VERSION 5.7 ;
BUSBITCHARS "[]" ;
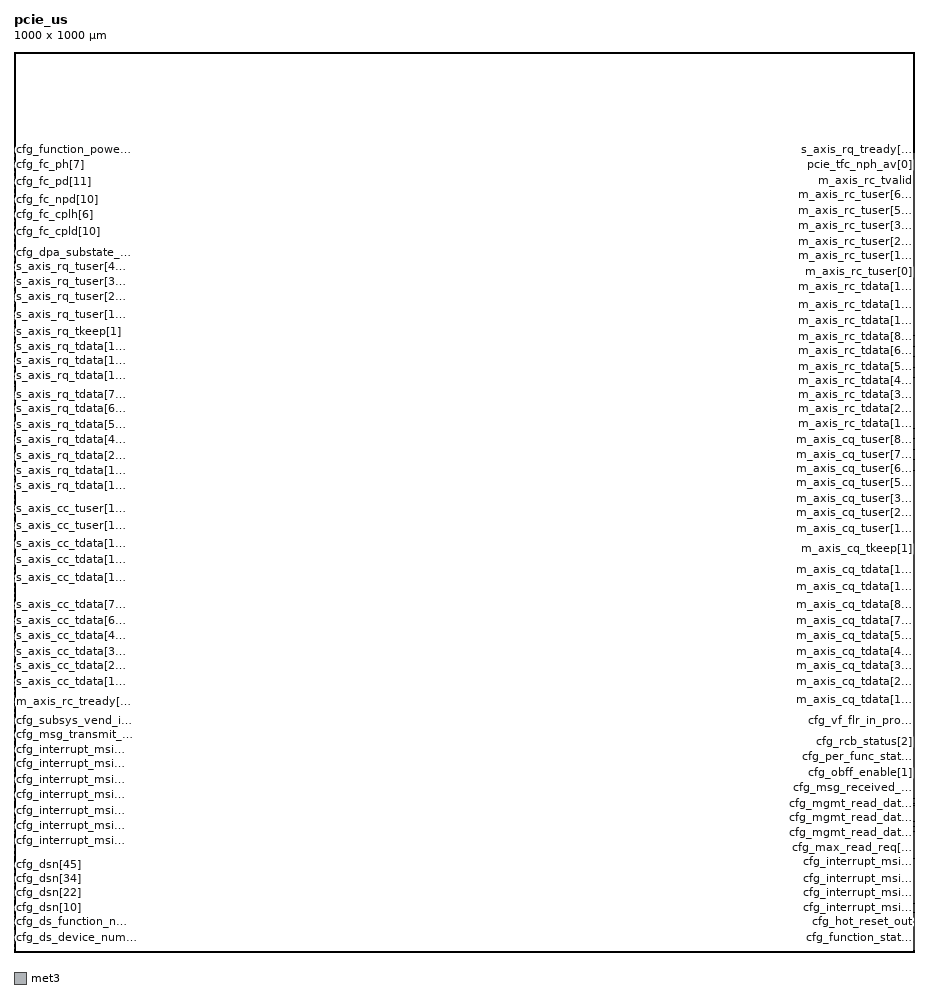
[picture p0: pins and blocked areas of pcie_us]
MACRO pcie_us
  CLASS BLOCK ;
  FOREIGN pcie_us 0 0 ;
  SYMMETRY X Y R90 ;
  SIZE 1000.000 BY 1000.000 ;
  PIN cfg_config_space_enable
    DIRECTION INPUT ;
    USE SIGNAL ;
    PORT
      LAYER met3 ;
      RECT 0.000 2.910 0.680 3.210 ;
    END
  END cfg_config_space_enable
  PIN cfg_ds_bus_number[0]
    DIRECTION INPUT ;
    USE SIGNAL ;
    PORT
      LAYER met3 ;
      RECT 0.000 4.270 0.680 4.570 ;
    END
  END cfg_ds_bus_number[0]
  PIN cfg_ds_bus_number[1]
    DIRECTION INPUT ;
    USE SIGNAL ;
    PORT
      LAYER met3 ;
      RECT 0.000 5.630 0.680 5.930 ;
    END
  END cfg_ds_bus_number[1]
  PIN cfg_ds_bus_number[2]
    DIRECTION INPUT ;
    USE SIGNAL ;
    PORT
      LAYER met3 ;
      RECT 0.000 6.990 0.680 7.290 ;
    END
  END cfg_ds_bus_number[2]
  PIN cfg_ds_bus_number[3]
    DIRECTION INPUT ;
    USE SIGNAL ;
    PORT
      LAYER met3 ;
      RECT 0.000 8.350 0.680 8.650 ;
    END
  END cfg_ds_bus_number[3]
  PIN cfg_ds_bus_number[4]
    DIRECTION INPUT ;
    USE SIGNAL ;
    PORT
      LAYER met3 ;
      RECT 0.000 9.710 0.680 10.010 ;
    END
  END cfg_ds_bus_number[4]
  PIN cfg_ds_bus_number[5]
    DIRECTION INPUT ;
    USE SIGNAL ;
    PORT
      LAYER met3 ;
      RECT 0.000 11.070 0.680 11.370 ;
    END
  END cfg_ds_bus_number[5]
  PIN cfg_ds_bus_number[6]
    DIRECTION INPUT ;
    USE SIGNAL ;
    PORT
      LAYER met3 ;
      RECT 0.000 12.430 0.680 12.730 ;
    END
  END cfg_ds_bus_number[6]
  PIN cfg_ds_bus_number[7]
    DIRECTION INPUT ;
    USE SIGNAL ;
    PORT
      LAYER met3 ;
      RECT 0.000 13.790 0.680 14.090 ;
    END
  END cfg_ds_bus_number[7]
  PIN cfg_ds_device_number[0]
    DIRECTION INPUT ;
    USE SIGNAL ;
    PORT
      LAYER met3 ;
      RECT 0.000 15.150 0.680 15.450 ;
    END
  END cfg_ds_device_number[0]
  PIN cfg_ds_device_number[1]
    DIRECTION INPUT ;
    USE SIGNAL ;
    PORT
      LAYER met3 ;
      RECT 0.000 16.510 0.680 16.810 ;
    END
  END cfg_ds_device_number[1]
  PIN cfg_ds_device_number[2]
    DIRECTION INPUT ;
    USE SIGNAL ;
    PORT
      LAYER met3 ;
      RECT 0.000 17.190 0.680 17.490 ;
    END
  END cfg_ds_device_number[2]
  PIN cfg_ds_device_number[3]
    DIRECTION INPUT ;
    USE SIGNAL ;
    PORT
      LAYER met3 ;
      RECT 0.000 18.550 0.680 18.850 ;
    END
  END cfg_ds_device_number[3]
  PIN cfg_ds_device_number[4]
    DIRECTION INPUT ;
    USE SIGNAL ;
    PORT
      LAYER met3 ;
      RECT 0.000 19.910 0.680 20.210 ;
    END
  END cfg_ds_device_number[4]
  PIN cfg_ds_function_number[0]
    DIRECTION INPUT ;
    USE SIGNAL ;
    PORT
      LAYER met3 ;
      RECT 0.000 21.950 0.680 22.250 ;
    END
  END cfg_ds_function_number[0]
  PIN cfg_ds_function_number[1]
    DIRECTION INPUT ;
    USE SIGNAL ;
    PORT
      LAYER met3 ;
      RECT 0.000 23.310 0.680 23.610 ;
    END
  END cfg_ds_function_number[1]
  PIN cfg_ds_function_number[2]
    DIRECTION INPUT ;
    USE SIGNAL ;
    PORT
      LAYER met3 ;
      RECT 0.000 24.670 0.680 24.970 ;
    END
  END cfg_ds_function_number[2]
  PIN cfg_ds_port_number
    DIRECTION INPUT ;
    USE SIGNAL ;
    PORT
      LAYER met3 ;
      RECT 0.000 26.030 0.680 26.330 ;
    END
  END cfg_ds_port_number
  PIN cfg_dsn[0]
    DIRECTION INPUT ;
    USE SIGNAL ;
    PORT
      LAYER met3 ;
      RECT 0.000 26.710 0.680 27.010 ;
    END
  END cfg_dsn[0]
  PIN cfg_dsn[1]
    DIRECTION INPUT ;
    USE SIGNAL ;
    PORT
      LAYER met3 ;
      RECT 0.000 28.750 0.680 29.050 ;
    END
  END cfg_dsn[1]
  PIN cfg_dsn[2]
    DIRECTION INPUT ;
    USE SIGNAL ;
    PORT
      LAYER met3 ;
      RECT 0.000 30.110 0.680 30.410 ;
    END
  END cfg_dsn[2]
  PIN cfg_dsn[3]
    DIRECTION INPUT ;
    USE SIGNAL ;
    PORT
      LAYER met3 ;
      RECT 0.000 31.470 0.680 31.770 ;
    END
  END cfg_dsn[3]
  PIN cfg_dsn[4]
    DIRECTION INPUT ;
    USE SIGNAL ;
    PORT
      LAYER met3 ;
      RECT 0.000 32.150 0.680 32.450 ;
    END
  END cfg_dsn[4]
  PIN cfg_dsn[5]
    DIRECTION INPUT ;
    USE SIGNAL ;
    PORT
      LAYER met3 ;
      RECT 0.000 33.510 0.680 33.810 ;
    END
  END cfg_dsn[5]
  PIN cfg_dsn[6]
    DIRECTION INPUT ;
    USE SIGNAL ;
    PORT
      LAYER met3 ;
      RECT 0.000 34.870 0.680 35.170 ;
    END
  END cfg_dsn[6]
  PIN cfg_dsn[7]
    DIRECTION INPUT ;
    USE SIGNAL ;
    PORT
      LAYER met3 ;
      RECT 0.000 36.230 0.680 36.530 ;
    END
  END cfg_dsn[7]
  PIN cfg_dsn[8]
    DIRECTION INPUT ;
    USE SIGNAL ;
    PORT
      LAYER met3 ;
      RECT 0.000 37.590 0.680 37.890 ;
    END
  END cfg_dsn[8]
  PIN cfg_dsn[9]
    DIRECTION INPUT ;
    USE SIGNAL ;
    PORT
      LAYER met3 ;
      RECT 0.000 39.630 0.680 39.930 ;
    END
  END cfg_dsn[9]
  PIN cfg_dsn[10]
    DIRECTION INPUT ;
    USE SIGNAL ;
    PORT
      LAYER met3 ;
      RECT 0.000 40.990 0.680 41.290 ;
    END
  END cfg_dsn[10]
  PIN cfg_dsn[11]
    DIRECTION INPUT ;
    USE SIGNAL ;
    PORT
      LAYER met3 ;
      RECT 0.000 41.670 0.680 41.970 ;
    END
  END cfg_dsn[11]
  PIN cfg_dsn[12]
    DIRECTION INPUT ;
    USE SIGNAL ;
    PORT
      LAYER met3 ;
      RECT 0.000 43.030 0.680 43.330 ;
    END
  END cfg_dsn[12]
  PIN cfg_dsn[13]
    DIRECTION INPUT ;
    USE SIGNAL ;
    PORT
      LAYER met3 ;
      RECT 0.000 45.070 0.680 45.370 ;
    END
  END cfg_dsn[13]
  PIN cfg_dsn[14]
    DIRECTION INPUT ;
    USE SIGNAL ;
    PORT
      LAYER met3 ;
      RECT 0.000 46.430 0.680 46.730 ;
    END
  END cfg_dsn[14]
  PIN cfg_dsn[15]
    DIRECTION INPUT ;
    USE SIGNAL ;
    PORT
      LAYER met3 ;
      RECT 0.000 47.110 0.680 47.410 ;
    END
  END cfg_dsn[15]
  PIN cfg_dsn[16]
    DIRECTION INPUT ;
    USE SIGNAL ;
    PORT
      LAYER met3 ;
      RECT 0.000 48.470 0.680 48.770 ;
    END
  END cfg_dsn[16]
  PIN cfg_dsn[17]
    DIRECTION INPUT ;
    USE SIGNAL ;
    PORT
      LAYER met3 ;
      RECT 0.000 49.830 0.680 50.130 ;
    END
  END cfg_dsn[17]
  PIN cfg_dsn[18]
    DIRECTION INPUT ;
    USE SIGNAL ;
    PORT
      LAYER met3 ;
      RECT 0.000 51.190 0.680 51.490 ;
    END
  END cfg_dsn[18]
  PIN cfg_dsn[19]
    DIRECTION INPUT ;
    USE SIGNAL ;
    PORT
      LAYER met3 ;
      RECT 0.000 52.550 0.680 52.850 ;
    END
  END cfg_dsn[19]
  PIN cfg_dsn[20]
    DIRECTION INPUT ;
    USE SIGNAL ;
    PORT
      LAYER met3 ;
      RECT 0.000 54.590 0.680 54.890 ;
    END
  END cfg_dsn[20]
  PIN cfg_dsn[21]
    DIRECTION INPUT ;
    USE SIGNAL ;
    PORT
      LAYER met3 ;
      RECT 0.000 55.950 0.680 56.250 ;
    END
  END cfg_dsn[21]
  PIN cfg_dsn[22]
    DIRECTION INPUT ;
    USE SIGNAL ;
    PORT
      LAYER met3 ;
      RECT 0.000 57.310 0.680 57.610 ;
    END
  END cfg_dsn[22]
  PIN cfg_dsn[23]
    DIRECTION INPUT ;
    USE SIGNAL ;
    PORT
      LAYER met3 ;
      RECT 0.000 58.670 0.680 58.970 ;
    END
  END cfg_dsn[23]
  PIN cfg_dsn[24]
    DIRECTION INPUT ;
    USE SIGNAL ;
    PORT
      LAYER met3 ;
      RECT 0.000 60.030 0.680 60.330 ;
    END
  END cfg_dsn[24]
  PIN cfg_dsn[25]
    DIRECTION INPUT ;
    USE SIGNAL ;
    PORT
      LAYER met3 ;
      RECT 0.000 60.710 0.680 61.010 ;
    END
  END cfg_dsn[25]
  PIN cfg_dsn[26]
    DIRECTION INPUT ;
    USE SIGNAL ;
    PORT
      LAYER met3 ;
      RECT 0.000 62.070 0.680 62.370 ;
    END
  END cfg_dsn[26]
  PIN cfg_dsn[27]
    DIRECTION INPUT ;
    USE SIGNAL ;
    PORT
      LAYER met3 ;
      RECT 0.000 63.430 0.680 63.730 ;
    END
  END cfg_dsn[27]
  PIN cfg_dsn[28]
    DIRECTION INPUT ;
    USE SIGNAL ;
    PORT
      LAYER met3 ;
      RECT 0.000 64.790 0.680 65.090 ;
    END
  END cfg_dsn[28]
  PIN cfg_dsn[29]
    DIRECTION INPUT ;
    USE SIGNAL ;
    PORT
      LAYER met3 ;
      RECT 0.000 66.150 0.680 66.450 ;
    END
  END cfg_dsn[29]
  PIN cfg_dsn[30]
    DIRECTION INPUT ;
    USE SIGNAL ;
    PORT
      LAYER met3 ;
      RECT 0.000 67.510 0.680 67.810 ;
    END
  END cfg_dsn[30]
  PIN cfg_dsn[31]
    DIRECTION INPUT ;
    USE SIGNAL ;
    PORT
      LAYER met3 ;
      RECT 0.000 68.870 0.680 69.170 ;
    END
  END cfg_dsn[31]
  PIN cfg_dsn[32]
    DIRECTION INPUT ;
    USE SIGNAL ;
    PORT
      LAYER met3 ;
      RECT 0.000 70.230 0.680 70.530 ;
    END
  END cfg_dsn[32]
  PIN cfg_dsn[33]
    DIRECTION INPUT ;
    USE SIGNAL ;
    PORT
      LAYER met3 ;
      RECT 0.000 71.590 0.680 71.890 ;
    END
  END cfg_dsn[33]
  PIN cfg_dsn[34]
    DIRECTION INPUT ;
    USE SIGNAL ;
    PORT
      LAYER met3 ;
      RECT 0.000 72.950 0.680 73.250 ;
    END
  END cfg_dsn[34]
  PIN cfg_dsn[35]
    DIRECTION INPUT ;
    USE SIGNAL ;
    PORT
      LAYER met3 ;
      RECT 0.000 74.310 0.680 74.610 ;
    END
  END cfg_dsn[35]
  PIN cfg_dsn[36]
    DIRECTION INPUT ;
    USE SIGNAL ;
    PORT
      LAYER met3 ;
      RECT 0.000 76.350 0.680 76.650 ;
    END
  END cfg_dsn[36]
  PIN cfg_dsn[37]
    DIRECTION INPUT ;
    USE SIGNAL ;
    PORT
      LAYER met3 ;
      RECT 0.000 77.710 0.680 78.010 ;
    END
  END cfg_dsn[37]
  PIN cfg_dsn[38]
    DIRECTION INPUT ;
    USE SIGNAL ;
    PORT
      LAYER met3 ;
      RECT 0.000 79.070 0.680 79.370 ;
    END
  END cfg_dsn[38]
  PIN cfg_dsn[39]
    DIRECTION INPUT ;
    USE SIGNAL ;
    PORT
      LAYER met3 ;
      RECT 0.000 80.430 0.680 80.730 ;
    END
  END cfg_dsn[39]
  PIN cfg_dsn[40]
    DIRECTION INPUT ;
    USE SIGNAL ;
    PORT
      LAYER met3 ;
      RECT 0.000 81.790 0.680 82.090 ;
    END
  END cfg_dsn[40]
  PIN cfg_dsn[41]
    DIRECTION INPUT ;
    USE SIGNAL ;
    PORT
      LAYER met3 ;
      RECT 0.000 83.150 0.680 83.450 ;
    END
  END cfg_dsn[41]
  PIN cfg_dsn[42]
    DIRECTION INPUT ;
    USE SIGNAL ;
    PORT
      LAYER met3 ;
      RECT 0.000 84.510 0.680 84.810 ;
    END
  END cfg_dsn[42]
  PIN cfg_dsn[43]
    DIRECTION INPUT ;
    USE SIGNAL ;
    PORT
      LAYER met3 ;
      RECT 0.000 85.870 0.680 86.170 ;
    END
  END cfg_dsn[43]
  PIN cfg_dsn[44]
    DIRECTION INPUT ;
    USE SIGNAL ;
    PORT
      LAYER met3 ;
      RECT 0.000 87.230 0.680 87.530 ;
    END
  END cfg_dsn[44]
  PIN cfg_dsn[45]
    DIRECTION INPUT ;
    USE SIGNAL ;
    PORT
      LAYER met3 ;
      RECT 0.000 88.590 0.680 88.890 ;
    END
  END cfg_dsn[45]
  PIN cfg_dsn[46]
    DIRECTION INPUT ;
    USE SIGNAL ;
    PORT
      LAYER met3 ;
      RECT 0.000 89.950 0.680 90.250 ;
    END
  END cfg_dsn[46]
  PIN cfg_dsn[47]
    DIRECTION INPUT ;
    USE SIGNAL ;
    PORT
      LAYER met3 ;
      RECT 0.000 91.310 0.680 91.610 ;
    END
  END cfg_dsn[47]
  PIN cfg_dsn[48]
    DIRECTION INPUT ;
    USE SIGNAL ;
    PORT
      LAYER met3 ;
      RECT 0.000 92.670 0.680 92.970 ;
    END
  END cfg_dsn[48]
  PIN cfg_dsn[49]
    DIRECTION INPUT ;
    USE SIGNAL ;
    PORT
      LAYER met3 ;
      RECT 0.000 94.030 0.680 94.330 ;
    END
  END cfg_dsn[49]
  PIN cfg_dsn[50]
    DIRECTION INPUT ;
    USE SIGNAL ;
    PORT
      LAYER met3 ;
      RECT 0.000 95.390 0.680 95.690 ;
    END
  END cfg_dsn[50]
  PIN cfg_dsn[51]
    DIRECTION INPUT ;
    USE SIGNAL ;
    PORT
      LAYER met3 ;
      RECT 0.000 96.750 0.680 97.050 ;
    END
  END cfg_dsn[51]
  PIN cfg_dsn[52]
    DIRECTION INPUT ;
    USE SIGNAL ;
    PORT
      LAYER met3 ;
      RECT 0.000 98.110 0.680 98.410 ;
    END
  END cfg_dsn[52]
  PIN cfg_dsn[53]
    DIRECTION INPUT ;
    USE SIGNAL ;
    PORT
      LAYER met3 ;
      RECT 0.000 99.470 0.680 99.770 ;
    END
  END cfg_dsn[53]
  PIN cfg_dsn[54]
    DIRECTION INPUT ;
    USE SIGNAL ;
    PORT
      LAYER met3 ;
      RECT 0.000 100.150 0.680 100.450 ;
    END
  END cfg_dsn[54]
  PIN cfg_dsn[55]
    DIRECTION INPUT ;
    USE SIGNAL ;
    PORT
      LAYER met3 ;
      RECT 0.000 101.510 0.680 101.810 ;
    END
  END cfg_dsn[55]
  PIN cfg_dsn[56]
    DIRECTION INPUT ;
    USE SIGNAL ;
    PORT
      LAYER met3 ;
      RECT 0.000 102.870 0.680 103.170 ;
    END
  END cfg_dsn[56]
  PIN cfg_dsn[57]
    DIRECTION INPUT ;
    USE SIGNAL ;
    PORT
      LAYER met3 ;
      RECT 0.000 104.910 0.680 105.210 ;
    END
  END cfg_dsn[57]
  PIN cfg_dsn[58]
    DIRECTION INPUT ;
    USE SIGNAL ;
    PORT
      LAYER met3 ;
      RECT 0.000 106.270 0.680 106.570 ;
    END
  END cfg_dsn[58]
  PIN cfg_dsn[59]
    DIRECTION INPUT ;
    USE SIGNAL ;
    PORT
      LAYER met3 ;
      RECT 0.000 107.630 0.680 107.930 ;
    END
  END cfg_dsn[59]
  PIN cfg_dsn[60]
    DIRECTION INPUT ;
    USE SIGNAL ;
    PORT
      LAYER met3 ;
      RECT 0.000 108.990 0.680 109.290 ;
    END
  END cfg_dsn[60]
  PIN cfg_dsn[61]
    DIRECTION INPUT ;
    USE SIGNAL ;
    PORT
      LAYER met3 ;
      RECT 0.000 110.350 0.680 110.650 ;
    END
  END cfg_dsn[61]
  PIN cfg_dsn[62]
    DIRECTION INPUT ;
    USE SIGNAL ;
    PORT
      LAYER met3 ;
      RECT 0.000 111.710 0.680 112.010 ;
    END
  END cfg_dsn[62]
  PIN cfg_dsn[63]
    DIRECTION INPUT ;
    USE SIGNAL ;
    PORT
      LAYER met3 ;
      RECT 0.000 113.070 0.680 113.370 ;
    END
  END cfg_dsn[63]
  PIN cfg_err_cor_in
    DIRECTION INPUT ;
    USE SIGNAL ;
    PORT
      LAYER met3 ;
      RECT 0.000 114.430 0.680 114.730 ;
    END
  END cfg_err_cor_in
  PIN cfg_err_uncor_in
    DIRECTION INPUT ;
    USE SIGNAL ;
    PORT
      LAYER met3 ;
      RECT 0.000 115.790 0.680 116.090 ;
    END
  END cfg_err_uncor_in
  PIN cfg_fc_sel
    DIRECTION INPUT ;
    USE SIGNAL ;
    PORT
      LAYER met3 ;
      RECT 0.000 117.150 0.680 117.450 ;
    END
  END cfg_fc_sel
  PIN cfg_flr_done
    DIRECTION INPUT ;
    USE SIGNAL ;
    PORT
      LAYER met3 ;
      RECT 0.000 118.510 0.680 118.810 ;
    END
  END cfg_flr_done
  PIN cfg_hot_reset_in
    DIRECTION INPUT ;
    USE SIGNAL ;
    PORT
      LAYER met3 ;
      RECT 0.000 119.870 0.680 120.170 ;
    END
  END cfg_hot_reset_in
  PIN cfg_interrupt_int
    DIRECTION INPUT ;
    USE SIGNAL ;
    PORT
      LAYER met3 ;
      RECT 0.000 121.230 0.680 121.530 ;
    END
  END cfg_interrupt_int
  PIN cfg_interrupt_msi_attr
    DIRECTION INPUT ;
    USE SIGNAL ;
    PORT
      LAYER met3 ;
      RECT 0.000 122.590 0.680 122.890 ;
    END
  END cfg_interrupt_msi_attr
  PIN cfg_interrupt_msi_function_number
    DIRECTION INPUT ;
    USE SIGNAL ;
    PORT
      LAYER met3 ;
      RECT 0.000 123.950 0.680 124.250 ;
    END
  END cfg_interrupt_msi_function_number
  PIN cfg_interrupt_msi_int[0]
    DIRECTION INPUT ;
    USE SIGNAL ;
    PORT
      LAYER met3 ;
      RECT 0.000 125.310 0.680 125.610 ;
    END
  END cfg_interrupt_msi_int[0]
  PIN cfg_interrupt_msi_int[1]
    DIRECTION INPUT ;
    USE SIGNAL ;
    PORT
      LAYER met3 ;
      RECT 0.000 126.670 0.680 126.970 ;
    END
  END cfg_interrupt_msi_int[1]
  PIN cfg_interrupt_msi_int[2]
    DIRECTION INPUT ;
    USE SIGNAL ;
    PORT
      LAYER met3 ;
      RECT 0.000 128.030 0.680 128.330 ;
    END
  END cfg_interrupt_msi_int[2]
  PIN cfg_interrupt_msi_int[3]
    DIRECTION INPUT ;
    USE SIGNAL ;
    PORT
      LAYER met3 ;
      RECT 0.000 129.390 0.680 129.690 ;
    END
  END cfg_interrupt_msi_int[3]
  PIN cfg_interrupt_msi_int[4]
    DIRECTION INPUT ;
    USE SIGNAL ;
    PORT
      LAYER met3 ;
      RECT 0.000 130.070 0.680 130.370 ;
    END
  END cfg_interrupt_msi_int[4]
  PIN cfg_interrupt_msi_int[5]
    DIRECTION INPUT ;
    USE SIGNAL ;
    PORT
      LAYER met3 ;
      RECT 0.000 132.110 0.680 132.410 ;
    END
  END cfg_interrupt_msi_int[5]
  PIN cfg_interrupt_msi_int[6]
    DIRECTION INPUT ;
    USE SIGNAL ;
    PORT
      LAYER met3 ;
      RECT 0.000 132.790 0.680 133.090 ;
    END
  END cfg_interrupt_msi_int[6]
  PIN cfg_interrupt_msi_int[7]
    DIRECTION INPUT ;
    USE SIGNAL ;
    PORT
      LAYER met3 ;
      RECT 0.000 134.830 0.680 135.130 ;
    END
  END cfg_interrupt_msi_int[7]
  PIN cfg_interrupt_msi_int[8]
    DIRECTION INPUT ;
    USE SIGNAL ;
    PORT
      LAYER met3 ;
      RECT 0.000 135.510 0.680 135.810 ;
    END
  END cfg_interrupt_msi_int[8]
  PIN cfg_interrupt_msi_int[9]
    DIRECTION INPUT ;
    USE SIGNAL ;
    PORT
      LAYER met3 ;
      RECT 0.000 137.550 0.680 137.850 ;
    END
  END cfg_interrupt_msi_int[9]
  PIN cfg_interrupt_msi_int[10]
    DIRECTION INPUT ;
    USE SIGNAL ;
    PORT
      LAYER met3 ;
      RECT 0.000 138.230 0.680 138.530 ;
    END
  END cfg_interrupt_msi_int[10]
  PIN cfg_interrupt_msi_int[11]
    DIRECTION INPUT ;
    USE SIGNAL ;
    PORT
      LAYER met3 ;
      RECT 0.000 140.270 0.680 140.570 ;
    END
  END cfg_interrupt_msi_int[11]
  PIN cfg_interrupt_msi_int[12]
    DIRECTION INPUT ;
    USE SIGNAL ;
    PORT
      LAYER met3 ;
      RECT 0.000 140.950 0.680 141.250 ;
    END
  END cfg_interrupt_msi_int[12]
  PIN cfg_interrupt_msi_int[13]
    DIRECTION INPUT ;
    USE SIGNAL ;
    PORT
      LAYER met3 ;
      RECT 0.000 142.990 0.680 143.290 ;
    END
  END cfg_interrupt_msi_int[13]
  PIN cfg_interrupt_msi_int[14]
    DIRECTION INPUT ;
    USE SIGNAL ;
    PORT
      LAYER met3 ;
      RECT 0.000 143.670 0.680 143.970 ;
    END
  END cfg_interrupt_msi_int[14]
  PIN cfg_interrupt_msi_int[15]
    DIRECTION INPUT ;
    USE SIGNAL ;
    PORT
      LAYER met3 ;
      RECT 0.000 145.710 0.680 146.010 ;
    END
  END cfg_interrupt_msi_int[15]
  PIN cfg_interrupt_msi_int[16]
    DIRECTION INPUT ;
    USE SIGNAL ;
    PORT
      LAYER met3 ;
      RECT 0.000 146.390 0.680 146.690 ;
    END
  END cfg_interrupt_msi_int[16]
  PIN cfg_interrupt_msi_int[17]
    DIRECTION INPUT ;
    USE SIGNAL ;
    PORT
      LAYER met3 ;
      RECT 0.000 148.430 0.680 148.730 ;
    END
  END cfg_interrupt_msi_int[17]
  PIN cfg_interrupt_msi_int[18]
    DIRECTION INPUT ;
    USE SIGNAL ;
    PORT
      LAYER met3 ;
      RECT 0.000 149.790 0.680 150.090 ;
    END
  END cfg_interrupt_msi_int[18]
  PIN cfg_interrupt_msi_int[19]
    DIRECTION INPUT ;
    USE SIGNAL ;
    PORT
      LAYER met3 ;
      RECT 0.000 151.150 0.680 151.450 ;
    END
  END cfg_interrupt_msi_int[19]
  PIN cfg_interrupt_msi_int[20]
    DIRECTION INPUT ;
    USE SIGNAL ;
    PORT
      LAYER met3 ;
      RECT 0.000 152.510 0.680 152.810 ;
    END
  END cfg_interrupt_msi_int[20]
  PIN cfg_interrupt_msi_int[21]
    DIRECTION INPUT ;
    USE SIGNAL ;
    PORT
      LAYER met3 ;
      RECT 0.000 153.870 0.680 154.170 ;
    END
  END cfg_interrupt_msi_int[21]
  PIN cfg_interrupt_msi_int[22]
    DIRECTION INPUT ;
    USE SIGNAL ;
    PORT
      LAYER met3 ;
      RECT 0.000 155.230 0.680 155.530 ;
    END
  END cfg_interrupt_msi_int[22]
  PIN cfg_interrupt_msi_int[23]
    DIRECTION INPUT ;
    USE SIGNAL ;
    PORT
      LAYER met3 ;
      RECT 0.000 156.590 0.680 156.890 ;
    END
  END cfg_interrupt_msi_int[23]
  PIN cfg_interrupt_msi_int[24]
    DIRECTION INPUT ;
    USE SIGNAL ;
    PORT
      LAYER met3 ;
      RECT 0.000 157.950 0.680 158.250 ;
    END
  END cfg_interrupt_msi_int[24]
  PIN cfg_interrupt_msi_int[25]
    DIRECTION INPUT ;
    USE SIGNAL ;
    PORT
      LAYER met3 ;
      RECT 0.000 158.630 0.680 158.930 ;
    END
  END cfg_interrupt_msi_int[25]
  PIN cfg_interrupt_msi_int[26]
    DIRECTION INPUT ;
    USE SIGNAL ;
    PORT
      LAYER met3 ;
      RECT 0.000 160.670 0.680 160.970 ;
    END
  END cfg_interrupt_msi_int[26]
  PIN cfg_interrupt_msi_int[27]
    DIRECTION INPUT ;
    USE SIGNAL ;
    PORT
      LAYER met3 ;
      RECT 0.000 161.350 0.680 161.650 ;
    END
  END cfg_interrupt_msi_int[27]
  PIN cfg_interrupt_msi_int[28]
    DIRECTION INPUT ;
    USE SIGNAL ;
    PORT
      LAYER met3 ;
      RECT 0.000 163.390 0.680 163.690 ;
    END
  END cfg_interrupt_msi_int[28]
  PIN cfg_interrupt_msi_int[29]
    DIRECTION INPUT ;
    USE SIGNAL ;
    PORT
      LAYER met3 ;
      RECT 0.000 164.070 0.680 164.370 ;
    END
  END cfg_interrupt_msi_int[29]
  PIN cfg_interrupt_msi_int[30]
    DIRECTION INPUT ;
    USE SIGNAL ;
    PORT
      LAYER met3 ;
      RECT 0.000 166.110 0.680 166.410 ;
    END
  END cfg_interrupt_msi_int[30]
  PIN cfg_interrupt_msi_int[31]
    DIRECTION INPUT ;
    USE SIGNAL ;
    PORT
      LAYER met3 ;
      RECT 0.000 166.790 0.680 167.090 ;
    END
  END cfg_interrupt_msi_int[31]
  PIN cfg_interrupt_msi_pending_status[0]
    DIRECTION INPUT ;
    USE SIGNAL ;
    PORT
      LAYER met3 ;
      RECT 0.000 168.830 0.680 169.130 ;
    END
  END cfg_interrupt_msi_pending_status[0]
  PIN cfg_interrupt_msi_pending_status[1]
    DIRECTION INPUT ;
    USE SIGNAL ;
    PORT
      LAYER met3 ;
      RECT 0.000 169.510 0.680 169.810 ;
    END
  END cfg_interrupt_msi_pending_status[1]
  PIN cfg_interrupt_msi_pending_status[2]
    DIRECTION INPUT ;
    USE SIGNAL ;
    PORT
      LAYER met3 ;
      RECT 0.000 171.550 0.680 171.850 ;
    END
  END cfg_interrupt_msi_pending_status[2]
  PIN cfg_interrupt_msi_pending_status[3]
    DIRECTION INPUT ;
    USE SIGNAL ;
    PORT
      LAYER met3 ;
      RECT 0.000 172.230 0.680 172.530 ;
    END
  END cfg_interrupt_msi_pending_status[3]
  PIN cfg_interrupt_msi_pending_status[4]
    DIRECTION INPUT ;
    USE SIGNAL ;
    PORT
      LAYER met3 ;
      RECT 0.000 174.270 0.680 174.570 ;
    END
  END cfg_interrupt_msi_pending_status[4]
  PIN cfg_interrupt_msi_pending_status[5]
    DIRECTION INPUT ;
    USE SIGNAL ;
    PORT
      LAYER met3 ;
      RECT 0.000 175.630 0.680 175.930 ;
    END
  END cfg_interrupt_msi_pending_status[5]
  PIN cfg_interrupt_msi_pending_status[6]
    DIRECTION INPUT ;
    USE SIGNAL ;
    PORT
      LAYER met3 ;
      RECT 0.000 176.990 0.680 177.290 ;
    END
  END cfg_interrupt_msi_pending_status[6]
  PIN cfg_interrupt_msi_pending_status[7]
    DIRECTION INPUT ;
    USE SIGNAL ;
    PORT
      LAYER met3 ;
      RECT 0.000 178.350 0.680 178.650 ;
    END
  END cfg_interrupt_msi_pending_status[7]
  PIN cfg_interrupt_msi_pending_status[8]
    DIRECTION INPUT ;
    USE SIGNAL ;
    PORT
      LAYER met3 ;
      RECT 0.000 179.710 0.680 180.010 ;
    END
  END cfg_interrupt_msi_pending_status[8]
  PIN cfg_interrupt_msi_pending_status[9]
    DIRECTION INPUT ;
    USE SIGNAL ;
    PORT
      LAYER met3 ;
      RECT 0.000 181.070 0.680 181.370 ;
    END
  END cfg_interrupt_msi_pending_status[9]
  PIN cfg_interrupt_msi_pending_status[10]
    DIRECTION INPUT ;
    USE SIGNAL ;
    PORT
      LAYER met3 ;
      RECT 0.000 182.430 0.680 182.730 ;
    END
  END cfg_interrupt_msi_pending_status[10]
  PIN cfg_interrupt_msi_pending_status[11]
    DIRECTION INPUT ;
    USE SIGNAL ;
    PORT
      LAYER met3 ;
      RECT 0.000 183.790 0.680 184.090 ;
    END
  END cfg_interrupt_msi_pending_status[11]
  PIN cfg_interrupt_msi_pending_status[12]
    DIRECTION INPUT ;
    USE SIGNAL ;
    PORT
      LAYER met3 ;
      RECT 0.000 185.150 0.680 185.450 ;
    END
  END cfg_interrupt_msi_pending_status[12]
  PIN cfg_interrupt_msi_pending_status[13]
    DIRECTION INPUT ;
    USE SIGNAL ;
    PORT
      LAYER met3 ;
      RECT 0.000 186.510 0.680 186.810 ;
    END
  END cfg_interrupt_msi_pending_status[13]
  PIN cfg_interrupt_msi_pending_status[14]
    DIRECTION INPUT ;
    USE SIGNAL ;
    PORT
      LAYER met3 ;
      RECT 0.000 187.870 0.680 188.170 ;
    END
  END cfg_interrupt_msi_pending_status[14]
  PIN cfg_interrupt_msi_pending_status[15]
    DIRECTION INPUT ;
    USE SIGNAL ;
    PORT
      LAYER met3 ;
      RECT 0.000 189.230 0.680 189.530 ;
    END
  END cfg_interrupt_msi_pending_status[15]
  PIN cfg_interrupt_msi_pending_status[16]
    DIRECTION INPUT ;
    USE SIGNAL ;
    PORT
      LAYER met3 ;
      RECT 0.000 190.590 0.680 190.890 ;
    END
  END cfg_interrupt_msi_pending_status[16]
  PIN cfg_interrupt_msi_pending_status[17]
    DIRECTION INPUT ;
    USE SIGNAL ;
    PORT
      LAYER met3 ;
      RECT 0.000 191.950 0.680 192.250 ;
    END
  END cfg_interrupt_msi_pending_status[17]
  PIN cfg_interrupt_msi_pending_status[18]
    DIRECTION INPUT ;
    USE SIGNAL ;
    PORT
      LAYER met3 ;
      RECT 0.000 193.310 0.680 193.610 ;
    END
  END cfg_interrupt_msi_pending_status[18]
  PIN cfg_interrupt_msi_pending_status[19]
    DIRECTION INPUT ;
    USE SIGNAL ;
    PORT
      LAYER met3 ;
      RECT 0.000 194.670 0.680 194.970 ;
    END
  END cfg_interrupt_msi_pending_status[19]
  PIN cfg_interrupt_msi_pending_status[20]
    DIRECTION INPUT ;
    USE SIGNAL ;
    PORT
      LAYER met3 ;
      RECT 0.000 196.030 0.680 196.330 ;
    END
  END cfg_interrupt_msi_pending_status[20]
  PIN cfg_interrupt_msi_pending_status[21]
    DIRECTION INPUT ;
    USE SIGNAL ;
    PORT
      LAYER met3 ;
      RECT 0.000 197.390 0.680 197.690 ;
    END
  END cfg_interrupt_msi_pending_status[21]
  PIN cfg_interrupt_msi_pending_status[22]
    DIRECTION INPUT ;
    USE SIGNAL ;
    PORT
      LAYER met3 ;
      RECT 0.000 198.750 0.680 199.050 ;
    END
  END cfg_interrupt_msi_pending_status[22]
  PIN cfg_interrupt_msi_pending_status[23]
    DIRECTION INPUT ;
    USE SIGNAL ;
    PORT
      LAYER met3 ;
      RECT 0.000 200.110 0.680 200.410 ;
    END
  END cfg_interrupt_msi_pending_status[23]
  PIN cfg_interrupt_msi_pending_status[24]
    DIRECTION INPUT ;
    USE SIGNAL ;
    PORT
      LAYER met3 ;
      RECT 0.000 201.470 0.680 201.770 ;
    END
  END cfg_interrupt_msi_pending_status[24]
  PIN cfg_interrupt_msi_pending_status[25]
    DIRECTION INPUT ;
    USE SIGNAL ;
    PORT
      LAYER met3 ;
      RECT 0.000 202.830 0.680 203.130 ;
    END
  END cfg_interrupt_msi_pending_status[25]
  PIN cfg_interrupt_msi_pending_status[26]
    DIRECTION INPUT ;
    USE SIGNAL ;
    PORT
      LAYER met3 ;
      RECT 0.000 204.190 0.680 204.490 ;
    END
  END cfg_interrupt_msi_pending_status[26]
  PIN cfg_interrupt_msi_pending_status[27]
    DIRECTION INPUT ;
    USE SIGNAL ;
    PORT
      LAYER met3 ;
      RECT 0.000 205.550 0.680 205.850 ;
    END
  END cfg_interrupt_msi_pending_status[27]
  PIN cfg_interrupt_msi_pending_status[28]
    DIRECTION INPUT ;
    USE SIGNAL ;
    PORT
      LAYER met3 ;
      RECT 0.000 206.910 0.680 207.210 ;
    END
  END cfg_interrupt_msi_pending_status[28]
  PIN cfg_interrupt_msi_pending_status[29]
    DIRECTION INPUT ;
    USE SIGNAL ;
    PORT
      LAYER met3 ;
      RECT 0.000 208.270 0.680 208.570 ;
    END
  END cfg_interrupt_msi_pending_status[29]
  PIN cfg_interrupt_msi_pending_status[30]
    DIRECTION INPUT ;
    USE SIGNAL ;
    PORT
      LAYER met3 ;
      RECT 0.000 209.630 0.680 209.930 ;
    END
  END cfg_interrupt_msi_pending_status[30]
  PIN cfg_interrupt_msi_pending_status[31]
    DIRECTION INPUT ;
    USE SIGNAL ;
    PORT
      LAYER met3 ;
      RECT 0.000 210.990 0.680 211.290 ;
    END
  END cfg_interrupt_msi_pending_status[31]
  PIN cfg_interrupt_msi_pending_status_data_enable
    DIRECTION INPUT ;
    USE SIGNAL ;
    PORT
      LAYER met3 ;
      RECT 0.000 212.350 0.680 212.650 ;
    END
  END cfg_interrupt_msi_pending_status_data_enable
  PIN cfg_interrupt_msi_pending_status_function_num
    DIRECTION INPUT ;
    USE SIGNAL ;
    PORT
      LAYER met3 ;
      RECT 0.000 213.710 0.680 214.010 ;
    END
  END cfg_interrupt_msi_pending_status_function_num
  PIN cfg_interrupt_msi_select
    DIRECTION INPUT ;
    USE SIGNAL ;
    PORT
      LAYER met3 ;
      RECT 0.000 215.070 0.680 215.370 ;
    END
  END cfg_interrupt_msi_select
  PIN cfg_interrupt_msi_tph_present
    DIRECTION INPUT ;
    USE SIGNAL ;
    PORT
      LAYER met3 ;
      RECT 0.000 216.430 0.680 216.730 ;
    END
  END cfg_interrupt_msi_tph_present
  PIN cfg_interrupt_msi_tph_st_tag
    DIRECTION INPUT ;
    USE SIGNAL ;
    PORT
      LAYER met3 ;
      RECT 0.000 217.790 0.680 218.090 ;
    END
  END cfg_interrupt_msi_tph_st_tag
  PIN cfg_interrupt_msi_tph_type
    DIRECTION INPUT ;
    USE SIGNAL ;
    PORT
      LAYER met3 ;
      RECT 0.000 219.150 0.680 219.450 ;
    END
  END cfg_interrupt_msi_tph_type
  PIN cfg_interrupt_pending
    DIRECTION INPUT ;
    USE SIGNAL ;
    PORT
      LAYER met3 ;
      RECT 0.000 220.510 0.680 220.810 ;
    END
  END cfg_interrupt_pending
  PIN cfg_link_training_enable
    DIRECTION INPUT ;
    USE SIGNAL ;
    PORT
      LAYER met3 ;
      RECT 0.000 221.870 0.680 222.170 ;
    END
  END cfg_link_training_enable
  PIN cfg_mgmt_addr
    DIRECTION INPUT ;
    USE SIGNAL ;
    PORT
      LAYER met3 ;
      RECT 0.000 223.230 0.680 223.530 ;
    END
  END cfg_mgmt_addr
  PIN cfg_mgmt_byte_enable
    DIRECTION INPUT ;
    USE SIGNAL ;
    PORT
      LAYER met3 ;
      RECT 0.000 224.590 0.680 224.890 ;
    END
  END cfg_mgmt_byte_enable
  PIN cfg_mgmt_read
    DIRECTION INPUT ;
    USE SIGNAL ;
    PORT
      LAYER met3 ;
      RECT 0.000 225.950 0.680 226.250 ;
    END
  END cfg_mgmt_read
  PIN cfg_mgmt_type1_cfg_reg_access
    DIRECTION INPUT ;
    USE SIGNAL ;
    PORT
      LAYER met3 ;
      RECT 0.000 227.310 0.680 227.610 ;
    END
  END cfg_mgmt_type1_cfg_reg_access
  PIN cfg_mgmt_write
    DIRECTION INPUT ;
    USE SIGNAL ;
    PORT
      LAYER met3 ;
      RECT 0.000 228.670 0.680 228.970 ;
    END
  END cfg_mgmt_write
  PIN cfg_mgmt_write_data
    DIRECTION INPUT ;
    USE SIGNAL ;
    PORT
      LAYER met3 ;
      RECT 0.000 230.030 0.680 230.330 ;
    END
  END cfg_mgmt_write_data
  PIN cfg_msg_transmit
    DIRECTION INPUT ;
    USE SIGNAL ;
    PORT
      LAYER met3 ;
      RECT 0.000 231.390 0.680 231.690 ;
    END
  END cfg_msg_transmit
  PIN cfg_msg_transmit_data
    DIRECTION INPUT ;
    USE SIGNAL ;
    PORT
      LAYER met3 ;
      RECT 0.000 232.750 0.680 233.050 ;
    END
  END cfg_msg_transmit_data
  PIN cfg_msg_transmit_type
    DIRECTION INPUT ;
    USE SIGNAL ;
    PORT
      LAYER met3 ;
      RECT 0.000 234.110 0.680 234.410 ;
    END
  END cfg_msg_transmit_type
  PIN cfg_per_func_status_control
    DIRECTION INPUT ;
    USE SIGNAL ;
    PORT
      LAYER met3 ;
      RECT 0.000 235.470 0.680 235.770 ;
    END
  END cfg_per_func_status_control
  PIN cfg_per_function_number
    DIRECTION INPUT ;
    USE SIGNAL ;
    PORT
      LAYER met3 ;
      RECT 0.000 236.830 0.680 237.130 ;
    END
  END cfg_per_function_number
  PIN cfg_per_function_output_request
    DIRECTION INPUT ;
    USE SIGNAL ;
    PORT
      LAYER met3 ;
      RECT 0.000 238.190 0.680 238.490 ;
    END
  END cfg_per_function_output_request
  PIN cfg_power_state_change_ack
    DIRECTION INPUT ;
    USE SIGNAL ;
    PORT
      LAYER met3 ;
      RECT 0.000 239.550 0.680 239.850 ;
    END
  END cfg_power_state_change_ack
  PIN cfg_req_pm_transition_l23_ready
    DIRECTION INPUT ;
    USE SIGNAL ;
    PORT
      LAYER met3 ;
      RECT 0.000 240.910 0.680 241.210 ;
    END
  END cfg_req_pm_transition_l23_ready
  PIN cfg_subsys_vend_id[0]
    DIRECTION INPUT ;
    USE SIGNAL ;
    PORT
      LAYER met3 ;
      RECT 0.000 242.270 0.680 242.570 ;
    END
  END cfg_subsys_vend_id[0]
  PIN cfg_subsys_vend_id[1]
    DIRECTION INPUT ;
    USE SIGNAL ;
    PORT
      LAYER met3 ;
      RECT 0.000 243.630 0.680 243.930 ;
    END
  END cfg_subsys_vend_id[1]
  PIN cfg_subsys_vend_id[2]
    DIRECTION INPUT ;
    USE SIGNAL ;
    PORT
      LAYER met3 ;
      RECT 0.000 244.990 0.680 245.290 ;
    END
  END cfg_subsys_vend_id[2]
  PIN cfg_subsys_vend_id[3]
    DIRECTION INPUT ;
    USE SIGNAL ;
    PORT
      LAYER met3 ;
      RECT 0.000 246.350 0.680 246.650 ;
    END
  END cfg_subsys_vend_id[3]
  PIN cfg_subsys_vend_id[4]
    DIRECTION INPUT ;
    USE SIGNAL ;
    PORT
      LAYER met3 ;
      RECT 0.000 247.710 0.680 248.010 ;
    END
  END cfg_subsys_vend_id[4]
  PIN cfg_subsys_vend_id[5]
    DIRECTION INPUT ;
    USE SIGNAL ;
    PORT
      LAYER met3 ;
      RECT 0.000 249.070 0.680 249.370 ;
    END
  END cfg_subsys_vend_id[5]
  PIN cfg_subsys_vend_id[6]
    DIRECTION INPUT ;
    USE SIGNAL ;
    PORT
      LAYER met3 ;
      RECT 0.000 250.430 0.680 250.730 ;
    END
  END cfg_subsys_vend_id[6]
  PIN cfg_subsys_vend_id[7]
    DIRECTION INPUT ;
    USE SIGNAL ;
    PORT
      LAYER met3 ;
      RECT 0.000 251.790 0.680 252.090 ;
    END
  END cfg_subsys_vend_id[7]
  PIN cfg_subsys_vend_id[8]
    DIRECTION INPUT ;
    USE SIGNAL ;
    PORT
      LAYER met3 ;
      RECT 0.000 253.150 0.680 253.450 ;
    END
  END cfg_subsys_vend_id[8]
  PIN cfg_subsys_vend_id[9]
    DIRECTION INPUT ;
    USE SIGNAL ;
    PORT
      LAYER met3 ;
      RECT 0.000 254.510 0.680 254.810 ;
    END
  END cfg_subsys_vend_id[9]
  PIN cfg_subsys_vend_id[10]
    DIRECTION INPUT ;
    USE SIGNAL ;
    PORT
      LAYER met3 ;
      RECT 0.000 255.870 0.680 256.170 ;
    END
  END cfg_subsys_vend_id[10]
  PIN cfg_subsys_vend_id[11]
    DIRECTION INPUT ;
    USE SIGNAL ;
    PORT
      LAYER met3 ;
      RECT 0.000 257.230 0.680 257.530 ;
    END
  END cfg_subsys_vend_id[11]
  PIN cfg_subsys_vend_id[12]
    DIRECTION INPUT ;
    USE SIGNAL ;
    PORT
      LAYER met3 ;
      RECT 0.000 258.590 0.680 258.890 ;
    END
  END cfg_subsys_vend_id[12]
  PIN cfg_vf_flr_done
    DIRECTION INPUT ;
    USE SIGNAL ;
    PORT
      LAYER met3 ;
      RECT 0.000 259.950 0.680 260.250 ;
    END
  END cfg_vf_flr_done
  PIN m_axis_cq_tready[0]
    DIRECTION INPUT ;
    USE SIGNAL ;
    PORT
      LAYER met3 ;
      RECT 0.000 261.310 0.680 261.610 ;
    END
  END m_axis_cq_tready[0]
  PIN m_axis_cq_tready[1]
    DIRECTION INPUT ;
    USE SIGNAL ;
    PORT
      LAYER met3 ;
      RECT 0.000 262.670 0.680 262.970 ;
    END
  END m_axis_cq_tready[1]
  PIN m_axis_cq_tready[2]
    DIRECTION INPUT ;
    USE SIGNAL ;
    PORT
      LAYER met3 ;
      RECT 0.000 264.030 0.680 264.330 ;
    END
  END m_axis_cq_tready[2]
  PIN m_axis_cq_tready[3]
    DIRECTION INPUT ;
    USE SIGNAL ;
    PORT
      LAYER met3 ;
      RECT 0.000 265.390 0.680 265.690 ;
    END
  END m_axis_cq_tready[3]
  PIN m_axis_rc_tready[0]
    DIRECTION INPUT ;
    USE SIGNAL ;
    PORT
      LAYER met3 ;
      RECT 0.000 266.750 0.680 267.050 ;
    END
  END m_axis_rc_tready[0]
  PIN m_axis_rc_tready[1]
    DIRECTION INPUT ;
    USE SIGNAL ;
    PORT
      LAYER met3 ;
      RECT 0.000 268.110 0.680 268.410 ;
    END
  END m_axis_rc_tready[1]
  PIN m_axis_rc_tready[2]
    DIRECTION INPUT ;
    USE SIGNAL ;
    PORT
      LAYER met3 ;
      RECT 0.000 269.470 0.680 269.770 ;
    END
  END m_axis_rc_tready[2]
  PIN m_axis_rc_tready[3]
    DIRECTION INPUT ;
    USE SIGNAL ;
    PORT
      LAYER met3 ;
      RECT 0.000 270.830 0.680 271.130 ;
    END
  END m_axis_rc_tready[3]
  PIN pci_exp_rxn
    DIRECTION INPUT ;
    USE SIGNAL ;
    PORT
      LAYER met3 ;
      RECT 0.000 272.190 0.680 272.490 ;
    END
  END pci_exp_rxn
  PIN pci_exp_rxp
    DIRECTION INPUT ;
    USE SIGNAL ;
    PORT
      LAYER met3 ;
      RECT 0.000 273.550 0.680 273.850 ;
    END
  END pci_exp_rxp
  PIN pcie_cq_np_req
    DIRECTION INPUT ;
    USE SIGNAL ;
    PORT
      LAYER met3 ;
      RECT 0.000 274.910 0.680 275.210 ;
    END
  END pcie_cq_np_req
  PIN pcie_perstn1_in
    DIRECTION INPUT ;
    USE SIGNAL ;
    PORT
      LAYER met3 ;
      RECT 0.000 276.270 0.680 276.570 ;
    END
  END pcie_perstn1_in
  PIN s_axis_cc_tdata[0]
    DIRECTION INPUT ;
    USE SIGNAL ;
    PORT
      LAYER met3 ;
      RECT 0.000 277.630 0.680 277.930 ;
    END
  END s_axis_cc_tdata[0]
  PIN s_axis_cc_tdata[1]
    DIRECTION INPUT ;
    USE SIGNAL ;
    PORT
      LAYER met3 ;
      RECT 0.000 278.990 0.680 279.290 ;
    END
  END s_axis_cc_tdata[1]
  PIN s_axis_cc_tdata[2]
    DIRECTION INPUT ;
    USE SIGNAL ;
    PORT
      LAYER met3 ;
      RECT 0.000 280.350 0.680 280.650 ;
    END
  END s_axis_cc_tdata[2]
  PIN s_axis_cc_tdata[3]
    DIRECTION INPUT ;
    USE SIGNAL ;
    PORT
      LAYER met3 ;
      RECT 0.000 281.710 0.680 282.010 ;
    END
  END s_axis_cc_tdata[3]
  PIN s_axis_cc_tdata[4]
    DIRECTION INPUT ;
    USE SIGNAL ;
    PORT
      LAYER met3 ;
      RECT 0.000 283.070 0.680 283.370 ;
    END
  END s_axis_cc_tdata[4]
  PIN s_axis_cc_tdata[5]
    DIRECTION INPUT ;
    USE SIGNAL ;
    PORT
      LAYER met3 ;
      RECT 0.000 284.430 0.680 284.730 ;
    END
  END s_axis_cc_tdata[5]
  PIN s_axis_cc_tdata[6]
    DIRECTION INPUT ;
    USE SIGNAL ;
    PORT
      LAYER met3 ;
      RECT 0.000 285.790 0.680 286.090 ;
    END
  END s_axis_cc_tdata[6]
  PIN s_axis_cc_tdata[7]
    DIRECTION INPUT ;
    USE SIGNAL ;
    PORT
      LAYER met3 ;
      RECT 0.000 287.150 0.680 287.450 ;
    END
  END s_axis_cc_tdata[7]
  PIN s_axis_cc_tdata[8]
    DIRECTION INPUT ;
    USE SIGNAL ;
    PORT
      LAYER met3 ;
      RECT 0.000 288.510 0.680 288.810 ;
    END
  END s_axis_cc_tdata[8]
  PIN s_axis_cc_tdata[9]
    DIRECTION INPUT ;
    USE SIGNAL ;
    PORT
      LAYER met3 ;
      RECT 0.000 289.870 0.680 290.170 ;
    END
  END s_axis_cc_tdata[9]
  PIN s_axis_cc_tdata[10]
    DIRECTION INPUT ;
    USE SIGNAL ;
    PORT
      LAYER met3 ;
      RECT 0.000 291.230 0.680 291.530 ;
    END
  END s_axis_cc_tdata[10]
  PIN s_axis_cc_tdata[11]
    DIRECTION INPUT ;
    USE SIGNAL ;
    PORT
      LAYER met3 ;
      RECT 0.000 292.590 0.680 292.890 ;
    END
  END s_axis_cc_tdata[11]
  PIN s_axis_cc_tdata[12]
    DIRECTION INPUT ;
    USE SIGNAL ;
    PORT
      LAYER met3 ;
      RECT 0.000 293.950 0.680 294.250 ;
    END
  END s_axis_cc_tdata[12]
  PIN s_axis_cc_tdata[13]
    DIRECTION INPUT ;
    USE SIGNAL ;
    PORT
      LAYER met3 ;
      RECT 0.000 295.310 0.680 295.610 ;
    END
  END s_axis_cc_tdata[13]
  PIN s_axis_cc_tdata[14]
    DIRECTION INPUT ;
    USE SIGNAL ;
    PORT
      LAYER met3 ;
      RECT 0.000 296.670 0.680 296.970 ;
    END
  END s_axis_cc_tdata[14]
  PIN s_axis_cc_tdata[15]
    DIRECTION INPUT ;
    USE SIGNAL ;
    PORT
      LAYER met3 ;
      RECT 0.000 298.030 0.680 298.330 ;
    END
  END s_axis_cc_tdata[15]
  PIN s_axis_cc_tdata[16]
    DIRECTION INPUT ;
    USE SIGNAL ;
    PORT
      LAYER met3 ;
      RECT 0.000 299.390 0.680 299.690 ;
    END
  END s_axis_cc_tdata[16]
  PIN s_axis_cc_tdata[17]
    DIRECTION INPUT ;
    USE SIGNAL ;
    PORT
      LAYER met3 ;
      RECT 0.000 300.750 0.680 301.050 ;
    END
  END s_axis_cc_tdata[17]
  PIN s_axis_cc_tdata[18]
    DIRECTION INPUT ;
    USE SIGNAL ;
    PORT
      LAYER met3 ;
      RECT 0.000 302.110 0.680 302.410 ;
    END
  END s_axis_cc_tdata[18]
  PIN s_axis_cc_tdata[19]
    DIRECTION INPUT ;
    USE SIGNAL ;
    PORT
      LAYER met3 ;
      RECT 0.000 303.470 0.680 303.770 ;
    END
  END s_axis_cc_tdata[19]
  PIN s_axis_cc_tdata[20]
    DIRECTION INPUT ;
    USE SIGNAL ;
    PORT
      LAYER met3 ;
      RECT 0.000 304.830 0.680 305.130 ;
    END
  END s_axis_cc_tdata[20]
  PIN s_axis_cc_tdata[21]
    DIRECTION INPUT ;
    USE SIGNAL ;
    PORT
      LAYER met3 ;
      RECT 0.000 306.190 0.680 306.490 ;
    END
  END s_axis_cc_tdata[21]
  PIN s_axis_cc_tdata[22]
    DIRECTION INPUT ;
    USE SIGNAL ;
    PORT
      LAYER met3 ;
      RECT 0.000 307.550 0.680 307.850 ;
    END
  END s_axis_cc_tdata[22]
  PIN s_axis_cc_tdata[23]
    DIRECTION INPUT ;
    USE SIGNAL ;
    PORT
      LAYER met3 ;
      RECT 0.000 308.910 0.680 309.210 ;
    END
  END s_axis_cc_tdata[23]
  PIN s_axis_cc_tdata[24]
    DIRECTION INPUT ;
    USE SIGNAL ;
    PORT
      LAYER met3 ;
      RECT 0.000 310.270 0.680 310.570 ;
    END
  END s_axis_cc_tdata[24]
  PIN s_axis_cc_tdata[25]
    DIRECTION INPUT ;
    USE SIGNAL ;
    PORT
      LAYER met3 ;
      RECT 0.000 311.630 0.680 311.930 ;
    END
  END s_axis_cc_tdata[25]
  PIN s_axis_cc_tdata[26]
    DIRECTION INPUT ;
    USE SIGNAL ;
    PORT
      LAYER met3 ;
      RECT 0.000 312.990 0.680 313.290 ;
    END
  END s_axis_cc_tdata[26]
  PIN s_axis_cc_tdata[27]
    DIRECTION INPUT ;
    USE SIGNAL ;
    PORT
      LAYER met3 ;
      RECT 0.000 314.350 0.680 314.650 ;
    END
  END s_axis_cc_tdata[27]
  PIN s_axis_cc_tdata[28]
    DIRECTION INPUT ;
    USE SIGNAL ;
    PORT
      LAYER met3 ;
      RECT 0.000 315.710 0.680 316.010 ;
    END
  END s_axis_cc_tdata[28]
  PIN s_axis_cc_tdata[29]
    DIRECTION INPUT ;
    USE SIGNAL ;
    PORT
      LAYER met3 ;
      RECT 0.000 317.070 0.680 317.370 ;
    END
  END s_axis_cc_tdata[29]
  PIN s_axis_cc_tdata[30]
    DIRECTION INPUT ;
    USE SIGNAL ;
    PORT
      LAYER met3 ;
      RECT 0.000 318.430 0.680 318.730 ;
    END
  END s_axis_cc_tdata[30]
  PIN s_axis_cc_tdata[31]
    DIRECTION INPUT ;
    USE SIGNAL ;
    PORT
      LAYER met3 ;
      RECT 0.000 319.790 0.680 320.090 ;
    END
  END s_axis_cc_tdata[31]
  PIN s_axis_cc_tdata[32]
    DIRECTION INPUT ;
    USE SIGNAL ;
    PORT
      LAYER met3 ;
      RECT 0.000 321.150 0.680 321.450 ;
    END
  END s_axis_cc_tdata[32]
  PIN s_axis_cc_tdata[33]
    DIRECTION INPUT ;
    USE SIGNAL ;
    PORT
      LAYER met3 ;
      RECT 0.000 322.510 0.680 322.810 ;
    END
  END s_axis_cc_tdata[33]
  PIN s_axis_cc_tdata[34]
    DIRECTION INPUT ;
    USE SIGNAL ;
    PORT
      LAYER met3 ;
      RECT 0.000 323.870 0.680 324.170 ;
    END
  END s_axis_cc_tdata[34]
  PIN s_axis_cc_tdata[35]
    DIRECTION INPUT ;
    USE SIGNAL ;
    PORT
      LAYER met3 ;
      RECT 0.000 325.230 0.680 325.530 ;
    END
  END s_axis_cc_tdata[35]
  PIN s_axis_cc_tdata[36]
    DIRECTION INPUT ;
    USE SIGNAL ;
    PORT
      LAYER met3 ;
      RECT 0.000 326.590 0.680 326.890 ;
    END
  END s_axis_cc_tdata[36]
  PIN s_axis_cc_tdata[37]
    DIRECTION INPUT ;
    USE SIGNAL ;
    PORT
      LAYER met3 ;
      RECT 0.000 327.950 0.680 328.250 ;
    END
  END s_axis_cc_tdata[37]
  PIN s_axis_cc_tdata[38]
    DIRECTION INPUT ;
    USE SIGNAL ;
    PORT
      LAYER met3 ;
      RECT 0.000 329.310 0.680 329.610 ;
    END
  END s_axis_cc_tdata[38]
  PIN s_axis_cc_tdata[39]
    DIRECTION INPUT ;
    USE SIGNAL ;
    PORT
      LAYER met3 ;
      RECT 0.000 330.670 0.680 330.970 ;
    END
  END s_axis_cc_tdata[39]
  PIN s_axis_cc_tdata[40]
    DIRECTION INPUT ;
    USE SIGNAL ;
    PORT
      LAYER met3 ;
      RECT 0.000 332.030 0.680 332.330 ;
    END
  END s_axis_cc_tdata[40]
  PIN s_axis_cc_tdata[41]
    DIRECTION INPUT ;
    USE SIGNAL ;
    PORT
      LAYER met3 ;
      RECT 0.000 333.390 0.680 333.690 ;
    END
  END s_axis_cc_tdata[41]
  PIN s_axis_cc_tdata[42]
    DIRECTION INPUT ;
    USE SIGNAL ;
    PORT
      LAYER met3 ;
      RECT 0.000 334.750 0.680 335.050 ;
    END
  END s_axis_cc_tdata[42]
  PIN s_axis_cc_tdata[43]
    DIRECTION INPUT ;
    USE SIGNAL ;
    PORT
      LAYER met3 ;
      RECT 0.000 336.110 0.680 336.410 ;
    END
  END s_axis_cc_tdata[43]
  PIN s_axis_cc_tdata[44]
    DIRECTION INPUT ;
    USE SIGNAL ;
    PORT
      LAYER met3 ;
      RECT 0.000 337.470 0.680 337.770 ;
    END
  END s_axis_cc_tdata[44]
  PIN s_axis_cc_tdata[45]
    DIRECTION INPUT ;
    USE SIGNAL ;
    PORT
      LAYER met3 ;
      RECT 0.000 338.830 0.680 339.130 ;
    END
  END s_axis_cc_tdata[45]
  PIN s_axis_cc_tdata[46]
    DIRECTION INPUT ;
    USE SIGNAL ;
    PORT
      LAYER met3 ;
      RECT 0.000 340.190 0.680 340.490 ;
    END
  END s_axis_cc_tdata[46]
  PIN s_axis_cc_tdata[47]
    DIRECTION INPUT ;
    USE SIGNAL ;
    PORT
      LAYER met3 ;
      RECT 0.000 341.550 0.680 341.850 ;
    END
  END s_axis_cc_tdata[47]
  PIN s_axis_cc_tdata[48]
    DIRECTION INPUT ;
    USE SIGNAL ;
    PORT
      LAYER met3 ;
      RECT 0.000 342.910 0.680 343.210 ;
    END
  END s_axis_cc_tdata[48]
  PIN s_axis_cc_tdata[49]
    DIRECTION INPUT ;
    USE SIGNAL ;
    PORT
      LAYER met3 ;
      RECT 0.000 344.270 0.680 344.570 ;
    END
  END s_axis_cc_tdata[49]
  PIN s_axis_cc_tdata[50]
    DIRECTION INPUT ;
    USE SIGNAL ;
    PORT
      LAYER met3 ;
      RECT 0.000 345.630 0.680 345.930 ;
    END
  END s_axis_cc_tdata[50]
  PIN s_axis_cc_tdata[51]
    DIRECTION INPUT ;
    USE SIGNAL ;
    PORT
      LAYER met3 ;
      RECT 0.000 346.990 0.680 347.290 ;
    END
  END s_axis_cc_tdata[51]
  PIN s_axis_cc_tdata[52]
    DIRECTION INPUT ;
    USE SIGNAL ;
    PORT
      LAYER met3 ;
      RECT 0.000 348.350 0.680 348.650 ;
    END
  END s_axis_cc_tdata[52]
  PIN s_axis_cc_tdata[53]
    DIRECTION INPUT ;
    USE SIGNAL ;
    PORT
      LAYER met3 ;
      RECT 0.000 349.710 0.680 350.010 ;
    END
  END s_axis_cc_tdata[53]
  PIN s_axis_cc_tdata[54]
    DIRECTION INPUT ;
    USE SIGNAL ;
    PORT
      LAYER met3 ;
      RECT 0.000 351.070 0.680 351.370 ;
    END
  END s_axis_cc_tdata[54]
  PIN s_axis_cc_tdata[55]
    DIRECTION INPUT ;
    USE SIGNAL ;
    PORT
      LAYER met3 ;
      RECT 0.000 352.430 0.680 352.730 ;
    END
  END s_axis_cc_tdata[55]
  PIN s_axis_cc_tdata[56]
    DIRECTION INPUT ;
    USE SIGNAL ;
    PORT
      LAYER met3 ;
      RECT 0.000 353.790 0.680 354.090 ;
    END
  END s_axis_cc_tdata[56]
  PIN s_axis_cc_tdata[57]
    DIRECTION INPUT ;
    USE SIGNAL ;
    PORT
      LAYER met3 ;
      RECT 0.000 355.150 0.680 355.450 ;
    END
  END s_axis_cc_tdata[57]
  PIN s_axis_cc_tdata[58]
    DIRECTION INPUT ;
    USE SIGNAL ;
    PORT
      LAYER met3 ;
      RECT 0.000 356.510 0.680 356.810 ;
    END
  END s_axis_cc_tdata[58]
  PIN s_axis_cc_tdata[59]
    DIRECTION INPUT ;
    USE SIGNAL ;
    PORT
      LAYER met3 ;
      RECT 0.000 357.870 0.680 358.170 ;
    END
  END s_axis_cc_tdata[59]
  PIN s_axis_cc_tdata[60]
    DIRECTION INPUT ;
    USE SIGNAL ;
    PORT
      LAYER met3 ;
      RECT 0.000 359.230 0.680 359.530 ;
    END
  END s_axis_cc_tdata[60]
  PIN s_axis_cc_tdata[61]
    DIRECTION INPUT ;
    USE SIGNAL ;
    PORT
      LAYER met3 ;
      RECT 0.000 360.590 0.680 360.890 ;
    END
  END s_axis_cc_tdata[61]
  PIN s_axis_cc_tdata[62]
    DIRECTION INPUT ;
    USE SIGNAL ;
    PORT
      LAYER met3 ;
      RECT 0.000 361.950 0.680 362.250 ;
    END
  END s_axis_cc_tdata[62]
  PIN s_axis_cc_tdata[63]
    DIRECTION INPUT ;
    USE SIGNAL ;
    PORT
      LAYER met3 ;
      RECT 0.000 363.310 0.680 363.610 ;
    END
  END s_axis_cc_tdata[63]
  PIN s_axis_cc_tdata[64]
    DIRECTION INPUT ;
    USE SIGNAL ;
    PORT
      LAYER met3 ;
      RECT 0.000 364.670 0.680 364.970 ;
    END
  END s_axis_cc_tdata[64]
  PIN s_axis_cc_tdata[65]
    DIRECTION INPUT ;
    USE SIGNAL ;
    PORT
      LAYER met3 ;
      RECT 0.000 366.030 0.680 366.330 ;
    END
  END s_axis_cc_tdata[65]
  PIN s_axis_cc_tdata[66]
    DIRECTION INPUT ;
    USE SIGNAL ;
    PORT
      LAYER met3 ;
      RECT 0.000 367.390 0.680 367.690 ;
    END
  END s_axis_cc_tdata[66]
  PIN s_axis_cc_tdata[67]
    DIRECTION INPUT ;
    USE SIGNAL ;
    PORT
      LAYER met3 ;
      RECT 0.000 368.750 0.680 369.050 ;
    END
  END s_axis_cc_tdata[67]
  PIN s_axis_cc_tdata[68]
    DIRECTION INPUT ;
    USE SIGNAL ;
    PORT
      LAYER met3 ;
      RECT 0.000 370.110 0.680 370.410 ;
    END
  END s_axis_cc_tdata[68]
  PIN s_axis_cc_tdata[69]
    DIRECTION INPUT ;
    USE SIGNAL ;
    PORT
      LAYER met3 ;
      RECT 0.000 371.470 0.680 371.770 ;
    END
  END s_axis_cc_tdata[69]
  PIN s_axis_cc_tdata[70]
    DIRECTION INPUT ;
    USE SIGNAL ;
    PORT
      LAYER met3 ;
      RECT 0.000 372.830 0.680 373.130 ;
    END
  END s_axis_cc_tdata[70]
  PIN s_axis_cc_tdata[71]
    DIRECTION INPUT ;
    USE SIGNAL ;
    PORT
      LAYER met3 ;
      RECT 0.000 374.190 0.680 374.490 ;
    END
  END s_axis_cc_tdata[71]
  PIN s_axis_cc_tdata[72]
    DIRECTION INPUT ;
    USE SIGNAL ;
    PORT
      LAYER met3 ;
      RECT 0.000 375.550 0.680 375.850 ;
    END
  END s_axis_cc_tdata[72]
  PIN s_axis_cc_tdata[73]
    DIRECTION INPUT ;
    USE SIGNAL ;
    PORT
      LAYER met3 ;
      RECT 0.000 376.910 0.680 377.210 ;
    END
  END s_axis_cc_tdata[73]
  PIN s_axis_cc_tdata[74]
    DIRECTION INPUT ;
    USE SIGNAL ;
    PORT
      LAYER met3 ;
      RECT 0.000 378.270 0.680 378.570 ;
    END
  END s_axis_cc_tdata[74]
  PIN s_axis_cc_tdata[75]
    DIRECTION INPUT ;
    USE SIGNAL ;
    PORT
      LAYER met3 ;
      RECT 0.000 379.630 0.680 379.930 ;
    END
  END s_axis_cc_tdata[75]
  PIN s_axis_cc_tdata[76]
    DIRECTION INPUT ;
    USE SIGNAL ;
    PORT
      LAYER met3 ;
      RECT 0.000 380.990 0.680 381.290 ;
    END
  END s_axis_cc_tdata[76]
  PIN s_axis_cc_tdata[77]
    DIRECTION INPUT ;
    USE SIGNAL ;
    PORT
      LAYER met3 ;
      RECT 0.000 382.350 0.680 382.650 ;
    END
  END s_axis_cc_tdata[77]
  PIN s_axis_cc_tdata[78]
    DIRECTION INPUT ;
    USE SIGNAL ;
    PORT
      LAYER met3 ;
      RECT 0.000 383.710 0.680 384.010 ;
    END
  END s_axis_cc_tdata[78]
  PIN s_axis_cc_tdata[79]
    DIRECTION INPUT ;
    USE SIGNAL ;
    PORT
      LAYER met3 ;
      RECT 0.000 385.070 0.680 385.370 ;
    END
  END s_axis_cc_tdata[79]
  PIN s_axis_cc_tdata[80]
    DIRECTION INPUT ;
    USE SIGNAL ;
    PORT
      LAYER met3 ;
      RECT 0.000 386.430 0.680 386.730 ;
    END
  END s_axis_cc_tdata[80]
  PIN s_axis_cc_tdata[81]
    DIRECTION INPUT ;
    USE SIGNAL ;
    PORT
      LAYER met3 ;
      RECT 0.000 387.790 0.680 388.090 ;
    END
  END s_axis_cc_tdata[81]
  PIN s_axis_cc_tdata[82]
    DIRECTION INPUT ;
    USE SIGNAL ;
    PORT
      LAYER met3 ;
      RECT 0.000 389.150 0.680 389.450 ;
    END
  END s_axis_cc_tdata[82]
  PIN s_axis_cc_tdata[83]
    DIRECTION INPUT ;
    USE SIGNAL ;
    PORT
      LAYER met3 ;
      RECT 0.000 390.510 0.680 390.810 ;
    END
  END s_axis_cc_tdata[83]
  PIN s_axis_cc_tdata[84]
    DIRECTION INPUT ;
    USE SIGNAL ;
    PORT
      LAYER met3 ;
      RECT 0.000 391.870 0.680 392.170 ;
    END
  END s_axis_cc_tdata[84]
  PIN s_axis_cc_tdata[85]
    DIRECTION INPUT ;
    USE SIGNAL ;
    PORT
      LAYER met3 ;
      RECT 0.000 393.230 0.680 393.530 ;
    END
  END s_axis_cc_tdata[85]
  PIN s_axis_cc_tdata[86]
    DIRECTION INPUT ;
    USE SIGNAL ;
    PORT
      LAYER met3 ;
      RECT 0.000 394.590 0.680 394.890 ;
    END
  END s_axis_cc_tdata[86]
  PIN s_axis_cc_tdata[87]
    DIRECTION INPUT ;
    USE SIGNAL ;
    PORT
      LAYER met3 ;
      RECT 0.000 395.950 0.680 396.250 ;
    END
  END s_axis_cc_tdata[87]
  PIN s_axis_cc_tdata[88]
    DIRECTION INPUT ;
    USE SIGNAL ;
    PORT
      LAYER met3 ;
      RECT 0.000 397.310 0.680 397.610 ;
    END
  END s_axis_cc_tdata[88]
  PIN s_axis_cc_tdata[89]
    DIRECTION INPUT ;
    USE SIGNAL ;
    PORT
      LAYER met3 ;
      RECT 0.000 398.670 0.680 398.970 ;
    END
  END s_axis_cc_tdata[89]
  PIN s_axis_cc_tdata[90]
    DIRECTION INPUT ;
    USE SIGNAL ;
    PORT
      LAYER met3 ;
      RECT 0.000 400.030 0.680 400.330 ;
    END
  END s_axis_cc_tdata[90]
  PIN s_axis_cc_tdata[91]
    DIRECTION INPUT ;
    USE SIGNAL ;
    PORT
      LAYER met3 ;
      RECT 0.000 401.390 0.680 401.690 ;
    END
  END s_axis_cc_tdata[91]
  PIN s_axis_cc_tdata[92]
    DIRECTION INPUT ;
    USE SIGNAL ;
    PORT
      LAYER met3 ;
      RECT 0.000 402.750 0.680 403.050 ;
    END
  END s_axis_cc_tdata[92]
  PIN s_axis_cc_tdata[93]
    DIRECTION INPUT ;
    USE SIGNAL ;
    PORT
      LAYER met3 ;
      RECT 0.000 404.110 0.680 404.410 ;
    END
  END s_axis_cc_tdata[93]
  PIN s_axis_cc_tdata[94]
    DIRECTION INPUT ;
    USE SIGNAL ;
    PORT
      LAYER met3 ;
      RECT 0.000 405.470 0.680 405.770 ;
    END
  END s_axis_cc_tdata[94]
  PIN s_axis_cc_tdata[95]
    DIRECTION INPUT ;
    USE SIGNAL ;
    PORT
      LAYER met3 ;
      RECT 0.000 406.830 0.680 407.130 ;
    END
  END s_axis_cc_tdata[95]
  PIN s_axis_cc_tdata[96]
    DIRECTION INPUT ;
    USE SIGNAL ;
    PORT
      LAYER met3 ;
      RECT 0.000 408.190 0.680 408.490 ;
    END
  END s_axis_cc_tdata[96]
  PIN s_axis_cc_tdata[97]
    DIRECTION INPUT ;
    USE SIGNAL ;
    PORT
      LAYER met3 ;
      RECT 0.000 409.550 0.680 409.850 ;
    END
  END s_axis_cc_tdata[97]
  PIN s_axis_cc_tdata[98]
    DIRECTION INPUT ;
    USE SIGNAL ;
    PORT
      LAYER met3 ;
      RECT 0.000 410.910 0.680 411.210 ;
    END
  END s_axis_cc_tdata[98]
  PIN s_axis_cc_tdata[99]
    DIRECTION INPUT ;
    USE SIGNAL ;
    PORT
      LAYER met3 ;
      RECT 0.000 412.270 0.680 412.570 ;
    END
  END s_axis_cc_tdata[99]
  PIN s_axis_cc_tdata[100]
    DIRECTION INPUT ;
    USE SIGNAL ;
    PORT
      LAYER met3 ;
      RECT 0.000 413.630 0.680 413.930 ;
    END
  END s_axis_cc_tdata[100]
  PIN s_axis_cc_tdata[101]
    DIRECTION INPUT ;
    USE SIGNAL ;
    PORT
      LAYER met3 ;
      RECT 0.000 414.990 0.680 415.290 ;
    END
  END s_axis_cc_tdata[101]
  PIN s_axis_cc_tdata[102]
    DIRECTION INPUT ;
    USE SIGNAL ;
    PORT
      LAYER met3 ;
      RECT 0.000 416.350 0.680 416.650 ;
    END
  END s_axis_cc_tdata[102]
  PIN s_axis_cc_tdata[103]
    DIRECTION INPUT ;
    USE SIGNAL ;
    PORT
      LAYER met3 ;
      RECT 0.000 417.710 0.680 418.010 ;
    END
  END s_axis_cc_tdata[103]
  PIN s_axis_cc_tdata[104]
    DIRECTION INPUT ;
    USE SIGNAL ;
    PORT
      LAYER met3 ;
      RECT 0.000 419.070 0.680 419.370 ;
    END
  END s_axis_cc_tdata[104]
  PIN s_axis_cc_tdata[105]
    DIRECTION INPUT ;
    USE SIGNAL ;
    PORT
      LAYER met3 ;
      RECT 0.000 420.430 0.680 420.730 ;
    END
  END s_axis_cc_tdata[105]
  PIN s_axis_cc_tdata[106]
    DIRECTION INPUT ;
    USE SIGNAL ;
    PORT
      LAYER met3 ;
      RECT 0.000 421.790 0.680 422.090 ;
    END
  END s_axis_cc_tdata[106]
  PIN s_axis_cc_tdata[107]
    DIRECTION INPUT ;
    USE SIGNAL ;
    PORT
      LAYER met3 ;
      RECT 0.000 423.150 0.680 423.450 ;
    END
  END s_axis_cc_tdata[107]
  PIN s_axis_cc_tdata[108]
    DIRECTION INPUT ;
    USE SIGNAL ;
    PORT
      LAYER met3 ;
      RECT 0.000 424.510 0.680 424.810 ;
    END
  END s_axis_cc_tdata[108]
  PIN s_axis_cc_tdata[109]
    DIRECTION INPUT ;
    USE SIGNAL ;
    PORT
      LAYER met3 ;
      RECT 0.000 425.870 0.680 426.170 ;
    END
  END s_axis_cc_tdata[109]
  PIN s_axis_cc_tdata[110]
    DIRECTION INPUT ;
    USE SIGNAL ;
    PORT
      LAYER met3 ;
      RECT 0.000 427.230 0.680 427.530 ;
    END
  END s_axis_cc_tdata[110]
  PIN s_axis_cc_tdata[111]
    DIRECTION INPUT ;
    USE SIGNAL ;
    PORT
      LAYER met3 ;
      RECT 0.000 428.590 0.680 428.890 ;
    END
  END s_axis_cc_tdata[111]
  PIN s_axis_cc_tdata[112]
    DIRECTION INPUT ;
    USE SIGNAL ;
    PORT
      LAYER met3 ;
      RECT 0.000 429.950 0.680 430.250 ;
    END
  END s_axis_cc_tdata[112]
  PIN s_axis_cc_tdata[113]
    DIRECTION INPUT ;
    USE SIGNAL ;
    PORT
      LAYER met3 ;
      RECT 0.000 431.310 0.680 431.610 ;
    END
  END s_axis_cc_tdata[113]
  PIN s_axis_cc_tdata[114]
    DIRECTION INPUT ;
    USE SIGNAL ;
    PORT
      LAYER met3 ;
      RECT 0.000 432.670 0.680 432.970 ;
    END
  END s_axis_cc_tdata[114]
  PIN s_axis_cc_tdata[115]
    DIRECTION INPUT ;
    USE SIGNAL ;
    PORT
      LAYER met3 ;
      RECT 0.000 434.030 0.680 434.330 ;
    END
  END s_axis_cc_tdata[115]
  PIN s_axis_cc_tdata[116]
    DIRECTION INPUT ;
    USE SIGNAL ;
    PORT
      LAYER met3 ;
      RECT 0.000 435.390 0.680 435.690 ;
    END
  END s_axis_cc_tdata[116]
  PIN s_axis_cc_tdata[117]
    DIRECTION INPUT ;
    USE SIGNAL ;
    PORT
      LAYER met3 ;
      RECT 0.000 436.750 0.680 437.050 ;
    END
  END s_axis_cc_tdata[117]
  PIN s_axis_cc_tdata[118]
    DIRECTION INPUT ;
    USE SIGNAL ;
    PORT
      LAYER met3 ;
      RECT 0.000 438.110 0.680 438.410 ;
    END
  END s_axis_cc_tdata[118]
  PIN s_axis_cc_tdata[119]
    DIRECTION INPUT ;
    USE SIGNAL ;
    PORT
      LAYER met3 ;
      RECT 0.000 439.470 0.680 439.770 ;
    END
  END s_axis_cc_tdata[119]
  PIN s_axis_cc_tdata[120]
    DIRECTION INPUT ;
    USE SIGNAL ;
    PORT
      LAYER met3 ;
      RECT 0.000 440.830 0.680 441.130 ;
    END
  END s_axis_cc_tdata[120]
  PIN s_axis_cc_tdata[121]
    DIRECTION INPUT ;
    USE SIGNAL ;
    PORT
      LAYER met3 ;
      RECT 0.000 442.190 0.680 442.490 ;
    END
  END s_axis_cc_tdata[121]
  PIN s_axis_cc_tdata[122]
    DIRECTION INPUT ;
    USE SIGNAL ;
    PORT
      LAYER met3 ;
      RECT 0.000 443.550 0.680 443.850 ;
    END
  END s_axis_cc_tdata[122]
  PIN s_axis_cc_tdata[123]
    DIRECTION INPUT ;
    USE SIGNAL ;
    PORT
      LAYER met3 ;
      RECT 0.000 444.910 0.680 445.210 ;
    END
  END s_axis_cc_tdata[123]
  PIN s_axis_cc_tdata[124]
    DIRECTION INPUT ;
    USE SIGNAL ;
    PORT
      LAYER met3 ;
      RECT 0.000 446.270 0.680 446.570 ;
    END
  END s_axis_cc_tdata[124]
  PIN s_axis_cc_tdata[125]
    DIRECTION INPUT ;
    USE SIGNAL ;
    PORT
      LAYER met3 ;
      RECT 0.000 447.630 0.680 447.930 ;
    END
  END s_axis_cc_tdata[125]
  PIN s_axis_cc_tdata[126]
    DIRECTION INPUT ;
    USE SIGNAL ;
    PORT
      LAYER met3 ;
      RECT 0.000 448.990 0.680 449.290 ;
    END
  END s_axis_cc_tdata[126]
  PIN s_axis_cc_tdata[127]
    DIRECTION INPUT ;
    USE SIGNAL ;
    PORT
      LAYER met3 ;
      RECT 0.000 450.350 0.680 450.650 ;
    END
  END s_axis_cc_tdata[127]
  PIN s_axis_cc_tkeep[0]
    DIRECTION INPUT ;
    USE SIGNAL ;
    PORT
      LAYER met3 ;
      RECT 0.000 451.710 0.680 452.010 ;
    END
  END s_axis_cc_tkeep[0]
  PIN s_axis_cc_tkeep[1]
    DIRECTION INPUT ;
    USE SIGNAL ;
    PORT
      LAYER met3 ;
      RECT 0.000 453.070 0.680 453.370 ;
    END
  END s_axis_cc_tkeep[1]
  PIN s_axis_cc_tkeep[2]
    DIRECTION INPUT ;
    USE SIGNAL ;
    PORT
      LAYER met3 ;
      RECT 0.000 454.430 0.680 454.730 ;
    END
  END s_axis_cc_tkeep[2]
  PIN s_axis_cc_tkeep[3]
    DIRECTION INPUT ;
    USE SIGNAL ;
    PORT
      LAYER met3 ;
      RECT 0.000 455.790 0.680 456.090 ;
    END
  END s_axis_cc_tkeep[3]
  PIN s_axis_cc_tlast
    DIRECTION INPUT ;
    USE SIGNAL ;
    PORT
      LAYER met3 ;
      RECT 0.000 457.150 0.680 457.450 ;
    END
  END s_axis_cc_tlast
  PIN s_axis_cc_tuser[0]
    DIRECTION INPUT ;
    USE SIGNAL ;
    PORT
      LAYER met3 ;
      RECT 0.000 458.510 0.680 458.810 ;
    END
  END s_axis_cc_tuser[0]
  PIN s_axis_cc_tuser[1]
    DIRECTION INPUT ;
    USE SIGNAL ;
    PORT
      LAYER met3 ;
      RECT 0.000 459.870 0.680 460.170 ;
    END
  END s_axis_cc_tuser[1]
  PIN s_axis_cc_tuser[2]
    DIRECTION INPUT ;
    USE SIGNAL ;
    PORT
      LAYER met3 ;
      RECT 0.000 461.230 0.680 461.530 ;
    END
  END s_axis_cc_tuser[2]
  PIN s_axis_cc_tuser[3]
    DIRECTION INPUT ;
    USE SIGNAL ;
    PORT
      LAYER met3 ;
      RECT 0.000 462.590 0.680 462.890 ;
    END
  END s_axis_cc_tuser[3]
  PIN s_axis_cc_tuser[4]
    DIRECTION INPUT ;
    USE SIGNAL ;
    PORT
      LAYER met3 ;
      RECT 0.000 463.950 0.680 464.250 ;
    END
  END s_axis_cc_tuser[4]
  PIN s_axis_cc_tuser[5]
    DIRECTION INPUT ;
    USE SIGNAL ;
    PORT
      LAYER met3 ;
      RECT 0.000 465.310 0.680 465.610 ;
    END
  END s_axis_cc_tuser[5]
  PIN s_axis_cc_tuser[6]
    DIRECTION INPUT ;
    USE SIGNAL ;
    PORT
      LAYER met3 ;
      RECT 0.000 466.670 0.680 466.970 ;
    END
  END s_axis_cc_tuser[6]
  PIN s_axis_cc_tuser[7]
    DIRECTION INPUT ;
    USE SIGNAL ;
    PORT
      LAYER met3 ;
      RECT 0.000 468.030 0.680 468.330 ;
    END
  END s_axis_cc_tuser[7]
  PIN s_axis_cc_tuser[8]
    DIRECTION INPUT ;
    USE SIGNAL ;
    PORT
      LAYER met3 ;
      RECT 0.000 469.390 0.680 469.690 ;
    END
  END s_axis_cc_tuser[8]
  PIN s_axis_cc_tuser[9]
    DIRECTION INPUT ;
    USE SIGNAL ;
    PORT
      LAYER met3 ;
      RECT 0.000 470.750 0.680 471.050 ;
    END
  END s_axis_cc_tuser[9]
  PIN s_axis_cc_tuser[10]
    DIRECTION INPUT ;
    USE SIGNAL ;
    PORT
      LAYER met3 ;
      RECT 0.000 472.110 0.680 472.410 ;
    END
  END s_axis_cc_tuser[10]
  PIN s_axis_cc_tuser[11]
    DIRECTION INPUT ;
    USE SIGNAL ;
    PORT
      LAYER met3 ;
      RECT 0.000 473.470 0.680 473.770 ;
    END
  END s_axis_cc_tuser[11]
  PIN s_axis_cc_tuser[12]
    DIRECTION INPUT ;
    USE SIGNAL ;
    PORT
      LAYER met3 ;
      RECT 0.000 474.830 0.680 475.130 ;
    END
  END s_axis_cc_tuser[12]
  PIN s_axis_cc_tuser[13]
    DIRECTION INPUT ;
    USE SIGNAL ;
    PORT
      LAYER met3 ;
      RECT 0.000 476.190 0.680 476.490 ;
    END
  END s_axis_cc_tuser[13]
  PIN s_axis_cc_tuser[14]
    DIRECTION INPUT ;
    USE SIGNAL ;
    PORT
      LAYER met3 ;
      RECT 0.000 477.550 0.680 477.850 ;
    END
  END s_axis_cc_tuser[14]
  PIN s_axis_cc_tuser[15]
    DIRECTION INPUT ;
    USE SIGNAL ;
    PORT
      LAYER met3 ;
      RECT 0.000 478.910 0.680 479.210 ;
    END
  END s_axis_cc_tuser[15]
  PIN s_axis_cc_tuser[16]
    DIRECTION INPUT ;
    USE SIGNAL ;
    PORT
      LAYER met3 ;
      RECT 0.000 480.270 0.680 480.570 ;
    END
  END s_axis_cc_tuser[16]
  PIN s_axis_cc_tuser[17]
    DIRECTION INPUT ;
    USE SIGNAL ;
    PORT
      LAYER met3 ;
      RECT 0.000 481.630 0.680 481.930 ;
    END
  END s_axis_cc_tuser[17]
  PIN s_axis_cc_tuser[18]
    DIRECTION INPUT ;
    USE SIGNAL ;
    PORT
      LAYER met3 ;
      RECT 0.000 482.990 0.680 483.290 ;
    END
  END s_axis_cc_tuser[18]
  PIN s_axis_cc_tuser[19]
    DIRECTION INPUT ;
    USE SIGNAL ;
    PORT
      LAYER met3 ;
      RECT 0.000 484.350 0.680 484.650 ;
    END
  END s_axis_cc_tuser[19]
  PIN s_axis_cc_tuser[20]
    DIRECTION INPUT ;
    USE SIGNAL ;
    PORT
      LAYER met3 ;
      RECT 0.000 485.710 0.680 486.010 ;
    END
  END s_axis_cc_tuser[20]
  PIN s_axis_cc_tuser[21]
    DIRECTION INPUT ;
    USE SIGNAL ;
    PORT
      LAYER met3 ;
      RECT 0.000 487.070 0.680 487.370 ;
    END
  END s_axis_cc_tuser[21]
  PIN s_axis_cc_tuser[22]
    DIRECTION INPUT ;
    USE SIGNAL ;
    PORT
      LAYER met3 ;
      RECT 0.000 488.430 0.680 488.730 ;
    END
  END s_axis_cc_tuser[22]
  PIN s_axis_cc_tuser[23]
    DIRECTION INPUT ;
    USE SIGNAL ;
    PORT
      LAYER met3 ;
      RECT 0.000 489.790 0.680 490.090 ;
    END
  END s_axis_cc_tuser[23]
  PIN s_axis_cc_tuser[24]
    DIRECTION INPUT ;
    USE SIGNAL ;
    PORT
      LAYER met3 ;
      RECT 0.000 491.150 0.680 491.450 ;
    END
  END s_axis_cc_tuser[24]
  PIN s_axis_cc_tuser[25]
    DIRECTION INPUT ;
    USE SIGNAL ;
    PORT
      LAYER met3 ;
      RECT 0.000 492.510 0.680 492.810 ;
    END
  END s_axis_cc_tuser[25]
  PIN s_axis_cc_tuser[26]
    DIRECTION INPUT ;
    USE SIGNAL ;
    PORT
      LAYER met3 ;
      RECT 0.000 493.870 0.680 494.170 ;
    END
  END s_axis_cc_tuser[26]
  PIN s_axis_cc_tuser[27]
    DIRECTION INPUT ;
    USE SIGNAL ;
    PORT
      LAYER met3 ;
      RECT 0.000 495.230 0.680 495.530 ;
    END
  END s_axis_cc_tuser[27]
  PIN s_axis_cc_tuser[28]
    DIRECTION INPUT ;
    USE SIGNAL ;
    PORT
      LAYER met3 ;
      RECT 0.000 496.590 0.680 496.890 ;
    END
  END s_axis_cc_tuser[28]
  PIN s_axis_cc_tuser[29]
    DIRECTION INPUT ;
    USE SIGNAL ;
    PORT
      LAYER met3 ;
      RECT 0.000 497.950 0.680 498.250 ;
    END
  END s_axis_cc_tuser[29]
  PIN s_axis_cc_tuser[30]
    DIRECTION INPUT ;
    USE SIGNAL ;
    PORT
      LAYER met3 ;
      RECT 0.000 499.310 0.680 499.610 ;
    END
  END s_axis_cc_tuser[30]
  PIN s_axis_cc_tuser[31]
    DIRECTION INPUT ;
    USE SIGNAL ;
    PORT
      LAYER met3 ;
      RECT 0.000 500.670 0.680 500.970 ;
    END
  END s_axis_cc_tuser[31]
  PIN s_axis_cc_tuser[32]
    DIRECTION INPUT ;
    USE SIGNAL ;
    PORT
      LAYER met3 ;
      RECT 0.000 502.030 0.680 502.330 ;
    END
  END s_axis_cc_tuser[32]
  PIN s_axis_cc_tvalid
    DIRECTION INPUT ;
    USE SIGNAL ;
    PORT
      LAYER met3 ;
      RECT 0.000 503.390 0.680 503.690 ;
    END
  END s_axis_cc_tvalid
  PIN s_axis_rq_tdata[0]
    DIRECTION INPUT ;
    USE SIGNAL ;
    PORT
      LAYER met3 ;
      RECT 0.000 504.750 0.680 505.050 ;
    END
  END s_axis_rq_tdata[0]
  PIN s_axis_rq_tdata[1]
    DIRECTION INPUT ;
    USE SIGNAL ;
    PORT
      LAYER met3 ;
      RECT 0.000 506.110 0.680 506.410 ;
    END
  END s_axis_rq_tdata[1]
  PIN s_axis_rq_tdata[2]
    DIRECTION INPUT ;
    USE SIGNAL ;
    PORT
      LAYER met3 ;
      RECT 0.000 507.470 0.680 507.770 ;
    END
  END s_axis_rq_tdata[2]
  PIN s_axis_rq_tdata[3]
    DIRECTION INPUT ;
    USE SIGNAL ;
    PORT
      LAYER met3 ;
      RECT 0.000 508.830 0.680 509.130 ;
    END
  END s_axis_rq_tdata[3]
  PIN s_axis_rq_tdata[4]
    DIRECTION INPUT ;
    USE SIGNAL ;
    PORT
      LAYER met3 ;
      RECT 0.000 510.190 0.680 510.490 ;
    END
  END s_axis_rq_tdata[4]
  PIN s_axis_rq_tdata[5]
    DIRECTION INPUT ;
    USE SIGNAL ;
    PORT
      LAYER met3 ;
      RECT 0.000 511.550 0.680 511.850 ;
    END
  END s_axis_rq_tdata[5]
  PIN s_axis_rq_tdata[6]
    DIRECTION INPUT ;
    USE SIGNAL ;
    PORT
      LAYER met3 ;
      RECT 0.000 512.230 0.680 512.530 ;
    END
  END s_axis_rq_tdata[6]
  PIN s_axis_rq_tdata[7]
    DIRECTION INPUT ;
    USE SIGNAL ;
    PORT
      LAYER met3 ;
      RECT 0.000 514.270 0.680 514.570 ;
    END
  END s_axis_rq_tdata[7]
  PIN s_axis_rq_tdata[8]
    DIRECTION INPUT ;
    USE SIGNAL ;
    PORT
      LAYER met3 ;
      RECT 0.000 515.630 0.680 515.930 ;
    END
  END s_axis_rq_tdata[8]
  PIN s_axis_rq_tdata[9]
    DIRECTION INPUT ;
    USE SIGNAL ;
    PORT
      LAYER met3 ;
      RECT 0.000 516.990 0.680 517.290 ;
    END
  END s_axis_rq_tdata[9]
  PIN s_axis_rq_tdata[10]
    DIRECTION INPUT ;
    USE SIGNAL ;
    PORT
      LAYER met3 ;
      RECT 0.000 518.350 0.680 518.650 ;
    END
  END s_axis_rq_tdata[10]
  PIN s_axis_rq_tdata[11]
    DIRECTION INPUT ;
    USE SIGNAL ;
    PORT
      LAYER met3 ;
      RECT 0.000 519.710 0.680 520.010 ;
    END
  END s_axis_rq_tdata[11]
  PIN s_axis_rq_tdata[12]
    DIRECTION INPUT ;
    USE SIGNAL ;
    PORT
      LAYER met3 ;
      RECT 0.000 521.070 0.680 521.370 ;
    END
  END s_axis_rq_tdata[12]
  PIN s_axis_rq_tdata[13]
    DIRECTION INPUT ;
    USE SIGNAL ;
    PORT
      LAYER met3 ;
      RECT 0.000 521.750 0.680 522.050 ;
    END
  END s_axis_rq_tdata[13]
  PIN s_axis_rq_tdata[14]
    DIRECTION INPUT ;
    USE SIGNAL ;
    PORT
      LAYER met3 ;
      RECT 0.000 523.110 0.680 523.410 ;
    END
  END s_axis_rq_tdata[14]
  PIN s_axis_rq_tdata[15]
    DIRECTION INPUT ;
    USE SIGNAL ;
    PORT
      LAYER met3 ;
      RECT 0.000 525.150 0.680 525.450 ;
    END
  END s_axis_rq_tdata[15]
  PIN s_axis_rq_tdata[16]
    DIRECTION INPUT ;
    USE SIGNAL ;
    PORT
      LAYER met3 ;
      RECT 0.000 526.510 0.680 526.810 ;
    END
  END s_axis_rq_tdata[16]
  PIN s_axis_rq_tdata[17]
    DIRECTION INPUT ;
    USE SIGNAL ;
    PORT
      LAYER met3 ;
      RECT 0.000 527.870 0.680 528.170 ;
    END
  END s_axis_rq_tdata[17]
  PIN s_axis_rq_tdata[18]
    DIRECTION INPUT ;
    USE SIGNAL ;
    PORT
      LAYER met3 ;
      RECT 0.000 529.230 0.680 529.530 ;
    END
  END s_axis_rq_tdata[18]
  PIN s_axis_rq_tdata[19]
    DIRECTION INPUT ;
    USE SIGNAL ;
    PORT
      LAYER met3 ;
      RECT 0.000 530.590 0.680 530.890 ;
    END
  END s_axis_rq_tdata[19]
  PIN s_axis_rq_tdata[20]
    DIRECTION INPUT ;
    USE SIGNAL ;
    PORT
      LAYER met3 ;
      RECT 0.000 531.950 0.680 532.250 ;
    END
  END s_axis_rq_tdata[20]
  PIN s_axis_rq_tdata[21]
    DIRECTION INPUT ;
    USE SIGNAL ;
    PORT
      LAYER met3 ;
      RECT 0.000 533.310 0.680 533.610 ;
    END
  END s_axis_rq_tdata[21]
  PIN s_axis_rq_tdata[22]
    DIRECTION INPUT ;
    USE SIGNAL ;
    PORT
      LAYER met3 ;
      RECT 0.000 533.990 0.680 534.290 ;
    END
  END s_axis_rq_tdata[22]
  PIN s_axis_rq_tdata[23]
    DIRECTION INPUT ;
    USE SIGNAL ;
    PORT
      LAYER met3 ;
      RECT 0.000 536.030 0.680 536.330 ;
    END
  END s_axis_rq_tdata[23]
  PIN s_axis_rq_tdata[24]
    DIRECTION INPUT ;
    USE SIGNAL ;
    PORT
      LAYER met3 ;
      RECT 0.000 537.390 0.680 537.690 ;
    END
  END s_axis_rq_tdata[24]
  PIN s_axis_rq_tdata[25]
    DIRECTION INPUT ;
    USE SIGNAL ;
    PORT
      LAYER met3 ;
      RECT 0.000 538.750 0.680 539.050 ;
    END
  END s_axis_rq_tdata[25]
  PIN s_axis_rq_tdata[26]
    DIRECTION INPUT ;
    USE SIGNAL ;
    PORT
      LAYER met3 ;
      RECT 0.000 540.110 0.680 540.410 ;
    END
  END s_axis_rq_tdata[26]
  PIN s_axis_rq_tdata[27]
    DIRECTION INPUT ;
    USE SIGNAL ;
    PORT
      LAYER met3 ;
      RECT 0.000 541.470 0.680 541.770 ;
    END
  END s_axis_rq_tdata[27]
  PIN s_axis_rq_tdata[28]
    DIRECTION INPUT ;
    USE SIGNAL ;
    PORT
      LAYER met3 ;
      RECT 0.000 542.830 0.680 543.130 ;
    END
  END s_axis_rq_tdata[28]
  PIN s_axis_rq_tdata[29]
    DIRECTION INPUT ;
    USE SIGNAL ;
    PORT
      LAYER met3 ;
      RECT 0.000 544.190 0.680 544.490 ;
    END
  END s_axis_rq_tdata[29]
  PIN s_axis_rq_tdata[30]
    DIRECTION INPUT ;
    USE SIGNAL ;
    PORT
      LAYER met3 ;
      RECT 0.000 544.870 0.680 545.170 ;
    END
  END s_axis_rq_tdata[30]
  PIN s_axis_rq_tdata[31]
    DIRECTION INPUT ;
    USE SIGNAL ;
    PORT
      LAYER met3 ;
      RECT 0.000 546.230 0.680 546.530 ;
    END
  END s_axis_rq_tdata[31]
  PIN s_axis_rq_tdata[32]
    DIRECTION INPUT ;
    USE SIGNAL ;
    PORT
      LAYER met3 ;
      RECT 0.000 548.270 0.680 548.570 ;
    END
  END s_axis_rq_tdata[32]
  PIN s_axis_rq_tdata[33]
    DIRECTION INPUT ;
    USE SIGNAL ;
    PORT
      LAYER met3 ;
      RECT 0.000 549.630 0.680 549.930 ;
    END
  END s_axis_rq_tdata[33]
  PIN s_axis_rq_tdata[34]
    DIRECTION INPUT ;
    USE SIGNAL ;
    PORT
      LAYER met3 ;
      RECT 0.000 550.990 0.680 551.290 ;
    END
  END s_axis_rq_tdata[34]
  PIN s_axis_rq_tdata[35]
    DIRECTION INPUT ;
    USE SIGNAL ;
    PORT
      LAYER met3 ;
      RECT 0.000 552.350 0.680 552.650 ;
    END
  END s_axis_rq_tdata[35]
  PIN s_axis_rq_tdata[36]
    DIRECTION INPUT ;
    USE SIGNAL ;
    PORT
      LAYER met3 ;
      RECT 0.000 553.710 0.680 554.010 ;
    END
  END s_axis_rq_tdata[36]
  PIN s_axis_rq_tdata[37]
    DIRECTION INPUT ;
    USE SIGNAL ;
    PORT
      LAYER met3 ;
      RECT 0.000 555.070 0.680 555.370 ;
    END
  END s_axis_rq_tdata[37]
  PIN s_axis_rq_tdata[38]
    DIRECTION INPUT ;
    USE SIGNAL ;
    PORT
      LAYER met3 ;
      RECT 0.000 556.430 0.680 556.730 ;
    END
  END s_axis_rq_tdata[38]
  PIN s_axis_rq_tdata[39]
    DIRECTION INPUT ;
    USE SIGNAL ;
    PORT
      LAYER met3 ;
      RECT 0.000 557.110 0.680 557.410 ;
    END
  END s_axis_rq_tdata[39]
  PIN s_axis_rq_tdata[40]
    DIRECTION INPUT ;
    USE SIGNAL ;
    PORT
      LAYER met3 ;
      RECT 0.000 559.150 0.680 559.450 ;
    END
  END s_axis_rq_tdata[40]
  PIN s_axis_rq_tdata[41]
    DIRECTION INPUT ;
    USE SIGNAL ;
    PORT
      LAYER met3 ;
      RECT 0.000 560.510 0.680 560.810 ;
    END
  END s_axis_rq_tdata[41]
  PIN s_axis_rq_tdata[42]
    DIRECTION INPUT ;
    USE SIGNAL ;
    PORT
      LAYER met3 ;
      RECT 0.000 561.870 0.680 562.170 ;
    END
  END s_axis_rq_tdata[42]
  PIN s_axis_rq_tdata[43]
    DIRECTION INPUT ;
    USE SIGNAL ;
    PORT
      LAYER met3 ;
      RECT 0.000 563.230 0.680 563.530 ;
    END
  END s_axis_rq_tdata[43]
  PIN s_axis_rq_tdata[44]
    DIRECTION INPUT ;
    USE SIGNAL ;
    PORT
      LAYER met3 ;
      RECT 0.000 564.590 0.680 564.890 ;
    END
  END s_axis_rq_tdata[44]
  PIN s_axis_rq_tdata[45]
    DIRECTION INPUT ;
    USE SIGNAL ;
    PORT
      LAYER met3 ;
      RECT 0.000 565.950 0.680 566.250 ;
    END
  END s_axis_rq_tdata[45]
  PIN s_axis_rq_tdata[46]
    DIRECTION INPUT ;
    USE SIGNAL ;
    PORT
      LAYER met3 ;
      RECT 0.000 567.310 0.680 567.610 ;
    END
  END s_axis_rq_tdata[46]
  PIN s_axis_rq_tdata[47]
    DIRECTION INPUT ;
    USE SIGNAL ;
    PORT
      LAYER met3 ;
      RECT 0.000 567.990 0.680 568.290 ;
    END
  END s_axis_rq_tdata[47]
  PIN s_axis_rq_tdata[48]
    DIRECTION INPUT ;
    USE SIGNAL ;
    PORT
      LAYER met3 ;
      RECT 0.000 569.350 0.680 569.650 ;
    END
  END s_axis_rq_tdata[48]
  PIN s_axis_rq_tdata[49]
    DIRECTION INPUT ;
    USE SIGNAL ;
    PORT
      LAYER met3 ;
      RECT 0.000 571.390 0.680 571.690 ;
    END
  END s_axis_rq_tdata[49]
  PIN s_axis_rq_tdata[50]
    DIRECTION INPUT ;
    USE SIGNAL ;
    PORT
      LAYER met3 ;
      RECT 0.000 572.750 0.680 573.050 ;
    END
  END s_axis_rq_tdata[50]
  PIN s_axis_rq_tdata[51]
    DIRECTION INPUT ;
    USE SIGNAL ;
    PORT
      LAYER met3 ;
      RECT 0.000 574.110 0.680 574.410 ;
    END
  END s_axis_rq_tdata[51]
  PIN s_axis_rq_tdata[52]
    DIRECTION INPUT ;
    USE SIGNAL ;
    PORT
      LAYER met3 ;
      RECT 0.000 575.470 0.680 575.770 ;
    END
  END s_axis_rq_tdata[52]
  PIN s_axis_rq_tdata[53]
    DIRECTION INPUT ;
    USE SIGNAL ;
    PORT
      LAYER met3 ;
      RECT 0.000 576.830 0.680 577.130 ;
    END
  END s_axis_rq_tdata[53]
  PIN s_axis_rq_tdata[54]
    DIRECTION INPUT ;
    USE SIGNAL ;
    PORT
      LAYER met3 ;
      RECT 0.000 578.190 0.680 578.490 ;
    END
  END s_axis_rq_tdata[54]
  PIN s_axis_rq_tdata[55]
    DIRECTION INPUT ;
    USE SIGNAL ;
    PORT
      LAYER met3 ;
      RECT 0.000 578.870 0.680 579.170 ;
    END
  END s_axis_rq_tdata[55]
  PIN s_axis_rq_tdata[56]
    DIRECTION INPUT ;
    USE SIGNAL ;
    PORT
      LAYER met3 ;
      RECT 0.000 580.230 0.680 580.530 ;
    END
  END s_axis_rq_tdata[56]
  PIN s_axis_rq_tdata[57]
    DIRECTION INPUT ;
    USE SIGNAL ;
    PORT
      LAYER met3 ;
      RECT 0.000 582.270 0.680 582.570 ;
    END
  END s_axis_rq_tdata[57]
  PIN s_axis_rq_tdata[58]
    DIRECTION INPUT ;
    USE SIGNAL ;
    PORT
      LAYER met3 ;
      RECT 0.000 583.630 0.680 583.930 ;
    END
  END s_axis_rq_tdata[58]
  PIN s_axis_rq_tdata[59]
    DIRECTION INPUT ;
    USE SIGNAL ;
    PORT
      LAYER met3 ;
      RECT 0.000 584.990 0.680 585.290 ;
    END
  END s_axis_rq_tdata[59]
  PIN s_axis_rq_tdata[60]
    DIRECTION INPUT ;
    USE SIGNAL ;
    PORT
      LAYER met3 ;
      RECT 0.000 586.350 0.680 586.650 ;
    END
  END s_axis_rq_tdata[60]
  PIN s_axis_rq_tdata[61]
    DIRECTION INPUT ;
    USE SIGNAL ;
    PORT
      LAYER met3 ;
      RECT 0.000 587.710 0.680 588.010 ;
    END
  END s_axis_rq_tdata[61]
  PIN s_axis_rq_tdata[62]
    DIRECTION INPUT ;
    USE SIGNAL ;
    PORT
      LAYER met3 ;
      RECT 0.000 589.070 0.680 589.370 ;
    END
  END s_axis_rq_tdata[62]
  PIN s_axis_rq_tdata[63]
    DIRECTION INPUT ;
    USE SIGNAL ;
    PORT
      LAYER met3 ;
      RECT 0.000 590.430 0.680 590.730 ;
    END
  END s_axis_rq_tdata[63]
  PIN s_axis_rq_tdata[64]
    DIRECTION INPUT ;
    USE SIGNAL ;
    PORT
      LAYER met3 ;
      RECT 0.000 591.110 0.680 591.410 ;
    END
  END s_axis_rq_tdata[64]
  PIN s_axis_rq_tdata[65]
    DIRECTION INPUT ;
    USE SIGNAL ;
    PORT
      LAYER met3 ;
      RECT 0.000 593.150 0.680 593.450 ;
    END
  END s_axis_rq_tdata[65]
  PIN s_axis_rq_tdata[66]
    DIRECTION INPUT ;
    USE SIGNAL ;
    PORT
      LAYER met3 ;
      RECT 0.000 594.510 0.680 594.810 ;
    END
  END s_axis_rq_tdata[66]
  PIN s_axis_rq_tdata[67]
    DIRECTION INPUT ;
    USE SIGNAL ;
    PORT
      LAYER met3 ;
      RECT 0.000 595.870 0.680 596.170 ;
    END
  END s_axis_rq_tdata[67]
  PIN s_axis_rq_tdata[68]
    DIRECTION INPUT ;
    USE SIGNAL ;
    PORT
      LAYER met3 ;
      RECT 0.000 597.230 0.680 597.530 ;
    END
  END s_axis_rq_tdata[68]
  PIN s_axis_rq_tdata[69]
    DIRECTION INPUT ;
    USE SIGNAL ;
    PORT
      LAYER met3 ;
      RECT 0.000 598.590 0.680 598.890 ;
    END
  END s_axis_rq_tdata[69]
  PIN s_axis_rq_tdata[70]
    DIRECTION INPUT ;
    USE SIGNAL ;
    PORT
      LAYER met3 ;
      RECT 0.000 599.950 0.680 600.250 ;
    END
  END s_axis_rq_tdata[70]
  PIN s_axis_rq_tdata[71]
    DIRECTION INPUT ;
    USE SIGNAL ;
    PORT
      LAYER met3 ;
      RECT 0.000 601.310 0.680 601.610 ;
    END
  END s_axis_rq_tdata[71]
  PIN s_axis_rq_tdata[72]
    DIRECTION INPUT ;
    USE SIGNAL ;
    PORT
      LAYER met3 ;
      RECT 0.000 601.990 0.680 602.290 ;
    END
  END s_axis_rq_tdata[72]
  PIN s_axis_rq_tdata[73]
    DIRECTION INPUT ;
    USE SIGNAL ;
    PORT
      LAYER met3 ;
      RECT 0.000 603.350 0.680 603.650 ;
    END
  END s_axis_rq_tdata[73]
  PIN s_axis_rq_tdata[74]
    DIRECTION INPUT ;
    USE SIGNAL ;
    PORT
      LAYER met3 ;
      RECT 0.000 605.390 0.680 605.690 ;
    END
  END s_axis_rq_tdata[74]
  PIN s_axis_rq_tdata[75]
    DIRECTION INPUT ;
    USE SIGNAL ;
    PORT
      LAYER met3 ;
      RECT 0.000 606.750 0.680 607.050 ;
    END
  END s_axis_rq_tdata[75]
  PIN s_axis_rq_tdata[76]
    DIRECTION INPUT ;
    USE SIGNAL ;
    PORT
      LAYER met3 ;
      RECT 0.000 608.110 0.680 608.410 ;
    END
  END s_axis_rq_tdata[76]
  PIN s_axis_rq_tdata[77]
    DIRECTION INPUT ;
    USE SIGNAL ;
    PORT
      LAYER met3 ;
      RECT 0.000 609.470 0.680 609.770 ;
    END
  END s_axis_rq_tdata[77]
  PIN s_axis_rq_tdata[78]
    DIRECTION INPUT ;
    USE SIGNAL ;
    PORT
      LAYER met3 ;
      RECT 0.000 610.830 0.680 611.130 ;
    END
  END s_axis_rq_tdata[78]
  PIN s_axis_rq_tdata[79]
    DIRECTION INPUT ;
    USE SIGNAL ;
    PORT
      LAYER met3 ;
      RECT 0.000 612.190 0.680 612.490 ;
    END
  END s_axis_rq_tdata[79]
  PIN s_axis_rq_tdata[80]
    DIRECTION INPUT ;
    USE SIGNAL ;
    PORT
      LAYER met3 ;
      RECT 0.000 613.550 0.680 613.850 ;
    END
  END s_axis_rq_tdata[80]
  PIN s_axis_rq_tdata[81]
    DIRECTION INPUT ;
    USE SIGNAL ;
    PORT
      LAYER met3 ;
      RECT 0.000 614.230 0.680 614.530 ;
    END
  END s_axis_rq_tdata[81]
  PIN s_axis_rq_tdata[82]
    DIRECTION INPUT ;
    USE SIGNAL ;
    PORT
      LAYER met3 ;
      RECT 0.000 616.270 0.680 616.570 ;
    END
  END s_axis_rq_tdata[82]
  PIN s_axis_rq_tdata[83]
    DIRECTION INPUT ;
    USE SIGNAL ;
    PORT
      LAYER met3 ;
      RECT 0.000 617.630 0.680 617.930 ;
    END
  END s_axis_rq_tdata[83]
  PIN s_axis_rq_tdata[84]
    DIRECTION INPUT ;
    USE SIGNAL ;
    PORT
      LAYER met3 ;
      RECT 0.000 618.990 0.680 619.290 ;
    END
  END s_axis_rq_tdata[84]
  PIN s_axis_rq_tdata[85]
    DIRECTION INPUT ;
    USE SIGNAL ;
    PORT
      LAYER met3 ;
      RECT 0.000 620.350 0.680 620.650 ;
    END
  END s_axis_rq_tdata[85]
  PIN s_axis_rq_tdata[86]
    DIRECTION INPUT ;
    USE SIGNAL ;
    PORT
      LAYER met3 ;
      RECT 0.000 621.710 0.680 622.010 ;
    END
  END s_axis_rq_tdata[86]
  PIN s_axis_rq_tdata[87]
    DIRECTION INPUT ;
    USE SIGNAL ;
    PORT
      LAYER met3 ;
      RECT 0.000 623.070 0.680 623.370 ;
    END
  END s_axis_rq_tdata[87]
  PIN s_axis_rq_tdata[88]
    DIRECTION INPUT ;
    USE SIGNAL ;
    PORT
      LAYER met3 ;
      RECT 0.000 624.430 0.680 624.730 ;
    END
  END s_axis_rq_tdata[88]
  PIN s_axis_rq_tdata[89]
    DIRECTION INPUT ;
    USE SIGNAL ;
    PORT
      LAYER met3 ;
      RECT 0.000 625.110 0.680 625.410 ;
    END
  END s_axis_rq_tdata[89]
  PIN s_axis_rq_tdata[90]
    DIRECTION INPUT ;
    USE SIGNAL ;
    PORT
      LAYER met3 ;
      RECT 0.000 626.470 0.680 626.770 ;
    END
  END s_axis_rq_tdata[90]
  PIN s_axis_rq_tdata[91]
    DIRECTION INPUT ;
    USE SIGNAL ;
    PORT
      LAYER met3 ;
      RECT 0.000 628.510 0.680 628.810 ;
    END
  END s_axis_rq_tdata[91]
  PIN s_axis_rq_tdata[92]
    DIRECTION INPUT ;
    USE SIGNAL ;
    PORT
      LAYER met3 ;
      RECT 0.000 629.870 0.680 630.170 ;
    END
  END s_axis_rq_tdata[92]
  PIN s_axis_rq_tdata[93]
    DIRECTION INPUT ;
    USE SIGNAL ;
    PORT
      LAYER met3 ;
      RECT 0.000 631.230 0.680 631.530 ;
    END
  END s_axis_rq_tdata[93]
  PIN s_axis_rq_tdata[94]
    DIRECTION INPUT ;
    USE SIGNAL ;
    PORT
      LAYER met3 ;
      RECT 0.000 632.590 0.680 632.890 ;
    END
  END s_axis_rq_tdata[94]
  PIN s_axis_rq_tdata[95]
    DIRECTION INPUT ;
    USE SIGNAL ;
    PORT
      LAYER met3 ;
      RECT 0.000 633.950 0.680 634.250 ;
    END
  END s_axis_rq_tdata[95]
  PIN s_axis_rq_tdata[96]
    DIRECTION INPUT ;
    USE SIGNAL ;
    PORT
      LAYER met3 ;
      RECT 0.000 635.310 0.680 635.610 ;
    END
  END s_axis_rq_tdata[96]
  PIN s_axis_rq_tdata[97]
    DIRECTION INPUT ;
    USE SIGNAL ;
    PORT
      LAYER met3 ;
      RECT 0.000 635.990 0.680 636.290 ;
    END
  END s_axis_rq_tdata[97]
  PIN s_axis_rq_tdata[98]
    DIRECTION INPUT ;
    USE SIGNAL ;
    PORT
      LAYER met3 ;
      RECT 0.000 637.350 0.680 637.650 ;
    END
  END s_axis_rq_tdata[98]
  PIN s_axis_rq_tdata[99]
    DIRECTION INPUT ;
    USE SIGNAL ;
    PORT
      LAYER met3 ;
      RECT 0.000 639.390 0.680 639.690 ;
    END
  END s_axis_rq_tdata[99]
  PIN s_axis_rq_tdata[100]
    DIRECTION INPUT ;
    USE SIGNAL ;
    PORT
      LAYER met3 ;
      RECT 0.000 640.750 0.680 641.050 ;
    END
  END s_axis_rq_tdata[100]
  PIN s_axis_rq_tdata[101]
    DIRECTION INPUT ;
    USE SIGNAL ;
    PORT
      LAYER met3 ;
      RECT 0.000 642.110 0.680 642.410 ;
    END
  END s_axis_rq_tdata[101]
  PIN s_axis_rq_tdata[102]
    DIRECTION INPUT ;
    USE SIGNAL ;
    PORT
      LAYER met3 ;
      RECT 0.000 643.470 0.680 643.770 ;
    END
  END s_axis_rq_tdata[102]
  PIN s_axis_rq_tdata[103]
    DIRECTION INPUT ;
    USE SIGNAL ;
    PORT
      LAYER met3 ;
      RECT 0.000 644.830 0.680 645.130 ;
    END
  END s_axis_rq_tdata[103]
  PIN s_axis_rq_tdata[104]
    DIRECTION INPUT ;
    USE SIGNAL ;
    PORT
      LAYER met3 ;
      RECT 0.000 646.190 0.680 646.490 ;
    END
  END s_axis_rq_tdata[104]
  PIN s_axis_rq_tdata[105]
    DIRECTION INPUT ;
    USE SIGNAL ;
    PORT
      LAYER met3 ;
      RECT 0.000 647.550 0.680 647.850 ;
    END
  END s_axis_rq_tdata[105]
  PIN s_axis_rq_tdata[106]
    DIRECTION INPUT ;
    USE SIGNAL ;
    PORT
      LAYER met3 ;
      RECT 0.000 648.230 0.680 648.530 ;
    END
  END s_axis_rq_tdata[106]
  PIN s_axis_rq_tdata[107]
    DIRECTION INPUT ;
    USE SIGNAL ;
    PORT
      LAYER met3 ;
      RECT 0.000 650.270 0.680 650.570 ;
    END
  END s_axis_rq_tdata[107]
  PIN s_axis_rq_tdata[108]
    DIRECTION INPUT ;
    USE SIGNAL ;
    PORT
      LAYER met3 ;
      RECT 0.000 651.630 0.680 651.930 ;
    END
  END s_axis_rq_tdata[108]
  PIN s_axis_rq_tdata[109]
    DIRECTION INPUT ;
    USE SIGNAL ;
    PORT
      LAYER met3 ;
      RECT 0.000 652.990 0.680 653.290 ;
    END
  END s_axis_rq_tdata[109]
  PIN s_axis_rq_tdata[110]
    DIRECTION INPUT ;
    USE SIGNAL ;
    PORT
      LAYER met3 ;
      RECT 0.000 654.350 0.680 654.650 ;
    END
  END s_axis_rq_tdata[110]
  PIN s_axis_rq_tdata[111]
    DIRECTION INPUT ;
    USE SIGNAL ;
    PORT
      LAYER met3 ;
      RECT 0.000 655.710 0.680 656.010 ;
    END
  END s_axis_rq_tdata[111]
  PIN s_axis_rq_tdata[112]
    DIRECTION INPUT ;
    USE SIGNAL ;
    PORT
      LAYER met3 ;
      RECT 0.000 657.070 0.680 657.370 ;
    END
  END s_axis_rq_tdata[112]
  PIN s_axis_rq_tdata[113]
    DIRECTION INPUT ;
    USE SIGNAL ;
    PORT
      LAYER met3 ;
      RECT 0.000 658.430 0.680 658.730 ;
    END
  END s_axis_rq_tdata[113]
  PIN s_axis_rq_tdata[114]
    DIRECTION INPUT ;
    USE SIGNAL ;
    PORT
      LAYER met3 ;
      RECT 0.000 659.110 0.680 659.410 ;
    END
  END s_axis_rq_tdata[114]
  PIN s_axis_rq_tdata[115]
    DIRECTION INPUT ;
    USE SIGNAL ;
    PORT
      LAYER met3 ;
      RECT 0.000 660.470 0.680 660.770 ;
    END
  END s_axis_rq_tdata[115]
  PIN s_axis_rq_tdata[116]
    DIRECTION INPUT ;
    USE SIGNAL ;
    PORT
      LAYER met3 ;
      RECT 0.000 662.510 0.680 662.810 ;
    END
  END s_axis_rq_tdata[116]
  PIN s_axis_rq_tdata[117]
    DIRECTION INPUT ;
    USE SIGNAL ;
    PORT
      LAYER met3 ;
      RECT 0.000 663.870 0.680 664.170 ;
    END
  END s_axis_rq_tdata[117]
  PIN s_axis_rq_tdata[118]
    DIRECTION INPUT ;
    USE SIGNAL ;
    PORT
      LAYER met3 ;
      RECT 0.000 665.230 0.680 665.530 ;
    END
  END s_axis_rq_tdata[118]
  PIN s_axis_rq_tdata[119]
    DIRECTION INPUT ;
    USE SIGNAL ;
    PORT
      LAYER met3 ;
      RECT 0.000 666.590 0.680 666.890 ;
    END
  END s_axis_rq_tdata[119]
  PIN s_axis_rq_tdata[120]
    DIRECTION INPUT ;
    USE SIGNAL ;
    PORT
      LAYER met3 ;
      RECT 0.000 667.950 0.680 668.250 ;
    END
  END s_axis_rq_tdata[120]
  PIN s_axis_rq_tdata[121]
    DIRECTION INPUT ;
    USE SIGNAL ;
    PORT
      LAYER met3 ;
      RECT 0.000 669.310 0.680 669.610 ;
    END
  END s_axis_rq_tdata[121]
  PIN s_axis_rq_tdata[122]
    DIRECTION INPUT ;
    USE SIGNAL ;
    PORT
      LAYER met3 ;
      RECT 0.000 670.670 0.680 670.970 ;
    END
  END s_axis_rq_tdata[122]
  PIN s_axis_rq_tdata[123]
    DIRECTION INPUT ;
    USE SIGNAL ;
    PORT
      LAYER met3 ;
      RECT 0.000 671.350 0.680 671.650 ;
    END
  END s_axis_rq_tdata[123]
  PIN s_axis_rq_tdata[124]
    DIRECTION INPUT ;
    USE SIGNAL ;
    PORT
      LAYER met3 ;
      RECT 0.000 673.390 0.680 673.690 ;
    END
  END s_axis_rq_tdata[124]
  PIN s_axis_rq_tdata[125]
    DIRECTION INPUT ;
    USE SIGNAL ;
    PORT
      LAYER met3 ;
      RECT 0.000 674.750 0.680 675.050 ;
    END
  END s_axis_rq_tdata[125]
  PIN s_axis_rq_tdata[126]
    DIRECTION INPUT ;
    USE SIGNAL ;
    PORT
      LAYER met3 ;
      RECT 0.000 676.110 0.680 676.410 ;
    END
  END s_axis_rq_tdata[126]
  PIN s_axis_rq_tdata[127]
    DIRECTION INPUT ;
    USE SIGNAL ;
    PORT
      LAYER met3 ;
      RECT 0.000 677.470 0.680 677.770 ;
    END
  END s_axis_rq_tdata[127]
  PIN s_axis_rq_tkeep[0]
    DIRECTION INPUT ;
    USE SIGNAL ;
    PORT
      LAYER met3 ;
      RECT 0.000 678.830 0.680 679.130 ;
    END
  END s_axis_rq_tkeep[0]
  PIN s_axis_rq_tkeep[1]
    DIRECTION INPUT ;
    USE SIGNAL ;
    PORT
      LAYER met3 ;
      RECT 0.000 680.190 0.680 680.490 ;
    END
  END s_axis_rq_tkeep[1]
  PIN s_axis_rq_tkeep[2]
    DIRECTION INPUT ;
    USE SIGNAL ;
    PORT
      LAYER met3 ;
      RECT 0.000 681.550 0.680 681.850 ;
    END
  END s_axis_rq_tkeep[2]
  PIN s_axis_rq_tkeep[3]
    DIRECTION INPUT ;
    USE SIGNAL ;
    PORT
      LAYER met3 ;
      RECT 0.000 682.230 0.680 682.530 ;
    END
  END s_axis_rq_tkeep[3]
  PIN s_axis_rq_tlast
    DIRECTION INPUT ;
    USE SIGNAL ;
    PORT
      LAYER met3 ;
      RECT 0.000 683.590 0.680 683.890 ;
    END
  END s_axis_rq_tlast
  PIN s_axis_rq_tuser[0]
    DIRECTION INPUT ;
    USE SIGNAL ;
    PORT
      LAYER met3 ;
      RECT 0.000 685.630 0.680 685.930 ;
    END
  END s_axis_rq_tuser[0]
  PIN s_axis_rq_tuser[1]
    DIRECTION INPUT ;
    USE SIGNAL ;
    PORT
      LAYER met3 ;
      RECT 0.000 686.990 0.680 687.290 ;
    END
  END s_axis_rq_tuser[1]
  PIN s_axis_rq_tuser[2]
    DIRECTION INPUT ;
    USE SIGNAL ;
    PORT
      LAYER met3 ;
      RECT 0.000 688.350 0.680 688.650 ;
    END
  END s_axis_rq_tuser[2]
  PIN s_axis_rq_tuser[3]
    DIRECTION INPUT ;
    USE SIGNAL ;
    PORT
      LAYER met3 ;
      RECT 0.000 689.710 0.680 690.010 ;
    END
  END s_axis_rq_tuser[3]
  PIN s_axis_rq_tuser[4]
    DIRECTION INPUT ;
    USE SIGNAL ;
    PORT
      LAYER met3 ;
      RECT 0.000 691.070 0.680 691.370 ;
    END
  END s_axis_rq_tuser[4]
  PIN s_axis_rq_tuser[5]
    DIRECTION INPUT ;
    USE SIGNAL ;
    PORT
      LAYER met3 ;
      RECT 0.000 692.430 0.680 692.730 ;
    END
  END s_axis_rq_tuser[5]
  PIN s_axis_rq_tuser[6]
    DIRECTION INPUT ;
    USE SIGNAL ;
    PORT
      LAYER met3 ;
      RECT 0.000 693.110 0.680 693.410 ;
    END
  END s_axis_rq_tuser[6]
  PIN s_axis_rq_tuser[7]
    DIRECTION INPUT ;
    USE SIGNAL ;
    PORT
      LAYER met3 ;
      RECT 0.000 694.470 0.680 694.770 ;
    END
  END s_axis_rq_tuser[7]
  PIN s_axis_rq_tuser[8]
    DIRECTION INPUT ;
    USE SIGNAL ;
    PORT
      LAYER met3 ;
      RECT 0.000 696.510 0.680 696.810 ;
    END
  END s_axis_rq_tuser[8]
  PIN s_axis_rq_tuser[9]
    DIRECTION INPUT ;
    USE SIGNAL ;
    PORT
      LAYER met3 ;
      RECT 0.000 697.870 0.680 698.170 ;
    END
  END s_axis_rq_tuser[9]
  PIN s_axis_rq_tuser[10]
    DIRECTION INPUT ;
    USE SIGNAL ;
    PORT
      LAYER met3 ;
      RECT 0.000 699.230 0.680 699.530 ;
    END
  END s_axis_rq_tuser[10]
  PIN s_axis_rq_tuser[11]
    DIRECTION INPUT ;
    USE SIGNAL ;
    PORT
      LAYER met3 ;
      RECT 0.000 700.590 0.680 700.890 ;
    END
  END s_axis_rq_tuser[11]
  PIN s_axis_rq_tuser[12]
    DIRECTION INPUT ;
    USE SIGNAL ;
    PORT
      LAYER met3 ;
      RECT 0.000 701.950 0.680 702.250 ;
    END
  END s_axis_rq_tuser[12]
  PIN s_axis_rq_tuser[13]
    DIRECTION INPUT ;
    USE SIGNAL ;
    PORT
      LAYER met3 ;
      RECT 0.000 703.310 0.680 703.610 ;
    END
  END s_axis_rq_tuser[13]
  PIN s_axis_rq_tuser[14]
    DIRECTION INPUT ;
    USE SIGNAL ;
    PORT
      LAYER met3 ;
      RECT 0.000 704.670 0.680 704.970 ;
    END
  END s_axis_rq_tuser[14]
  PIN s_axis_rq_tuser[15]
    DIRECTION INPUT ;
    USE SIGNAL ;
    PORT
      LAYER met3 ;
      RECT 0.000 706.030 0.680 706.330 ;
    END
  END s_axis_rq_tuser[15]
  PIN s_axis_rq_tuser[16]
    DIRECTION INPUT ;
    USE SIGNAL ;
    PORT
      LAYER met3 ;
      RECT 0.000 707.390 0.680 707.690 ;
    END
  END s_axis_rq_tuser[16]
  PIN s_axis_rq_tuser[17]
    DIRECTION INPUT ;
    USE SIGNAL ;
    PORT
      LAYER met3 ;
      RECT 0.000 708.750 0.680 709.050 ;
    END
  END s_axis_rq_tuser[17]
  PIN s_axis_rq_tuser[18]
    DIRECTION INPUT ;
    USE SIGNAL ;
    PORT
      LAYER met3 ;
      RECT 0.000 710.110 0.680 710.410 ;
    END
  END s_axis_rq_tuser[18]
  PIN s_axis_rq_tuser[19]
    DIRECTION INPUT ;
    USE SIGNAL ;
    PORT
      LAYER met3 ;
      RECT 0.000 711.470 0.680 711.770 ;
    END
  END s_axis_rq_tuser[19]
  PIN s_axis_rq_tuser[20]
    DIRECTION INPUT ;
    USE SIGNAL ;
    PORT
      LAYER met3 ;
      RECT 0.000 712.830 0.680 713.130 ;
    END
  END s_axis_rq_tuser[20]
  PIN s_axis_rq_tuser[21]
    DIRECTION INPUT ;
    USE SIGNAL ;
    PORT
      LAYER met3 ;
      RECT 0.000 714.190 0.680 714.490 ;
    END
  END s_axis_rq_tuser[21]
  PIN s_axis_rq_tuser[22]
    DIRECTION INPUT ;
    USE SIGNAL ;
    PORT
      LAYER met3 ;
      RECT 0.000 715.550 0.680 715.850 ;
    END
  END s_axis_rq_tuser[22]
  PIN s_axis_rq_tuser[23]
    DIRECTION INPUT ;
    USE SIGNAL ;
    PORT
      LAYER met3 ;
      RECT 0.000 716.910 0.680 717.210 ;
    END
  END s_axis_rq_tuser[23]
  PIN s_axis_rq_tuser[24]
    DIRECTION INPUT ;
    USE SIGNAL ;
    PORT
      LAYER met3 ;
      RECT 0.000 718.270 0.680 718.570 ;
    END
  END s_axis_rq_tuser[24]
  PIN s_axis_rq_tuser[25]
    DIRECTION INPUT ;
    USE SIGNAL ;
    PORT
      LAYER met3 ;
      RECT 0.000 719.630 0.680 719.930 ;
    END
  END s_axis_rq_tuser[25]
  PIN s_axis_rq_tuser[26]
    DIRECTION INPUT ;
    USE SIGNAL ;
    PORT
      LAYER met3 ;
      RECT 0.000 720.990 0.680 721.290 ;
    END
  END s_axis_rq_tuser[26]
  PIN s_axis_rq_tuser[27]
    DIRECTION INPUT ;
    USE SIGNAL ;
    PORT
      LAYER met3 ;
      RECT 0.000 722.350 0.680 722.650 ;
    END
  END s_axis_rq_tuser[27]
  PIN s_axis_rq_tuser[28]
    DIRECTION INPUT ;
    USE SIGNAL ;
    PORT
      LAYER met3 ;
      RECT 0.000 723.710 0.680 724.010 ;
    END
  END s_axis_rq_tuser[28]
  PIN s_axis_rq_tuser[29]
    DIRECTION INPUT ;
    USE SIGNAL ;
    PORT
      LAYER met3 ;
      RECT 0.000 725.070 0.680 725.370 ;
    END
  END s_axis_rq_tuser[29]
  PIN s_axis_rq_tuser[30]
    DIRECTION INPUT ;
    USE SIGNAL ;
    PORT
      LAYER met3 ;
      RECT 0.000 726.430 0.680 726.730 ;
    END
  END s_axis_rq_tuser[30]
  PIN s_axis_rq_tuser[31]
    DIRECTION INPUT ;
    USE SIGNAL ;
    PORT
      LAYER met3 ;
      RECT 0.000 727.790 0.680 728.090 ;
    END
  END s_axis_rq_tuser[31]
  PIN s_axis_rq_tuser[32]
    DIRECTION INPUT ;
    USE SIGNAL ;
    PORT
      LAYER met3 ;
      RECT 0.000 729.150 0.680 729.450 ;
    END
  END s_axis_rq_tuser[32]
  PIN s_axis_rq_tuser[33]
    DIRECTION INPUT ;
    USE SIGNAL ;
    PORT
      LAYER met3 ;
      RECT 0.000 730.510 0.680 730.810 ;
    END
  END s_axis_rq_tuser[33]
  PIN s_axis_rq_tuser[34]
    DIRECTION INPUT ;
    USE SIGNAL ;
    PORT
      LAYER met3 ;
      RECT 0.000 731.870 0.680 732.170 ;
    END
  END s_axis_rq_tuser[34]
  PIN s_axis_rq_tuser[35]
    DIRECTION INPUT ;
    USE SIGNAL ;
    PORT
      LAYER met3 ;
      RECT 0.000 733.230 0.680 733.530 ;
    END
  END s_axis_rq_tuser[35]
  PIN s_axis_rq_tuser[36]
    DIRECTION INPUT ;
    USE SIGNAL ;
    PORT
      LAYER met3 ;
      RECT 0.000 734.590 0.680 734.890 ;
    END
  END s_axis_rq_tuser[36]
  PIN s_axis_rq_tuser[37]
    DIRECTION INPUT ;
    USE SIGNAL ;
    PORT
      LAYER met3 ;
      RECT 0.000 735.950 0.680 736.250 ;
    END
  END s_axis_rq_tuser[37]
  PIN s_axis_rq_tuser[38]
    DIRECTION INPUT ;
    USE SIGNAL ;
    PORT
      LAYER met3 ;
      RECT 0.000 737.310 0.680 737.610 ;
    END
  END s_axis_rq_tuser[38]
  PIN s_axis_rq_tuser[39]
    DIRECTION INPUT ;
    USE SIGNAL ;
    PORT
      LAYER met3 ;
      RECT 0.000 738.670 0.680 738.970 ;
    END
  END s_axis_rq_tuser[39]
  PIN s_axis_rq_tuser[40]
    DIRECTION INPUT ;
    USE SIGNAL ;
    PORT
      LAYER met3 ;
      RECT 0.000 740.030 0.680 740.330 ;
    END
  END s_axis_rq_tuser[40]
  PIN s_axis_rq_tuser[41]
    DIRECTION INPUT ;
    USE SIGNAL ;
    PORT
      LAYER met3 ;
      RECT 0.000 741.390 0.680 741.690 ;
    END
  END s_axis_rq_tuser[41]
  PIN s_axis_rq_tuser[42]
    DIRECTION INPUT ;
    USE SIGNAL ;
    PORT
      LAYER met3 ;
      RECT 0.000 742.750 0.680 743.050 ;
    END
  END s_axis_rq_tuser[42]
  PIN s_axis_rq_tuser[43]
    DIRECTION INPUT ;
    USE SIGNAL ;
    PORT
      LAYER met3 ;
      RECT 0.000 744.110 0.680 744.410 ;
    END
  END s_axis_rq_tuser[43]
  PIN s_axis_rq_tuser[44]
    DIRECTION INPUT ;
    USE SIGNAL ;
    PORT
      LAYER met3 ;
      RECT 0.000 745.470 0.680 745.770 ;
    END
  END s_axis_rq_tuser[44]
  PIN s_axis_rq_tuser[45]
    DIRECTION INPUT ;
    USE SIGNAL ;
    PORT
      LAYER met3 ;
      RECT 0.000 746.830 0.680 747.130 ;
    END
  END s_axis_rq_tuser[45]
  PIN s_axis_rq_tuser[46]
    DIRECTION INPUT ;
    USE SIGNAL ;
    PORT
      LAYER met3 ;
      RECT 0.000 748.190 0.680 748.490 ;
    END
  END s_axis_rq_tuser[46]
  PIN s_axis_rq_tuser[47]
    DIRECTION INPUT ;
    USE SIGNAL ;
    PORT
      LAYER met3 ;
      RECT 0.000 749.550 0.680 749.850 ;
    END
  END s_axis_rq_tuser[47]
  PIN s_axis_rq_tuser[48]
    DIRECTION INPUT ;
    USE SIGNAL ;
    PORT
      LAYER met3 ;
      RECT 0.000 750.910 0.680 751.210 ;
    END
  END s_axis_rq_tuser[48]
  PIN s_axis_rq_tuser[49]
    DIRECTION INPUT ;
    USE SIGNAL ;
    PORT
      LAYER met3 ;
      RECT 0.000 752.270 0.680 752.570 ;
    END
  END s_axis_rq_tuser[49]
  PIN s_axis_rq_tuser[50]
    DIRECTION INPUT ;
    USE SIGNAL ;
    PORT
      LAYER met3 ;
      RECT 0.000 753.630 0.680 753.930 ;
    END
  END s_axis_rq_tuser[50]
  PIN s_axis_rq_tuser[51]
    DIRECTION INPUT ;
    USE SIGNAL ;
    PORT
      LAYER met3 ;
      RECT 0.000 754.990 0.680 755.290 ;
    END
  END s_axis_rq_tuser[51]
  PIN s_axis_rq_tuser[52]
    DIRECTION INPUT ;
    USE SIGNAL ;
    PORT
      LAYER met3 ;
      RECT 0.000 756.350 0.680 756.650 ;
    END
  END s_axis_rq_tuser[52]
  PIN s_axis_rq_tuser[53]
    DIRECTION INPUT ;
    USE SIGNAL ;
    PORT
      LAYER met3 ;
      RECT 0.000 757.710 0.680 758.010 ;
    END
  END s_axis_rq_tuser[53]
  PIN s_axis_rq_tuser[54]
    DIRECTION INPUT ;
    USE SIGNAL ;
    PORT
      LAYER met3 ;
      RECT 0.000 759.070 0.680 759.370 ;
    END
  END s_axis_rq_tuser[54]
  PIN s_axis_rq_tuser[55]
    DIRECTION INPUT ;
    USE SIGNAL ;
    PORT
      LAYER met3 ;
      RECT 0.000 760.430 0.680 760.730 ;
    END
  END s_axis_rq_tuser[55]
  PIN s_axis_rq_tuser[56]
    DIRECTION INPUT ;
    USE SIGNAL ;
    PORT
      LAYER met3 ;
      RECT 0.000 761.790 0.680 762.090 ;
    END
  END s_axis_rq_tuser[56]
  PIN s_axis_rq_tuser[57]
    DIRECTION INPUT ;
    USE SIGNAL ;
    PORT
      LAYER met3 ;
      RECT 0.000 763.150 0.680 763.450 ;
    END
  END s_axis_rq_tuser[57]
  PIN s_axis_rq_tuser[58]
    DIRECTION INPUT ;
    USE SIGNAL ;
    PORT
      LAYER met3 ;
      RECT 0.000 764.510 0.680 764.810 ;
    END
  END s_axis_rq_tuser[58]
  PIN s_axis_rq_tuser[59]
    DIRECTION INPUT ;
    USE SIGNAL ;
    PORT
      LAYER met3 ;
      RECT 0.000 765.870 0.680 766.170 ;
    END
  END s_axis_rq_tuser[59]
  PIN s_axis_rq_tvalid
    DIRECTION INPUT ;
    USE SIGNAL ;
    PORT
      LAYER met3 ;
      RECT 0.000 767.230 0.680 767.530 ;
    END
  END s_axis_rq_tvalid
  PIN sys_clk
    DIRECTION INPUT ;
    USE SIGNAL ;
    PORT
      LAYER met3 ;
      RECT 0.000 768.590 0.680 768.890 ;
    END
  END sys_clk
  PIN sys_clk_gt
    DIRECTION INPUT ;
    USE SIGNAL ;
    PORT
      LAYER met3 ;
      RECT 0.000 769.950 0.680 770.250 ;
    END
  END sys_clk_gt
  PIN sys_reset
    DIRECTION INPUT ;
    USE SIGNAL ;
    PORT
      LAYER met3 ;
      RECT 0.000 771.310 0.680 771.610 ;
    END
  END sys_reset
  PIN cfg_current_speed[0]
    DIRECTION OUTPUT ;
    USE SIGNAL ;
    PORT
      LAYER met3 ;
      RECT 0.000 772.670 0.680 772.970 ;
    END
  END cfg_current_speed[0]
  PIN cfg_current_speed[1]
    DIRECTION OUTPUT ;
    USE SIGNAL ;
    PORT
      LAYER met3 ;
      RECT 0.000 774.030 0.680 774.330 ;
    END
  END cfg_current_speed[1]
  PIN cfg_current_speed[2]
    DIRECTION OUTPUT ;
    USE SIGNAL ;
    PORT
      LAYER met3 ;
      RECT 0.000 775.390 0.680 775.690 ;
    END
  END cfg_current_speed[2]
  PIN cfg_dpa_substate_change[0]
    DIRECTION OUTPUT ;
    USE SIGNAL ;
    PORT
      LAYER met3 ;
      RECT 0.000 776.750 0.680 777.050 ;
    END
  END cfg_dpa_substate_change[0]
  PIN cfg_dpa_substate_change[1]
    DIRECTION OUTPUT ;
    USE SIGNAL ;
    PORT
      LAYER met3 ;
      RECT 0.000 778.110 0.680 778.410 ;
    END
  END cfg_dpa_substate_change[1]
  PIN cfg_dpa_substate_change[2]
    DIRECTION OUTPUT ;
    USE SIGNAL ;
    PORT
      LAYER met3 ;
      RECT 0.000 779.470 0.680 779.770 ;
    END
  END cfg_dpa_substate_change[2]
  PIN cfg_dpa_substate_change[3]
    DIRECTION OUTPUT ;
    USE SIGNAL ;
    PORT
      LAYER met3 ;
      RECT 0.000 780.830 0.680 781.130 ;
    END
  END cfg_dpa_substate_change[3]
  PIN cfg_err_cor_out
    DIRECTION OUTPUT ;
    USE SIGNAL ;
    PORT
      LAYER met3 ;
      RECT 0.000 782.190 0.680 782.490 ;
    END
  END cfg_err_cor_out
  PIN cfg_err_fatal_out
    DIRECTION OUTPUT ;
    USE SIGNAL ;
    PORT
      LAYER met3 ;
      RECT 0.000 783.550 0.680 783.850 ;
    END
  END cfg_err_fatal_out
  PIN cfg_err_nonfatal_out
    DIRECTION OUTPUT ;
    USE SIGNAL ;
    PORT
      LAYER met3 ;
      RECT 0.000 784.910 0.680 785.210 ;
    END
  END cfg_err_nonfatal_out
  PIN cfg_fc_cpld[0]
    DIRECTION OUTPUT ;
    USE SIGNAL ;
    PORT
      LAYER met3 ;
      RECT 0.000 786.270 0.680 786.570 ;
    END
  END cfg_fc_cpld[0]
  PIN cfg_fc_cpld[1]
    DIRECTION OUTPUT ;
    USE SIGNAL ;
    PORT
      LAYER met3 ;
      RECT 0.000 787.630 0.680 787.930 ;
    END
  END cfg_fc_cpld[1]
  PIN cfg_fc_cpld[2]
    DIRECTION OUTPUT ;
    USE SIGNAL ;
    PORT
      LAYER met3 ;
      RECT 0.000 788.990 0.680 789.290 ;
    END
  END cfg_fc_cpld[2]
  PIN cfg_fc_cpld[3]
    DIRECTION OUTPUT ;
    USE SIGNAL ;
    PORT
      LAYER met3 ;
      RECT 0.000 790.350 0.680 790.650 ;
    END
  END cfg_fc_cpld[3]
  PIN cfg_fc_cpld[4]
    DIRECTION OUTPUT ;
    USE SIGNAL ;
    PORT
      LAYER met3 ;
      RECT 0.000 791.710 0.680 792.010 ;
    END
  END cfg_fc_cpld[4]
  PIN cfg_fc_cpld[5]
    DIRECTION OUTPUT ;
    USE SIGNAL ;
    PORT
      LAYER met3 ;
      RECT 0.000 793.070 0.680 793.370 ;
    END
  END cfg_fc_cpld[5]
  PIN cfg_fc_cpld[6]
    DIRECTION OUTPUT ;
    USE SIGNAL ;
    PORT
      LAYER met3 ;
      RECT 0.000 794.430 0.680 794.730 ;
    END
  END cfg_fc_cpld[6]
  PIN cfg_fc_cpld[7]
    DIRECTION OUTPUT ;
    USE SIGNAL ;
    PORT
      LAYER met3 ;
      RECT 0.000 795.790 0.680 796.090 ;
    END
  END cfg_fc_cpld[7]
  PIN cfg_fc_cpld[8]
    DIRECTION OUTPUT ;
    USE SIGNAL ;
    PORT
      LAYER met3 ;
      RECT 0.000 797.150 0.680 797.450 ;
    END
  END cfg_fc_cpld[8]
  PIN cfg_fc_cpld[9]
    DIRECTION OUTPUT ;
    USE SIGNAL ;
    PORT
      LAYER met3 ;
      RECT 0.000 798.510 0.680 798.810 ;
    END
  END cfg_fc_cpld[9]
  PIN cfg_fc_cpld[10]
    DIRECTION OUTPUT ;
    USE SIGNAL ;
    PORT
      LAYER met3 ;
      RECT 0.000 799.870 0.680 800.170 ;
    END
  END cfg_fc_cpld[10]
  PIN cfg_fc_cpld[11]
    DIRECTION OUTPUT ;
    USE SIGNAL ;
    PORT
      LAYER met3 ;
      RECT 0.000 801.230 0.680 801.530 ;
    END
  END cfg_fc_cpld[11]
  PIN cfg_fc_cplh[0]
    DIRECTION OUTPUT ;
    USE SIGNAL ;
    PORT
      LAYER met3 ;
      RECT 0.000 802.590 0.680 802.890 ;
    END
  END cfg_fc_cplh[0]
  PIN cfg_fc_cplh[1]
    DIRECTION OUTPUT ;
    USE SIGNAL ;
    PORT
      LAYER met3 ;
      RECT 0.000 803.950 0.680 804.250 ;
    END
  END cfg_fc_cplh[1]
  PIN cfg_fc_cplh[2]
    DIRECTION OUTPUT ;
    USE SIGNAL ;
    PORT
      LAYER met3 ;
      RECT 0.000 805.310 0.680 805.610 ;
    END
  END cfg_fc_cplh[2]
  PIN cfg_fc_cplh[3]
    DIRECTION OUTPUT ;
    USE SIGNAL ;
    PORT
      LAYER met3 ;
      RECT 0.000 806.670 0.680 806.970 ;
    END
  END cfg_fc_cplh[3]
  PIN cfg_fc_cplh[4]
    DIRECTION OUTPUT ;
    USE SIGNAL ;
    PORT
      LAYER met3 ;
      RECT 0.000 808.030 0.680 808.330 ;
    END
  END cfg_fc_cplh[4]
  PIN cfg_fc_cplh[5]
    DIRECTION OUTPUT ;
    USE SIGNAL ;
    PORT
      LAYER met3 ;
      RECT 0.000 809.390 0.680 809.690 ;
    END
  END cfg_fc_cplh[5]
  PIN cfg_fc_cplh[6]
    DIRECTION OUTPUT ;
    USE SIGNAL ;
    PORT
      LAYER met3 ;
      RECT 0.000 810.750 0.680 811.050 ;
    END
  END cfg_fc_cplh[6]
  PIN cfg_fc_cplh[7]
    DIRECTION OUTPUT ;
    USE SIGNAL ;
    PORT
      LAYER met3 ;
      RECT 0.000 812.110 0.680 812.410 ;
    END
  END cfg_fc_cplh[7]
  PIN cfg_fc_npd[0]
    DIRECTION OUTPUT ;
    USE SIGNAL ;
    PORT
      LAYER met3 ;
      RECT 0.000 813.470 0.680 813.770 ;
    END
  END cfg_fc_npd[0]
  PIN cfg_fc_npd[1]
    DIRECTION OUTPUT ;
    USE SIGNAL ;
    PORT
      LAYER met3 ;
      RECT 0.000 814.830 0.680 815.130 ;
    END
  END cfg_fc_npd[1]
  PIN cfg_fc_npd[2]
    DIRECTION OUTPUT ;
    USE SIGNAL ;
    PORT
      LAYER met3 ;
      RECT 0.000 816.190 0.680 816.490 ;
    END
  END cfg_fc_npd[2]
  PIN cfg_fc_npd[3]
    DIRECTION OUTPUT ;
    USE SIGNAL ;
    PORT
      LAYER met3 ;
      RECT 0.000 817.550 0.680 817.850 ;
    END
  END cfg_fc_npd[3]
  PIN cfg_fc_npd[4]
    DIRECTION OUTPUT ;
    USE SIGNAL ;
    PORT
      LAYER met3 ;
      RECT 0.000 818.910 0.680 819.210 ;
    END
  END cfg_fc_npd[4]
  PIN cfg_fc_npd[5]
    DIRECTION OUTPUT ;
    USE SIGNAL ;
    PORT
      LAYER met3 ;
      RECT 0.000 820.270 0.680 820.570 ;
    END
  END cfg_fc_npd[5]
  PIN cfg_fc_npd[6]
    DIRECTION OUTPUT ;
    USE SIGNAL ;
    PORT
      LAYER met3 ;
      RECT 0.000 821.630 0.680 821.930 ;
    END
  END cfg_fc_npd[6]
  PIN cfg_fc_npd[7]
    DIRECTION OUTPUT ;
    USE SIGNAL ;
    PORT
      LAYER met3 ;
      RECT 0.000 822.990 0.680 823.290 ;
    END
  END cfg_fc_npd[7]
  PIN cfg_fc_npd[8]
    DIRECTION OUTPUT ;
    USE SIGNAL ;
    PORT
      LAYER met3 ;
      RECT 0.000 824.350 0.680 824.650 ;
    END
  END cfg_fc_npd[8]
  PIN cfg_fc_npd[9]
    DIRECTION OUTPUT ;
    USE SIGNAL ;
    PORT
      LAYER met3 ;
      RECT 0.000 825.710 0.680 826.010 ;
    END
  END cfg_fc_npd[9]
  PIN cfg_fc_npd[10]
    DIRECTION OUTPUT ;
    USE SIGNAL ;
    PORT
      LAYER met3 ;
      RECT 0.000 827.070 0.680 827.370 ;
    END
  END cfg_fc_npd[10]
  PIN cfg_fc_npd[11]
    DIRECTION OUTPUT ;
    USE SIGNAL ;
    PORT
      LAYER met3 ;
      RECT 0.000 828.430 0.680 828.730 ;
    END
  END cfg_fc_npd[11]
  PIN cfg_fc_nph[0]
    DIRECTION OUTPUT ;
    USE SIGNAL ;
    PORT
      LAYER met3 ;
      RECT 0.000 829.790 0.680 830.090 ;
    END
  END cfg_fc_nph[0]
  PIN cfg_fc_nph[1]
    DIRECTION OUTPUT ;
    USE SIGNAL ;
    PORT
      LAYER met3 ;
      RECT 0.000 831.150 0.680 831.450 ;
    END
  END cfg_fc_nph[1]
  PIN cfg_fc_nph[2]
    DIRECTION OUTPUT ;
    USE SIGNAL ;
    PORT
      LAYER met3 ;
      RECT 0.000 832.510 0.680 832.810 ;
    END
  END cfg_fc_nph[2]
  PIN cfg_fc_nph[3]
    DIRECTION OUTPUT ;
    USE SIGNAL ;
    PORT
      LAYER met3 ;
      RECT 0.000 833.870 0.680 834.170 ;
    END
  END cfg_fc_nph[3]
  PIN cfg_fc_nph[4]
    DIRECTION OUTPUT ;
    USE SIGNAL ;
    PORT
      LAYER met3 ;
      RECT 0.000 835.230 0.680 835.530 ;
    END
  END cfg_fc_nph[4]
  PIN cfg_fc_nph[5]
    DIRECTION OUTPUT ;
    USE SIGNAL ;
    PORT
      LAYER met3 ;
      RECT 0.000 836.590 0.680 836.890 ;
    END
  END cfg_fc_nph[5]
  PIN cfg_fc_nph[6]
    DIRECTION OUTPUT ;
    USE SIGNAL ;
    PORT
      LAYER met3 ;
      RECT 0.000 837.950 0.680 838.250 ;
    END
  END cfg_fc_nph[6]
  PIN cfg_fc_nph[7]
    DIRECTION OUTPUT ;
    USE SIGNAL ;
    PORT
      LAYER met3 ;
      RECT 0.000 839.310 0.680 839.610 ;
    END
  END cfg_fc_nph[7]
  PIN cfg_fc_pd[0]
    DIRECTION OUTPUT ;
    USE SIGNAL ;
    PORT
      LAYER met3 ;
      RECT 0.000 840.670 0.680 840.970 ;
    END
  END cfg_fc_pd[0]
  PIN cfg_fc_pd[1]
    DIRECTION OUTPUT ;
    USE SIGNAL ;
    PORT
      LAYER met3 ;
      RECT 0.000 842.030 0.680 842.330 ;
    END
  END cfg_fc_pd[1]
  PIN cfg_fc_pd[2]
    DIRECTION OUTPUT ;
    USE SIGNAL ;
    PORT
      LAYER met3 ;
      RECT 0.000 843.390 0.680 843.690 ;
    END
  END cfg_fc_pd[2]
  PIN cfg_fc_pd[3]
    DIRECTION OUTPUT ;
    USE SIGNAL ;
    PORT
      LAYER met3 ;
      RECT 0.000 844.750 0.680 845.050 ;
    END
  END cfg_fc_pd[3]
  PIN cfg_fc_pd[4]
    DIRECTION OUTPUT ;
    USE SIGNAL ;
    PORT
      LAYER met3 ;
      RECT 0.000 846.110 0.680 846.410 ;
    END
  END cfg_fc_pd[4]
  PIN cfg_fc_pd[5]
    DIRECTION OUTPUT ;
    USE SIGNAL ;
    PORT
      LAYER met3 ;
      RECT 0.000 847.470 0.680 847.770 ;
    END
  END cfg_fc_pd[5]
  PIN cfg_fc_pd[6]
    DIRECTION OUTPUT ;
    USE SIGNAL ;
    PORT
      LAYER met3 ;
      RECT 0.000 848.830 0.680 849.130 ;
    END
  END cfg_fc_pd[6]
  PIN cfg_fc_pd[7]
    DIRECTION OUTPUT ;
    USE SIGNAL ;
    PORT
      LAYER met3 ;
      RECT 0.000 850.190 0.680 850.490 ;
    END
  END cfg_fc_pd[7]
  PIN cfg_fc_pd[8]
    DIRECTION OUTPUT ;
    USE SIGNAL ;
    PORT
      LAYER met3 ;
      RECT 0.000 851.550 0.680 851.850 ;
    END
  END cfg_fc_pd[8]
  PIN cfg_fc_pd[9]
    DIRECTION OUTPUT ;
    USE SIGNAL ;
    PORT
      LAYER met3 ;
      RECT 0.000 852.910 0.680 853.210 ;
    END
  END cfg_fc_pd[9]
  PIN cfg_fc_pd[10]
    DIRECTION OUTPUT ;
    USE SIGNAL ;
    PORT
      LAYER met3 ;
      RECT 0.000 854.270 0.680 854.570 ;
    END
  END cfg_fc_pd[10]
  PIN cfg_fc_pd[11]
    DIRECTION OUTPUT ;
    USE SIGNAL ;
    PORT
      LAYER met3 ;
      RECT 0.000 855.630 0.680 855.930 ;
    END
  END cfg_fc_pd[11]
  PIN cfg_fc_ph[0]
    DIRECTION OUTPUT ;
    USE SIGNAL ;
    PORT
      LAYER met3 ;
      RECT 0.000 856.990 0.680 857.290 ;
    END
  END cfg_fc_ph[0]
  PIN cfg_fc_ph[1]
    DIRECTION OUTPUT ;
    USE SIGNAL ;
    PORT
      LAYER met3 ;
      RECT 0.000 858.350 0.680 858.650 ;
    END
  END cfg_fc_ph[1]
  PIN cfg_fc_ph[2]
    DIRECTION OUTPUT ;
    USE SIGNAL ;
    PORT
      LAYER met3 ;
      RECT 0.000 859.710 0.680 860.010 ;
    END
  END cfg_fc_ph[2]
  PIN cfg_fc_ph[3]
    DIRECTION OUTPUT ;
    USE SIGNAL ;
    PORT
      LAYER met3 ;
      RECT 0.000 861.070 0.680 861.370 ;
    END
  END cfg_fc_ph[3]
  PIN cfg_fc_ph[4]
    DIRECTION OUTPUT ;
    USE SIGNAL ;
    PORT
      LAYER met3 ;
      RECT 0.000 862.430 0.680 862.730 ;
    END
  END cfg_fc_ph[4]
  PIN cfg_fc_ph[5]
    DIRECTION OUTPUT ;
    USE SIGNAL ;
    PORT
      LAYER met3 ;
      RECT 0.000 863.790 0.680 864.090 ;
    END
  END cfg_fc_ph[5]
  PIN cfg_fc_ph[6]
    DIRECTION OUTPUT ;
    USE SIGNAL ;
    PORT
      LAYER met3 ;
      RECT 0.000 865.150 0.680 865.450 ;
    END
  END cfg_fc_ph[6]
  PIN cfg_fc_ph[7]
    DIRECTION OUTPUT ;
    USE SIGNAL ;
    PORT
      LAYER met3 ;
      RECT 0.000 866.510 0.680 866.810 ;
    END
  END cfg_fc_ph[7]
  PIN cfg_flr_in_process[0]
    DIRECTION OUTPUT ;
    USE SIGNAL ;
    PORT
      LAYER met3 ;
      RECT 0.000 867.870 0.680 868.170 ;
    END
  END cfg_flr_in_process[0]
  PIN cfg_flr_in_process[1]
    DIRECTION OUTPUT ;
    USE SIGNAL ;
    PORT
      LAYER met3 ;
      RECT 0.000 869.230 0.680 869.530 ;
    END
  END cfg_flr_in_process[1]
  PIN cfg_flr_in_process[2]
    DIRECTION OUTPUT ;
    USE SIGNAL ;
    PORT
      LAYER met3 ;
      RECT 0.000 870.590 0.680 870.890 ;
    END
  END cfg_flr_in_process[2]
  PIN cfg_flr_in_process[3]
    DIRECTION OUTPUT ;
    USE SIGNAL ;
    PORT
      LAYER met3 ;
      RECT 0.000 871.950 0.680 872.250 ;
    END
  END cfg_flr_in_process[3]
  PIN cfg_function_power_state[0]
    DIRECTION OUTPUT ;
    USE SIGNAL ;
    PORT
      LAYER met3 ;
      RECT 0.000 873.310 0.680 873.610 ;
    END
  END cfg_function_power_state[0]
  PIN cfg_function_power_state[1]
    DIRECTION OUTPUT ;
    USE SIGNAL ;
    PORT
      LAYER met3 ;
      RECT 0.000 874.670 0.680 874.970 ;
    END
  END cfg_function_power_state[1]
  PIN cfg_function_power_state[2]
    DIRECTION OUTPUT ;
    USE SIGNAL ;
    PORT
      LAYER met3 ;
      RECT 0.000 876.030 0.680 876.330 ;
    END
  END cfg_function_power_state[2]
  PIN cfg_function_power_state[3]
    DIRECTION OUTPUT ;
    USE SIGNAL ;
    PORT
      LAYER met3 ;
      RECT 0.000 877.390 0.680 877.690 ;
    END
  END cfg_function_power_state[3]
  PIN cfg_function_power_state[4]
    DIRECTION OUTPUT ;
    USE SIGNAL ;
    PORT
      LAYER met3 ;
      RECT 0.000 878.750 0.680 879.050 ;
    END
  END cfg_function_power_state[4]
  PIN cfg_function_power_state[5]
    DIRECTION OUTPUT ;
    USE SIGNAL ;
    PORT
      LAYER met3 ;
      RECT 0.000 880.110 0.680 880.410 ;
    END
  END cfg_function_power_state[5]
  PIN cfg_function_power_state[6]
    DIRECTION OUTPUT ;
    USE SIGNAL ;
    PORT
      LAYER met3 ;
      RECT 0.000 881.470 0.680 881.770 ;
    END
  END cfg_function_power_state[6]
  PIN cfg_function_power_state[7]
    DIRECTION OUTPUT ;
    USE SIGNAL ;
    PORT
      LAYER met3 ;
      RECT 0.000 882.830 0.680 883.130 ;
    END
  END cfg_function_power_state[7]
  PIN cfg_function_power_state[8]
    DIRECTION OUTPUT ;
    USE SIGNAL ;
    PORT
      LAYER met3 ;
      RECT 0.000 884.190 0.680 884.490 ;
    END
  END cfg_function_power_state[8]
  PIN cfg_function_power_state[9]
    DIRECTION OUTPUT ;
    USE SIGNAL ;
    PORT
      LAYER met3 ;
      RECT 0.000 885.550 0.680 885.850 ;
    END
  END cfg_function_power_state[9]
  PIN cfg_function_power_state[10]
    DIRECTION OUTPUT ;
    USE SIGNAL ;
    PORT
      LAYER met3 ;
      RECT 0.000 886.910 0.680 887.210 ;
    END
  END cfg_function_power_state[10]
  PIN cfg_function_power_state[11]
    DIRECTION OUTPUT ;
    USE SIGNAL ;
    PORT
      LAYER met3 ;
      RECT 0.000 888.270 0.680 888.570 ;
    END
  END cfg_function_power_state[11]
  PIN cfg_function_status[0]
    DIRECTION OUTPUT ;
    USE SIGNAL ;
    PORT
      LAYER met3 ;
      RECT 999.320 2.910 1000.000 3.210 ;
    END
  END cfg_function_status[0]
  PIN cfg_function_status[1]
    DIRECTION OUTPUT ;
    USE SIGNAL ;
    PORT
      LAYER met3 ;
      RECT 999.320 4.270 1000.000 4.570 ;
    END
  END cfg_function_status[1]
  PIN cfg_function_status[2]
    DIRECTION OUTPUT ;
    USE SIGNAL ;
    PORT
      LAYER met3 ;
      RECT 999.320 5.630 1000.000 5.930 ;
    END
  END cfg_function_status[2]
  PIN cfg_function_status[3]
    DIRECTION OUTPUT ;
    USE SIGNAL ;
    PORT
      LAYER met3 ;
      RECT 999.320 6.990 1000.000 7.290 ;
    END
  END cfg_function_status[3]
  PIN cfg_function_status[4]
    DIRECTION OUTPUT ;
    USE SIGNAL ;
    PORT
      LAYER met3 ;
      RECT 999.320 8.350 1000.000 8.650 ;
    END
  END cfg_function_status[4]
  PIN cfg_function_status[5]
    DIRECTION OUTPUT ;
    USE SIGNAL ;
    PORT
      LAYER met3 ;
      RECT 999.320 9.710 1000.000 10.010 ;
    END
  END cfg_function_status[5]
  PIN cfg_function_status[6]
    DIRECTION OUTPUT ;
    USE SIGNAL ;
    PORT
      LAYER met3 ;
      RECT 999.320 11.070 1000.000 11.370 ;
    END
  END cfg_function_status[6]
  PIN cfg_function_status[7]
    DIRECTION OUTPUT ;
    USE SIGNAL ;
    PORT
      LAYER met3 ;
      RECT 999.320 12.430 1000.000 12.730 ;
    END
  END cfg_function_status[7]
  PIN cfg_function_status[8]
    DIRECTION OUTPUT ;
    USE SIGNAL ;
    PORT
      LAYER met3 ;
      RECT 999.320 13.790 1000.000 14.090 ;
    END
  END cfg_function_status[8]
  PIN cfg_function_status[9]
    DIRECTION OUTPUT ;
    USE SIGNAL ;
    PORT
      LAYER met3 ;
      RECT 999.320 15.150 1000.000 15.450 ;
    END
  END cfg_function_status[9]
  PIN cfg_function_status[10]
    DIRECTION OUTPUT ;
    USE SIGNAL ;
    PORT
      LAYER met3 ;
      RECT 999.320 16.510 1000.000 16.810 ;
    END
  END cfg_function_status[10]
  PIN cfg_function_status[11]
    DIRECTION OUTPUT ;
    USE SIGNAL ;
    PORT
      LAYER met3 ;
      RECT 999.320 17.190 1000.000 17.490 ;
    END
  END cfg_function_status[11]
  PIN cfg_function_status[12]
    DIRECTION OUTPUT ;
    USE SIGNAL ;
    PORT
      LAYER met3 ;
      RECT 999.320 18.550 1000.000 18.850 ;
    END
  END cfg_function_status[12]
  PIN cfg_function_status[13]
    DIRECTION OUTPUT ;
    USE SIGNAL ;
    PORT
      LAYER met3 ;
      RECT 999.320 19.910 1000.000 20.210 ;
    END
  END cfg_function_status[13]
  PIN cfg_function_status[14]
    DIRECTION OUTPUT ;
    USE SIGNAL ;
    PORT
      LAYER met3 ;
      RECT 999.320 21.950 1000.000 22.250 ;
    END
  END cfg_function_status[14]
  PIN cfg_function_status[15]
    DIRECTION OUTPUT ;
    USE SIGNAL ;
    PORT
      LAYER met3 ;
      RECT 999.320 23.310 1000.000 23.610 ;
    END
  END cfg_function_status[15]
  PIN cfg_hot_reset_out
    DIRECTION OUTPUT ;
    USE SIGNAL ;
    PORT
      LAYER met3 ;
      RECT 999.320 24.670 1000.000 24.970 ;
    END
  END cfg_hot_reset_out
  PIN cfg_interrupt_msi_data[0]
    DIRECTION OUTPUT ;
    USE SIGNAL ;
    PORT
      LAYER met3 ;
      RECT 999.320 26.030 1000.000 26.330 ;
    END
  END cfg_interrupt_msi_data[0]
  PIN cfg_interrupt_msi_data[1]
    DIRECTION OUTPUT ;
    USE SIGNAL ;
    PORT
      LAYER met3 ;
      RECT 999.320 26.710 1000.000 27.010 ;
    END
  END cfg_interrupt_msi_data[1]
  PIN cfg_interrupt_msi_data[2]
    DIRECTION OUTPUT ;
    USE SIGNAL ;
    PORT
      LAYER met3 ;
      RECT 999.320 28.750 1000.000 29.050 ;
    END
  END cfg_interrupt_msi_data[2]
  PIN cfg_interrupt_msi_data[3]
    DIRECTION OUTPUT ;
    USE SIGNAL ;
    PORT
      LAYER met3 ;
      RECT 999.320 30.110 1000.000 30.410 ;
    END
  END cfg_interrupt_msi_data[3]
  PIN cfg_interrupt_msi_data[4]
    DIRECTION OUTPUT ;
    USE SIGNAL ;
    PORT
      LAYER met3 ;
      RECT 999.320 31.470 1000.000 31.770 ;
    END
  END cfg_interrupt_msi_data[4]
  PIN cfg_interrupt_msi_data[5]
    DIRECTION OUTPUT ;
    USE SIGNAL ;
    PORT
      LAYER met3 ;
      RECT 999.320 32.150 1000.000 32.450 ;
    END
  END cfg_interrupt_msi_data[5]
  PIN cfg_interrupt_msi_data[6]
    DIRECTION OUTPUT ;
    USE SIGNAL ;
    PORT
      LAYER met3 ;
      RECT 999.320 33.510 1000.000 33.810 ;
    END
  END cfg_interrupt_msi_data[6]
  PIN cfg_interrupt_msi_data[7]
    DIRECTION OUTPUT ;
    USE SIGNAL ;
    PORT
      LAYER met3 ;
      RECT 999.320 34.870 1000.000 35.170 ;
    END
  END cfg_interrupt_msi_data[7]
  PIN cfg_interrupt_msi_data[8]
    DIRECTION OUTPUT ;
    USE SIGNAL ;
    PORT
      LAYER met3 ;
      RECT 999.320 36.230 1000.000 36.530 ;
    END
  END cfg_interrupt_msi_data[8]
  PIN cfg_interrupt_msi_data[9]
    DIRECTION OUTPUT ;
    USE SIGNAL ;
    PORT
      LAYER met3 ;
      RECT 999.320 37.590 1000.000 37.890 ;
    END
  END cfg_interrupt_msi_data[9]
  PIN cfg_interrupt_msi_data[10]
    DIRECTION OUTPUT ;
    USE SIGNAL ;
    PORT
      LAYER met3 ;
      RECT 999.320 39.630 1000.000 39.930 ;
    END
  END cfg_interrupt_msi_data[10]
  PIN cfg_interrupt_msi_data[11]
    DIRECTION OUTPUT ;
    USE SIGNAL ;
    PORT
      LAYER met3 ;
      RECT 999.320 40.990 1000.000 41.290 ;
    END
  END cfg_interrupt_msi_data[11]
  PIN cfg_interrupt_msi_data[12]
    DIRECTION OUTPUT ;
    USE SIGNAL ;
    PORT
      LAYER met3 ;
      RECT 999.320 41.670 1000.000 41.970 ;
    END
  END cfg_interrupt_msi_data[12]
  PIN cfg_interrupt_msi_data[13]
    DIRECTION OUTPUT ;
    USE SIGNAL ;
    PORT
      LAYER met3 ;
      RECT 999.320 43.030 1000.000 43.330 ;
    END
  END cfg_interrupt_msi_data[13]
  PIN cfg_interrupt_msi_data[14]
    DIRECTION OUTPUT ;
    USE SIGNAL ;
    PORT
      LAYER met3 ;
      RECT 999.320 45.070 1000.000 45.370 ;
    END
  END cfg_interrupt_msi_data[14]
  PIN cfg_interrupt_msi_data[15]
    DIRECTION OUTPUT ;
    USE SIGNAL ;
    PORT
      LAYER met3 ;
      RECT 999.320 46.430 1000.000 46.730 ;
    END
  END cfg_interrupt_msi_data[15]
  PIN cfg_interrupt_msi_data[16]
    DIRECTION OUTPUT ;
    USE SIGNAL ;
    PORT
      LAYER met3 ;
      RECT 999.320 47.110 1000.000 47.410 ;
    END
  END cfg_interrupt_msi_data[16]
  PIN cfg_interrupt_msi_data[17]
    DIRECTION OUTPUT ;
    USE SIGNAL ;
    PORT
      LAYER met3 ;
      RECT 999.320 48.470 1000.000 48.770 ;
    END
  END cfg_interrupt_msi_data[17]
  PIN cfg_interrupt_msi_data[18]
    DIRECTION OUTPUT ;
    USE SIGNAL ;
    PORT
      LAYER met3 ;
      RECT 999.320 49.830 1000.000 50.130 ;
    END
  END cfg_interrupt_msi_data[18]
  PIN cfg_interrupt_msi_data[19]
    DIRECTION OUTPUT ;
    USE SIGNAL ;
    PORT
      LAYER met3 ;
      RECT 999.320 51.190 1000.000 51.490 ;
    END
  END cfg_interrupt_msi_data[19]
  PIN cfg_interrupt_msi_data[20]
    DIRECTION OUTPUT ;
    USE SIGNAL ;
    PORT
      LAYER met3 ;
      RECT 999.320 52.550 1000.000 52.850 ;
    END
  END cfg_interrupt_msi_data[20]
  PIN cfg_interrupt_msi_data[21]
    DIRECTION OUTPUT ;
    USE SIGNAL ;
    PORT
      LAYER met3 ;
      RECT 999.320 54.590 1000.000 54.890 ;
    END
  END cfg_interrupt_msi_data[21]
  PIN cfg_interrupt_msi_data[22]
    DIRECTION OUTPUT ;
    USE SIGNAL ;
    PORT
      LAYER met3 ;
      RECT 999.320 55.950 1000.000 56.250 ;
    END
  END cfg_interrupt_msi_data[22]
  PIN cfg_interrupt_msi_data[23]
    DIRECTION OUTPUT ;
    USE SIGNAL ;
    PORT
      LAYER met3 ;
      RECT 999.320 57.310 1000.000 57.610 ;
    END
  END cfg_interrupt_msi_data[23]
  PIN cfg_interrupt_msi_data[24]
    DIRECTION OUTPUT ;
    USE SIGNAL ;
    PORT
      LAYER met3 ;
      RECT 999.320 58.670 1000.000 58.970 ;
    END
  END cfg_interrupt_msi_data[24]
  PIN cfg_interrupt_msi_data[25]
    DIRECTION OUTPUT ;
    USE SIGNAL ;
    PORT
      LAYER met3 ;
      RECT 999.320 60.030 1000.000 60.330 ;
    END
  END cfg_interrupt_msi_data[25]
  PIN cfg_interrupt_msi_data[26]
    DIRECTION OUTPUT ;
    USE SIGNAL ;
    PORT
      LAYER met3 ;
      RECT 999.320 60.710 1000.000 61.010 ;
    END
  END cfg_interrupt_msi_data[26]
  PIN cfg_interrupt_msi_data[27]
    DIRECTION OUTPUT ;
    USE SIGNAL ;
    PORT
      LAYER met3 ;
      RECT 999.320 62.070 1000.000 62.370 ;
    END
  END cfg_interrupt_msi_data[27]
  PIN cfg_interrupt_msi_data[28]
    DIRECTION OUTPUT ;
    USE SIGNAL ;
    PORT
      LAYER met3 ;
      RECT 999.320 63.430 1000.000 63.730 ;
    END
  END cfg_interrupt_msi_data[28]
  PIN cfg_interrupt_msi_data[29]
    DIRECTION OUTPUT ;
    USE SIGNAL ;
    PORT
      LAYER met3 ;
      RECT 999.320 64.790 1000.000 65.090 ;
    END
  END cfg_interrupt_msi_data[29]
  PIN cfg_interrupt_msi_data[30]
    DIRECTION OUTPUT ;
    USE SIGNAL ;
    PORT
      LAYER met3 ;
      RECT 999.320 66.150 1000.000 66.450 ;
    END
  END cfg_interrupt_msi_data[30]
  PIN cfg_interrupt_msi_data[31]
    DIRECTION OUTPUT ;
    USE SIGNAL ;
    PORT
      LAYER met3 ;
      RECT 999.320 67.510 1000.000 67.810 ;
    END
  END cfg_interrupt_msi_data[31]
  PIN cfg_interrupt_msi_enable[0]
    DIRECTION OUTPUT ;
    USE SIGNAL ;
    PORT
      LAYER met3 ;
      RECT 999.320 68.870 1000.000 69.170 ;
    END
  END cfg_interrupt_msi_enable[0]
  PIN cfg_interrupt_msi_enable[1]
    DIRECTION OUTPUT ;
    USE SIGNAL ;
    PORT
      LAYER met3 ;
      RECT 999.320 70.230 1000.000 70.530 ;
    END
  END cfg_interrupt_msi_enable[1]
  PIN cfg_interrupt_msi_enable[2]
    DIRECTION OUTPUT ;
    USE SIGNAL ;
    PORT
      LAYER met3 ;
      RECT 999.320 71.590 1000.000 71.890 ;
    END
  END cfg_interrupt_msi_enable[2]
  PIN cfg_interrupt_msi_enable[3]
    DIRECTION OUTPUT ;
    USE SIGNAL ;
    PORT
      LAYER met3 ;
      RECT 999.320 72.950 1000.000 73.250 ;
    END
  END cfg_interrupt_msi_enable[3]
  PIN cfg_interrupt_msi_fail
    DIRECTION OUTPUT ;
    USE SIGNAL ;
    PORT
      LAYER met3 ;
      RECT 999.320 74.310 1000.000 74.610 ;
    END
  END cfg_interrupt_msi_fail
  PIN cfg_interrupt_msi_mask_update
    DIRECTION OUTPUT ;
    USE SIGNAL ;
    PORT
      LAYER met3 ;
      RECT 999.320 76.350 1000.000 76.650 ;
    END
  END cfg_interrupt_msi_mask_update
  PIN cfg_interrupt_msi_mmenable[0]
    DIRECTION OUTPUT ;
    USE SIGNAL ;
    PORT
      LAYER met3 ;
      RECT 999.320 77.710 1000.000 78.010 ;
    END
  END cfg_interrupt_msi_mmenable[0]
  PIN cfg_interrupt_msi_mmenable[1]
    DIRECTION OUTPUT ;
    USE SIGNAL ;
    PORT
      LAYER met3 ;
      RECT 999.320 79.070 1000.000 79.370 ;
    END
  END cfg_interrupt_msi_mmenable[1]
  PIN cfg_interrupt_msi_mmenable[2]
    DIRECTION OUTPUT ;
    USE SIGNAL ;
    PORT
      LAYER met3 ;
      RECT 999.320 80.430 1000.000 80.730 ;
    END
  END cfg_interrupt_msi_mmenable[2]
  PIN cfg_interrupt_msi_mmenable[3]
    DIRECTION OUTPUT ;
    USE SIGNAL ;
    PORT
      LAYER met3 ;
      RECT 999.320 81.790 1000.000 82.090 ;
    END
  END cfg_interrupt_msi_mmenable[3]
  PIN cfg_interrupt_msi_mmenable[4]
    DIRECTION OUTPUT ;
    USE SIGNAL ;
    PORT
      LAYER met3 ;
      RECT 999.320 83.150 1000.000 83.450 ;
    END
  END cfg_interrupt_msi_mmenable[4]
  PIN cfg_interrupt_msi_mmenable[5]
    DIRECTION OUTPUT ;
    USE SIGNAL ;
    PORT
      LAYER met3 ;
      RECT 999.320 84.510 1000.000 84.810 ;
    END
  END cfg_interrupt_msi_mmenable[5]
  PIN cfg_interrupt_msi_mmenable[6]
    DIRECTION OUTPUT ;
    USE SIGNAL ;
    PORT
      LAYER met3 ;
      RECT 999.320 85.870 1000.000 86.170 ;
    END
  END cfg_interrupt_msi_mmenable[6]
  PIN cfg_interrupt_msi_mmenable[7]
    DIRECTION OUTPUT ;
    USE SIGNAL ;
    PORT
      LAYER met3 ;
      RECT 999.320 87.230 1000.000 87.530 ;
    END
  END cfg_interrupt_msi_mmenable[7]
  PIN cfg_interrupt_msi_mmenable[8]
    DIRECTION OUTPUT ;
    USE SIGNAL ;
    PORT
      LAYER met3 ;
      RECT 999.320 88.590 1000.000 88.890 ;
    END
  END cfg_interrupt_msi_mmenable[8]
  PIN cfg_interrupt_msi_mmenable[9]
    DIRECTION OUTPUT ;
    USE SIGNAL ;
    PORT
      LAYER met3 ;
      RECT 999.320 89.950 1000.000 90.250 ;
    END
  END cfg_interrupt_msi_mmenable[9]
  PIN cfg_interrupt_msi_mmenable[10]
    DIRECTION OUTPUT ;
    USE SIGNAL ;
    PORT
      LAYER met3 ;
      RECT 999.320 91.310 1000.000 91.610 ;
    END
  END cfg_interrupt_msi_mmenable[10]
  PIN cfg_interrupt_msi_mmenable[11]
    DIRECTION OUTPUT ;
    USE SIGNAL ;
    PORT
      LAYER met3 ;
      RECT 999.320 92.670 1000.000 92.970 ;
    END
  END cfg_interrupt_msi_mmenable[11]
  PIN cfg_interrupt_msi_sent
    DIRECTION OUTPUT ;
    USE SIGNAL ;
    PORT
      LAYER met3 ;
      RECT 999.320 94.030 1000.000 94.330 ;
    END
  END cfg_interrupt_msi_sent
  PIN cfg_interrupt_sent
    DIRECTION OUTPUT ;
    USE SIGNAL ;
    PORT
      LAYER met3 ;
      RECT 999.320 95.390 1000.000 95.690 ;
    END
  END cfg_interrupt_sent
  PIN cfg_link_power_state[0]
    DIRECTION OUTPUT ;
    USE SIGNAL ;
    PORT
      LAYER met3 ;
      RECT 999.320 96.750 1000.000 97.050 ;
    END
  END cfg_link_power_state[0]
  PIN cfg_link_power_state[1]
    DIRECTION OUTPUT ;
    USE SIGNAL ;
    PORT
      LAYER met3 ;
      RECT 999.320 98.110 1000.000 98.410 ;
    END
  END cfg_link_power_state[1]
  PIN cfg_local_error
    DIRECTION OUTPUT ;
    USE SIGNAL ;
    PORT
      LAYER met3 ;
      RECT 999.320 99.470 1000.000 99.770 ;
    END
  END cfg_local_error
  PIN cfg_ltr_enable
    DIRECTION OUTPUT ;
    USE SIGNAL ;
    PORT
      LAYER met3 ;
      RECT 999.320 100.150 1000.000 100.450 ;
    END
  END cfg_ltr_enable
  PIN cfg_ltssm_state[0]
    DIRECTION OUTPUT ;
    USE SIGNAL ;
    PORT
      LAYER met3 ;
      RECT 999.320 101.510 1000.000 101.810 ;
    END
  END cfg_ltssm_state[0]
  PIN cfg_ltssm_state[1]
    DIRECTION OUTPUT ;
    USE SIGNAL ;
    PORT
      LAYER met3 ;
      RECT 999.320 102.870 1000.000 103.170 ;
    END
  END cfg_ltssm_state[1]
  PIN cfg_ltssm_state[2]
    DIRECTION OUTPUT ;
    USE SIGNAL ;
    PORT
      LAYER met3 ;
      RECT 999.320 104.910 1000.000 105.210 ;
    END
  END cfg_ltssm_state[2]
  PIN cfg_ltssm_state[3]
    DIRECTION OUTPUT ;
    USE SIGNAL ;
    PORT
      LAYER met3 ;
      RECT 999.320 106.270 1000.000 106.570 ;
    END
  END cfg_ltssm_state[3]
  PIN cfg_ltssm_state[4]
    DIRECTION OUTPUT ;
    USE SIGNAL ;
    PORT
      LAYER met3 ;
      RECT 999.320 107.630 1000.000 107.930 ;
    END
  END cfg_ltssm_state[4]
  PIN cfg_ltssm_state[5]
    DIRECTION OUTPUT ;
    USE SIGNAL ;
    PORT
      LAYER met3 ;
      RECT 999.320 108.990 1000.000 109.290 ;
    END
  END cfg_ltssm_state[5]
  PIN cfg_max_payload[0]
    DIRECTION OUTPUT ;
    USE SIGNAL ;
    PORT
      LAYER met3 ;
      RECT 999.320 110.350 1000.000 110.650 ;
    END
  END cfg_max_payload[0]
  PIN cfg_max_payload[1]
    DIRECTION OUTPUT ;
    USE SIGNAL ;
    PORT
      LAYER met3 ;
      RECT 999.320 111.710 1000.000 112.010 ;
    END
  END cfg_max_payload[1]
  PIN cfg_max_payload[2]
    DIRECTION OUTPUT ;
    USE SIGNAL ;
    PORT
      LAYER met3 ;
      RECT 999.320 113.070 1000.000 113.370 ;
    END
  END cfg_max_payload[2]
  PIN cfg_max_read_req[0]
    DIRECTION OUTPUT ;
    USE SIGNAL ;
    PORT
      LAYER met3 ;
      RECT 999.320 114.430 1000.000 114.730 ;
    END
  END cfg_max_read_req[0]
  PIN cfg_max_read_req[1]
    DIRECTION OUTPUT ;
    USE SIGNAL ;
    PORT
      LAYER met3 ;
      RECT 999.320 115.790 1000.000 116.090 ;
    END
  END cfg_max_read_req[1]
  PIN cfg_max_read_req[2]
    DIRECTION OUTPUT ;
    USE SIGNAL ;
    PORT
      LAYER met3 ;
      RECT 999.320 117.150 1000.000 117.450 ;
    END
  END cfg_max_read_req[2]
  PIN cfg_mgmt_read_data[0]
    DIRECTION OUTPUT ;
    USE SIGNAL ;
    PORT
      LAYER met3 ;
      RECT 999.320 118.510 1000.000 118.810 ;
    END
  END cfg_mgmt_read_data[0]
  PIN cfg_mgmt_read_data[1]
    DIRECTION OUTPUT ;
    USE SIGNAL ;
    PORT
      LAYER met3 ;
      RECT 999.320 119.870 1000.000 120.170 ;
    END
  END cfg_mgmt_read_data[1]
  PIN cfg_mgmt_read_data[2]
    DIRECTION OUTPUT ;
    USE SIGNAL ;
    PORT
      LAYER met3 ;
      RECT 999.320 121.230 1000.000 121.530 ;
    END
  END cfg_mgmt_read_data[2]
  PIN cfg_mgmt_read_data[3]
    DIRECTION OUTPUT ;
    USE SIGNAL ;
    PORT
      LAYER met3 ;
      RECT 999.320 122.590 1000.000 122.890 ;
    END
  END cfg_mgmt_read_data[3]
  PIN cfg_mgmt_read_data[4]
    DIRECTION OUTPUT ;
    USE SIGNAL ;
    PORT
      LAYER met3 ;
      RECT 999.320 123.950 1000.000 124.250 ;
    END
  END cfg_mgmt_read_data[4]
  PIN cfg_mgmt_read_data[5]
    DIRECTION OUTPUT ;
    USE SIGNAL ;
    PORT
      LAYER met3 ;
      RECT 999.320 125.310 1000.000 125.610 ;
    END
  END cfg_mgmt_read_data[5]
  PIN cfg_mgmt_read_data[6]
    DIRECTION OUTPUT ;
    USE SIGNAL ;
    PORT
      LAYER met3 ;
      RECT 999.320 126.670 1000.000 126.970 ;
    END
  END cfg_mgmt_read_data[6]
  PIN cfg_mgmt_read_data[7]
    DIRECTION OUTPUT ;
    USE SIGNAL ;
    PORT
      LAYER met3 ;
      RECT 999.320 128.030 1000.000 128.330 ;
    END
  END cfg_mgmt_read_data[7]
  PIN cfg_mgmt_read_data[8]
    DIRECTION OUTPUT ;
    USE SIGNAL ;
    PORT
      LAYER met3 ;
      RECT 999.320 129.390 1000.000 129.690 ;
    END
  END cfg_mgmt_read_data[8]
  PIN cfg_mgmt_read_data[9]
    DIRECTION OUTPUT ;
    USE SIGNAL ;
    PORT
      LAYER met3 ;
      RECT 999.320 130.070 1000.000 130.370 ;
    END
  END cfg_mgmt_read_data[9]
  PIN cfg_mgmt_read_data[10]
    DIRECTION OUTPUT ;
    USE SIGNAL ;
    PORT
      LAYER met3 ;
      RECT 999.320 132.110 1000.000 132.410 ;
    END
  END cfg_mgmt_read_data[10]
  PIN cfg_mgmt_read_data[11]
    DIRECTION OUTPUT ;
    USE SIGNAL ;
    PORT
      LAYER met3 ;
      RECT 999.320 132.790 1000.000 133.090 ;
    END
  END cfg_mgmt_read_data[11]
  PIN cfg_mgmt_read_data[12]
    DIRECTION OUTPUT ;
    USE SIGNAL ;
    PORT
      LAYER met3 ;
      RECT 999.320 134.830 1000.000 135.130 ;
    END
  END cfg_mgmt_read_data[12]
  PIN cfg_mgmt_read_data[13]
    DIRECTION OUTPUT ;
    USE SIGNAL ;
    PORT
      LAYER met3 ;
      RECT 999.320 135.510 1000.000 135.810 ;
    END
  END cfg_mgmt_read_data[13]
  PIN cfg_mgmt_read_data[14]
    DIRECTION OUTPUT ;
    USE SIGNAL ;
    PORT
      LAYER met3 ;
      RECT 999.320 137.550 1000.000 137.850 ;
    END
  END cfg_mgmt_read_data[14]
  PIN cfg_mgmt_read_data[15]
    DIRECTION OUTPUT ;
    USE SIGNAL ;
    PORT
      LAYER met3 ;
      RECT 999.320 138.230 1000.000 138.530 ;
    END
  END cfg_mgmt_read_data[15]
  PIN cfg_mgmt_read_data[16]
    DIRECTION OUTPUT ;
    USE SIGNAL ;
    PORT
      LAYER met3 ;
      RECT 999.320 140.270 1000.000 140.570 ;
    END
  END cfg_mgmt_read_data[16]
  PIN cfg_mgmt_read_data[17]
    DIRECTION OUTPUT ;
    USE SIGNAL ;
    PORT
      LAYER met3 ;
      RECT 999.320 140.950 1000.000 141.250 ;
    END
  END cfg_mgmt_read_data[17]
  PIN cfg_mgmt_read_data[18]
    DIRECTION OUTPUT ;
    USE SIGNAL ;
    PORT
      LAYER met3 ;
      RECT 999.320 142.990 1000.000 143.290 ;
    END
  END cfg_mgmt_read_data[18]
  PIN cfg_mgmt_read_data[19]
    DIRECTION OUTPUT ;
    USE SIGNAL ;
    PORT
      LAYER met3 ;
      RECT 999.320 143.670 1000.000 143.970 ;
    END
  END cfg_mgmt_read_data[19]
  PIN cfg_mgmt_read_data[20]
    DIRECTION OUTPUT ;
    USE SIGNAL ;
    PORT
      LAYER met3 ;
      RECT 999.320 145.710 1000.000 146.010 ;
    END
  END cfg_mgmt_read_data[20]
  PIN cfg_mgmt_read_data[21]
    DIRECTION OUTPUT ;
    USE SIGNAL ;
    PORT
      LAYER met3 ;
      RECT 999.320 146.390 1000.000 146.690 ;
    END
  END cfg_mgmt_read_data[21]
  PIN cfg_mgmt_read_data[22]
    DIRECTION OUTPUT ;
    USE SIGNAL ;
    PORT
      LAYER met3 ;
      RECT 999.320 148.430 1000.000 148.730 ;
    END
  END cfg_mgmt_read_data[22]
  PIN cfg_mgmt_read_data[23]
    DIRECTION OUTPUT ;
    USE SIGNAL ;
    PORT
      LAYER met3 ;
      RECT 999.320 149.790 1000.000 150.090 ;
    END
  END cfg_mgmt_read_data[23]
  PIN cfg_mgmt_read_data[24]
    DIRECTION OUTPUT ;
    USE SIGNAL ;
    PORT
      LAYER met3 ;
      RECT 999.320 151.150 1000.000 151.450 ;
    END
  END cfg_mgmt_read_data[24]
  PIN cfg_mgmt_read_data[25]
    DIRECTION OUTPUT ;
    USE SIGNAL ;
    PORT
      LAYER met3 ;
      RECT 999.320 152.510 1000.000 152.810 ;
    END
  END cfg_mgmt_read_data[25]
  PIN cfg_mgmt_read_data[26]
    DIRECTION OUTPUT ;
    USE SIGNAL ;
    PORT
      LAYER met3 ;
      RECT 999.320 153.870 1000.000 154.170 ;
    END
  END cfg_mgmt_read_data[26]
  PIN cfg_mgmt_read_data[27]
    DIRECTION OUTPUT ;
    USE SIGNAL ;
    PORT
      LAYER met3 ;
      RECT 999.320 155.230 1000.000 155.530 ;
    END
  END cfg_mgmt_read_data[27]
  PIN cfg_mgmt_read_data[28]
    DIRECTION OUTPUT ;
    USE SIGNAL ;
    PORT
      LAYER met3 ;
      RECT 999.320 156.590 1000.000 156.890 ;
    END
  END cfg_mgmt_read_data[28]
  PIN cfg_mgmt_read_data[29]
    DIRECTION OUTPUT ;
    USE SIGNAL ;
    PORT
      LAYER met3 ;
      RECT 999.320 157.950 1000.000 158.250 ;
    END
  END cfg_mgmt_read_data[29]
  PIN cfg_mgmt_read_data[30]
    DIRECTION OUTPUT ;
    USE SIGNAL ;
    PORT
      LAYER met3 ;
      RECT 999.320 158.630 1000.000 158.930 ;
    END
  END cfg_mgmt_read_data[30]
  PIN cfg_mgmt_read_data[31]
    DIRECTION OUTPUT ;
    USE SIGNAL ;
    PORT
      LAYER met3 ;
      RECT 999.320 160.670 1000.000 160.970 ;
    END
  END cfg_mgmt_read_data[31]
  PIN cfg_mgmt_read_write_done
    DIRECTION OUTPUT ;
    USE SIGNAL ;
    PORT
      LAYER met3 ;
      RECT 999.320 161.350 1000.000 161.650 ;
    END
  END cfg_mgmt_read_write_done
  PIN cfg_msg_received
    DIRECTION OUTPUT ;
    USE SIGNAL ;
    PORT
      LAYER met3 ;
      RECT 999.320 163.390 1000.000 163.690 ;
    END
  END cfg_msg_received
  PIN cfg_msg_received_data[0]
    DIRECTION OUTPUT ;
    USE SIGNAL ;
    PORT
      LAYER met3 ;
      RECT 999.320 164.070 1000.000 164.370 ;
    END
  END cfg_msg_received_data[0]
  PIN cfg_msg_received_data[1]
    DIRECTION OUTPUT ;
    USE SIGNAL ;
    PORT
      LAYER met3 ;
      RECT 999.320 166.110 1000.000 166.410 ;
    END
  END cfg_msg_received_data[1]
  PIN cfg_msg_received_data[2]
    DIRECTION OUTPUT ;
    USE SIGNAL ;
    PORT
      LAYER met3 ;
      RECT 999.320 166.790 1000.000 167.090 ;
    END
  END cfg_msg_received_data[2]
  PIN cfg_msg_received_data[3]
    DIRECTION OUTPUT ;
    USE SIGNAL ;
    PORT
      LAYER met3 ;
      RECT 999.320 168.830 1000.000 169.130 ;
    END
  END cfg_msg_received_data[3]
  PIN cfg_msg_received_data[4]
    DIRECTION OUTPUT ;
    USE SIGNAL ;
    PORT
      LAYER met3 ;
      RECT 999.320 169.510 1000.000 169.810 ;
    END
  END cfg_msg_received_data[4]
  PIN cfg_msg_received_data[5]
    DIRECTION OUTPUT ;
    USE SIGNAL ;
    PORT
      LAYER met3 ;
      RECT 999.320 171.550 1000.000 171.850 ;
    END
  END cfg_msg_received_data[5]
  PIN cfg_msg_received_data[6]
    DIRECTION OUTPUT ;
    USE SIGNAL ;
    PORT
      LAYER met3 ;
      RECT 999.320 172.230 1000.000 172.530 ;
    END
  END cfg_msg_received_data[6]
  PIN cfg_msg_received_data[7]
    DIRECTION OUTPUT ;
    USE SIGNAL ;
    PORT
      LAYER met3 ;
      RECT 999.320 174.270 1000.000 174.570 ;
    END
  END cfg_msg_received_data[7]
  PIN cfg_msg_received_type[0]
    DIRECTION OUTPUT ;
    USE SIGNAL ;
    PORT
      LAYER met3 ;
      RECT 999.320 175.630 1000.000 175.930 ;
    END
  END cfg_msg_received_type[0]
  PIN cfg_msg_received_type[1]
    DIRECTION OUTPUT ;
    USE SIGNAL ;
    PORT
      LAYER met3 ;
      RECT 999.320 176.990 1000.000 177.290 ;
    END
  END cfg_msg_received_type[1]
  PIN cfg_msg_received_type[2]
    DIRECTION OUTPUT ;
    USE SIGNAL ;
    PORT
      LAYER met3 ;
      RECT 999.320 178.350 1000.000 178.650 ;
    END
  END cfg_msg_received_type[2]
  PIN cfg_msg_received_type[3]
    DIRECTION OUTPUT ;
    USE SIGNAL ;
    PORT
      LAYER met3 ;
      RECT 999.320 179.710 1000.000 180.010 ;
    END
  END cfg_msg_received_type[3]
  PIN cfg_msg_received_type[4]
    DIRECTION OUTPUT ;
    USE SIGNAL ;
    PORT
      LAYER met3 ;
      RECT 999.320 181.070 1000.000 181.370 ;
    END
  END cfg_msg_received_type[4]
  PIN cfg_msg_transmit_done
    DIRECTION OUTPUT ;
    USE SIGNAL ;
    PORT
      LAYER met3 ;
      RECT 999.320 182.430 1000.000 182.730 ;
    END
  END cfg_msg_transmit_done
  PIN cfg_negotiated_width[0]
    DIRECTION OUTPUT ;
    USE SIGNAL ;
    PORT
      LAYER met3 ;
      RECT 999.320 183.790 1000.000 184.090 ;
    END
  END cfg_negotiated_width[0]
  PIN cfg_negotiated_width[1]
    DIRECTION OUTPUT ;
    USE SIGNAL ;
    PORT
      LAYER met3 ;
      RECT 999.320 185.150 1000.000 185.450 ;
    END
  END cfg_negotiated_width[1]
  PIN cfg_negotiated_width[2]
    DIRECTION OUTPUT ;
    USE SIGNAL ;
    PORT
      LAYER met3 ;
      RECT 999.320 186.510 1000.000 186.810 ;
    END
  END cfg_negotiated_width[2]
  PIN cfg_negotiated_width[3]
    DIRECTION OUTPUT ;
    USE SIGNAL ;
    PORT
      LAYER met3 ;
      RECT 999.320 187.870 1000.000 188.170 ;
    END
  END cfg_negotiated_width[3]
  PIN cfg_obff_enable[0]
    DIRECTION OUTPUT ;
    USE SIGNAL ;
    PORT
      LAYER met3 ;
      RECT 999.320 189.230 1000.000 189.530 ;
    END
  END cfg_obff_enable[0]
  PIN cfg_obff_enable[1]
    DIRECTION OUTPUT ;
    USE SIGNAL ;
    PORT
      LAYER met3 ;
      RECT 999.320 190.590 1000.000 190.890 ;
    END
  END cfg_obff_enable[1]
  PIN cfg_per_func_status_data[0]
    DIRECTION OUTPUT ;
    USE SIGNAL ;
    PORT
      LAYER met3 ;
      RECT 999.320 191.950 1000.000 192.250 ;
    END
  END cfg_per_func_status_data[0]
  PIN cfg_per_func_status_data[1]
    DIRECTION OUTPUT ;
    USE SIGNAL ;
    PORT
      LAYER met3 ;
      RECT 999.320 193.310 1000.000 193.610 ;
    END
  END cfg_per_func_status_data[1]
  PIN cfg_per_func_status_data[2]
    DIRECTION OUTPUT ;
    USE SIGNAL ;
    PORT
      LAYER met3 ;
      RECT 999.320 194.670 1000.000 194.970 ;
    END
  END cfg_per_func_status_data[2]
  PIN cfg_per_func_status_data[3]
    DIRECTION OUTPUT ;
    USE SIGNAL ;
    PORT
      LAYER met3 ;
      RECT 999.320 196.030 1000.000 196.330 ;
    END
  END cfg_per_func_status_data[3]
  PIN cfg_per_func_status_data[4]
    DIRECTION OUTPUT ;
    USE SIGNAL ;
    PORT
      LAYER met3 ;
      RECT 999.320 197.390 1000.000 197.690 ;
    END
  END cfg_per_func_status_data[4]
  PIN cfg_per_func_status_data[5]
    DIRECTION OUTPUT ;
    USE SIGNAL ;
    PORT
      LAYER met3 ;
      RECT 999.320 198.750 1000.000 199.050 ;
    END
  END cfg_per_func_status_data[5]
  PIN cfg_per_func_status_data[6]
    DIRECTION OUTPUT ;
    USE SIGNAL ;
    PORT
      LAYER met3 ;
      RECT 999.320 200.110 1000.000 200.410 ;
    END
  END cfg_per_func_status_data[6]
  PIN cfg_per_func_status_data[7]
    DIRECTION OUTPUT ;
    USE SIGNAL ;
    PORT
      LAYER met3 ;
      RECT 999.320 201.470 1000.000 201.770 ;
    END
  END cfg_per_func_status_data[7]
  PIN cfg_per_func_status_data[8]
    DIRECTION OUTPUT ;
    USE SIGNAL ;
    PORT
      LAYER met3 ;
      RECT 999.320 202.830 1000.000 203.130 ;
    END
  END cfg_per_func_status_data[8]
  PIN cfg_per_func_status_data[9]
    DIRECTION OUTPUT ;
    USE SIGNAL ;
    PORT
      LAYER met3 ;
      RECT 999.320 204.190 1000.000 204.490 ;
    END
  END cfg_per_func_status_data[9]
  PIN cfg_per_func_status_data[10]
    DIRECTION OUTPUT ;
    USE SIGNAL ;
    PORT
      LAYER met3 ;
      RECT 999.320 205.550 1000.000 205.850 ;
    END
  END cfg_per_func_status_data[10]
  PIN cfg_per_func_status_data[11]
    DIRECTION OUTPUT ;
    USE SIGNAL ;
    PORT
      LAYER met3 ;
      RECT 999.320 206.910 1000.000 207.210 ;
    END
  END cfg_per_func_status_data[11]
  PIN cfg_per_func_status_data[12]
    DIRECTION OUTPUT ;
    USE SIGNAL ;
    PORT
      LAYER met3 ;
      RECT 999.320 208.270 1000.000 208.570 ;
    END
  END cfg_per_func_status_data[12]
  PIN cfg_per_func_status_data[13]
    DIRECTION OUTPUT ;
    USE SIGNAL ;
    PORT
      LAYER met3 ;
      RECT 999.320 209.630 1000.000 209.930 ;
    END
  END cfg_per_func_status_data[13]
  PIN cfg_per_func_status_data[14]
    DIRECTION OUTPUT ;
    USE SIGNAL ;
    PORT
      LAYER met3 ;
      RECT 999.320 210.990 1000.000 211.290 ;
    END
  END cfg_per_func_status_data[14]
  PIN cfg_per_func_status_data[15]
    DIRECTION OUTPUT ;
    USE SIGNAL ;
    PORT
      LAYER met3 ;
      RECT 999.320 212.350 1000.000 212.650 ;
    END
  END cfg_per_func_status_data[15]
  PIN cfg_per_function_update_done
    DIRECTION OUTPUT ;
    USE SIGNAL ;
    PORT
      LAYER met3 ;
      RECT 999.320 213.710 1000.000 214.010 ;
    END
  END cfg_per_function_update_done
  PIN cfg_phy_link_down
    DIRECTION OUTPUT ;
    USE SIGNAL ;
    PORT
      LAYER met3 ;
      RECT 999.320 215.070 1000.000 215.370 ;
    END
  END cfg_phy_link_down
  PIN cfg_phy_link_status[0]
    DIRECTION OUTPUT ;
    USE SIGNAL ;
    PORT
      LAYER met3 ;
      RECT 999.320 216.430 1000.000 216.730 ;
    END
  END cfg_phy_link_status[0]
  PIN cfg_phy_link_status[1]
    DIRECTION OUTPUT ;
    USE SIGNAL ;
    PORT
      LAYER met3 ;
      RECT 999.320 217.790 1000.000 218.090 ;
    END
  END cfg_phy_link_status[1]
  PIN cfg_pl_status_change
    DIRECTION OUTPUT ;
    USE SIGNAL ;
    PORT
      LAYER met3 ;
      RECT 999.320 219.150 1000.000 219.450 ;
    END
  END cfg_pl_status_change
  PIN cfg_power_state_change_interrupt
    DIRECTION OUTPUT ;
    USE SIGNAL ;
    PORT
      LAYER met3 ;
      RECT 999.320 220.510 1000.000 220.810 ;
    END
  END cfg_power_state_change_interrupt
  PIN cfg_rcb_status[0]
    DIRECTION OUTPUT ;
    USE SIGNAL ;
    PORT
      LAYER met3 ;
      RECT 999.320 221.870 1000.000 222.170 ;
    END
  END cfg_rcb_status[0]
  PIN cfg_rcb_status[1]
    DIRECTION OUTPUT ;
    USE SIGNAL ;
    PORT
      LAYER met3 ;
      RECT 999.320 223.230 1000.000 223.530 ;
    END
  END cfg_rcb_status[1]
  PIN cfg_rcb_status[2]
    DIRECTION OUTPUT ;
    USE SIGNAL ;
    PORT
      LAYER met3 ;
      RECT 999.320 224.590 1000.000 224.890 ;
    END
  END cfg_rcb_status[2]
  PIN cfg_rcb_status[3]
    DIRECTION OUTPUT ;
    USE SIGNAL ;
    PORT
      LAYER met3 ;
      RECT 999.320 225.950 1000.000 226.250 ;
    END
  END cfg_rcb_status[3]
  PIN cfg_tph_requester_enable[0]
    DIRECTION OUTPUT ;
    USE SIGNAL ;
    PORT
      LAYER met3 ;
      RECT 999.320 227.310 1000.000 227.610 ;
    END
  END cfg_tph_requester_enable[0]
  PIN cfg_tph_requester_enable[1]
    DIRECTION OUTPUT ;
    USE SIGNAL ;
    PORT
      LAYER met3 ;
      RECT 999.320 228.670 1000.000 228.970 ;
    END
  END cfg_tph_requester_enable[1]
  PIN cfg_tph_requester_enable[2]
    DIRECTION OUTPUT ;
    USE SIGNAL ;
    PORT
      LAYER met3 ;
      RECT 999.320 230.030 1000.000 230.330 ;
    END
  END cfg_tph_requester_enable[2]
  PIN cfg_tph_requester_enable[3]
    DIRECTION OUTPUT ;
    USE SIGNAL ;
    PORT
      LAYER met3 ;
      RECT 999.320 231.390 1000.000 231.690 ;
    END
  END cfg_tph_requester_enable[3]
  PIN cfg_tph_st_mode[0]
    DIRECTION OUTPUT ;
    USE SIGNAL ;
    PORT
      LAYER met3 ;
      RECT 999.320 232.750 1000.000 233.050 ;
    END
  END cfg_tph_st_mode[0]
  PIN cfg_tph_st_mode[1]
    DIRECTION OUTPUT ;
    USE SIGNAL ;
    PORT
      LAYER met3 ;
      RECT 999.320 234.110 1000.000 234.410 ;
    END
  END cfg_tph_st_mode[1]
  PIN cfg_tph_st_mode[2]
    DIRECTION OUTPUT ;
    USE SIGNAL ;
    PORT
      LAYER met3 ;
      RECT 999.320 235.470 1000.000 235.770 ;
    END
  END cfg_tph_st_mode[2]
  PIN cfg_tph_st_mode[3]
    DIRECTION OUTPUT ;
    USE SIGNAL ;
    PORT
      LAYER met3 ;
      RECT 999.320 236.830 1000.000 237.130 ;
    END
  END cfg_tph_st_mode[3]
  PIN cfg_tph_st_mode[4]
    DIRECTION OUTPUT ;
    USE SIGNAL ;
    PORT
      LAYER met3 ;
      RECT 999.320 238.190 1000.000 238.490 ;
    END
  END cfg_tph_st_mode[4]
  PIN cfg_tph_st_mode[5]
    DIRECTION OUTPUT ;
    USE SIGNAL ;
    PORT
      LAYER met3 ;
      RECT 999.320 239.550 1000.000 239.850 ;
    END
  END cfg_tph_st_mode[5]
  PIN cfg_tph_st_mode[6]
    DIRECTION OUTPUT ;
    USE SIGNAL ;
    PORT
      LAYER met3 ;
      RECT 999.320 240.910 1000.000 241.210 ;
    END
  END cfg_tph_st_mode[6]
  PIN cfg_tph_st_mode[7]
    DIRECTION OUTPUT ;
    USE SIGNAL ;
    PORT
      LAYER met3 ;
      RECT 999.320 242.270 1000.000 242.570 ;
    END
  END cfg_tph_st_mode[7]
  PIN cfg_tph_st_mode[8]
    DIRECTION OUTPUT ;
    USE SIGNAL ;
    PORT
      LAYER met3 ;
      RECT 999.320 243.630 1000.000 243.930 ;
    END
  END cfg_tph_st_mode[8]
  PIN cfg_tph_st_mode[9]
    DIRECTION OUTPUT ;
    USE SIGNAL ;
    PORT
      LAYER met3 ;
      RECT 999.320 244.990 1000.000 245.290 ;
    END
  END cfg_tph_st_mode[9]
  PIN cfg_tph_st_mode[10]
    DIRECTION OUTPUT ;
    USE SIGNAL ;
    PORT
      LAYER met3 ;
      RECT 999.320 246.350 1000.000 246.650 ;
    END
  END cfg_tph_st_mode[10]
  PIN cfg_tph_st_mode[11]
    DIRECTION OUTPUT ;
    USE SIGNAL ;
    PORT
      LAYER met3 ;
      RECT 999.320 247.710 1000.000 248.010 ;
    END
  END cfg_tph_st_mode[11]
  PIN cfg_vf_flr_in_process[0]
    DIRECTION OUTPUT ;
    USE SIGNAL ;
    PORT
      LAYER met3 ;
      RECT 999.320 249.070 1000.000 249.370 ;
    END
  END cfg_vf_flr_in_process[0]
  PIN cfg_vf_flr_in_process[1]
    DIRECTION OUTPUT ;
    USE SIGNAL ;
    PORT
      LAYER met3 ;
      RECT 999.320 250.430 1000.000 250.730 ;
    END
  END cfg_vf_flr_in_process[1]
  PIN cfg_vf_flr_in_process[2]
    DIRECTION OUTPUT ;
    USE SIGNAL ;
    PORT
      LAYER met3 ;
      RECT 999.320 251.790 1000.000 252.090 ;
    END
  END cfg_vf_flr_in_process[2]
  PIN cfg_vf_flr_in_process[3]
    DIRECTION OUTPUT ;
    USE SIGNAL ;
    PORT
      LAYER met3 ;
      RECT 999.320 253.150 1000.000 253.450 ;
    END
  END cfg_vf_flr_in_process[3]
  PIN cfg_vf_flr_in_process[4]
    DIRECTION OUTPUT ;
    USE SIGNAL ;
    PORT
      LAYER met3 ;
      RECT 999.320 254.510 1000.000 254.810 ;
    END
  END cfg_vf_flr_in_process[4]
  PIN cfg_vf_flr_in_process[5]
    DIRECTION OUTPUT ;
    USE SIGNAL ;
    PORT
      LAYER met3 ;
      RECT 999.320 255.870 1000.000 256.170 ;
    END
  END cfg_vf_flr_in_process[5]
  PIN cfg_vf_flr_in_process[6]
    DIRECTION OUTPUT ;
    USE SIGNAL ;
    PORT
      LAYER met3 ;
      RECT 999.320 257.230 1000.000 257.530 ;
    END
  END cfg_vf_flr_in_process[6]
  PIN cfg_vf_flr_in_process[7]
    DIRECTION OUTPUT ;
    USE SIGNAL ;
    PORT
      LAYER met3 ;
      RECT 999.320 258.590 1000.000 258.890 ;
    END
  END cfg_vf_flr_in_process[7]
  PIN int_qpll1lock_out
    DIRECTION OUTPUT ;
    USE SIGNAL ;
    PORT
      LAYER met3 ;
      RECT 999.320 259.950 1000.000 260.250 ;
    END
  END int_qpll1lock_out
  PIN int_qpll1outclk_out
    DIRECTION OUTPUT ;
    USE SIGNAL ;
    PORT
      LAYER met3 ;
      RECT 999.320 261.310 1000.000 261.610 ;
    END
  END int_qpll1outclk_out
  PIN int_qpll1outrefclk_out
    DIRECTION OUTPUT ;
    USE SIGNAL ;
    PORT
      LAYER met3 ;
      RECT 999.320 262.670 1000.000 262.970 ;
    END
  END int_qpll1outrefclk_out
  PIN m_axis_cq_tdata[0]
    DIRECTION OUTPUT ;
    USE SIGNAL ;
    PORT
      LAYER met3 ;
      RECT 999.320 264.030 1000.000 264.330 ;
    END
  END m_axis_cq_tdata[0]
  PIN m_axis_cq_tdata[1]
    DIRECTION OUTPUT ;
    USE SIGNAL ;
    PORT
      LAYER met3 ;
      RECT 999.320 265.390 1000.000 265.690 ;
    END
  END m_axis_cq_tdata[1]
  PIN m_axis_cq_tdata[2]
    DIRECTION OUTPUT ;
    USE SIGNAL ;
    PORT
      LAYER met3 ;
      RECT 999.320 266.750 1000.000 267.050 ;
    END
  END m_axis_cq_tdata[2]
  PIN m_axis_cq_tdata[3]
    DIRECTION OUTPUT ;
    USE SIGNAL ;
    PORT
      LAYER met3 ;
      RECT 999.320 268.110 1000.000 268.410 ;
    END
  END m_axis_cq_tdata[3]
  PIN m_axis_cq_tdata[4]
    DIRECTION OUTPUT ;
    USE SIGNAL ;
    PORT
      LAYER met3 ;
      RECT 999.320 269.470 1000.000 269.770 ;
    END
  END m_axis_cq_tdata[4]
  PIN m_axis_cq_tdata[5]
    DIRECTION OUTPUT ;
    USE SIGNAL ;
    PORT
      LAYER met3 ;
      RECT 999.320 270.830 1000.000 271.130 ;
    END
  END m_axis_cq_tdata[5]
  PIN m_axis_cq_tdata[6]
    DIRECTION OUTPUT ;
    USE SIGNAL ;
    PORT
      LAYER met3 ;
      RECT 999.320 272.190 1000.000 272.490 ;
    END
  END m_axis_cq_tdata[6]
  PIN m_axis_cq_tdata[7]
    DIRECTION OUTPUT ;
    USE SIGNAL ;
    PORT
      LAYER met3 ;
      RECT 999.320 273.550 1000.000 273.850 ;
    END
  END m_axis_cq_tdata[7]
  PIN m_axis_cq_tdata[8]
    DIRECTION OUTPUT ;
    USE SIGNAL ;
    PORT
      LAYER met3 ;
      RECT 999.320 274.910 1000.000 275.210 ;
    END
  END m_axis_cq_tdata[8]
  PIN m_axis_cq_tdata[9]
    DIRECTION OUTPUT ;
    USE SIGNAL ;
    PORT
      LAYER met3 ;
      RECT 999.320 276.270 1000.000 276.570 ;
    END
  END m_axis_cq_tdata[9]
  PIN m_axis_cq_tdata[10]
    DIRECTION OUTPUT ;
    USE SIGNAL ;
    PORT
      LAYER met3 ;
      RECT 999.320 277.630 1000.000 277.930 ;
    END
  END m_axis_cq_tdata[10]
  PIN m_axis_cq_tdata[11]
    DIRECTION OUTPUT ;
    USE SIGNAL ;
    PORT
      LAYER met3 ;
      RECT 999.320 278.990 1000.000 279.290 ;
    END
  END m_axis_cq_tdata[11]
  PIN m_axis_cq_tdata[12]
    DIRECTION OUTPUT ;
    USE SIGNAL ;
    PORT
      LAYER met3 ;
      RECT 999.320 280.350 1000.000 280.650 ;
    END
  END m_axis_cq_tdata[12]
  PIN m_axis_cq_tdata[13]
    DIRECTION OUTPUT ;
    USE SIGNAL ;
    PORT
      LAYER met3 ;
      RECT 999.320 281.710 1000.000 282.010 ;
    END
  END m_axis_cq_tdata[13]
  PIN m_axis_cq_tdata[14]
    DIRECTION OUTPUT ;
    USE SIGNAL ;
    PORT
      LAYER met3 ;
      RECT 999.320 283.070 1000.000 283.370 ;
    END
  END m_axis_cq_tdata[14]
  PIN m_axis_cq_tdata[15]
    DIRECTION OUTPUT ;
    USE SIGNAL ;
    PORT
      LAYER met3 ;
      RECT 999.320 284.430 1000.000 284.730 ;
    END
  END m_axis_cq_tdata[15]
  PIN m_axis_cq_tdata[16]
    DIRECTION OUTPUT ;
    USE SIGNAL ;
    PORT
      LAYER met3 ;
      RECT 999.320 285.790 1000.000 286.090 ;
    END
  END m_axis_cq_tdata[16]
  PIN m_axis_cq_tdata[17]
    DIRECTION OUTPUT ;
    USE SIGNAL ;
    PORT
      LAYER met3 ;
      RECT 999.320 287.150 1000.000 287.450 ;
    END
  END m_axis_cq_tdata[17]
  PIN m_axis_cq_tdata[18]
    DIRECTION OUTPUT ;
    USE SIGNAL ;
    PORT
      LAYER met3 ;
      RECT 999.320 288.510 1000.000 288.810 ;
    END
  END m_axis_cq_tdata[18]
  PIN m_axis_cq_tdata[19]
    DIRECTION OUTPUT ;
    USE SIGNAL ;
    PORT
      LAYER met3 ;
      RECT 999.320 289.870 1000.000 290.170 ;
    END
  END m_axis_cq_tdata[19]
  PIN m_axis_cq_tdata[20]
    DIRECTION OUTPUT ;
    USE SIGNAL ;
    PORT
      LAYER met3 ;
      RECT 999.320 291.230 1000.000 291.530 ;
    END
  END m_axis_cq_tdata[20]
  PIN m_axis_cq_tdata[21]
    DIRECTION OUTPUT ;
    USE SIGNAL ;
    PORT
      LAYER met3 ;
      RECT 999.320 292.590 1000.000 292.890 ;
    END
  END m_axis_cq_tdata[21]
  PIN m_axis_cq_tdata[22]
    DIRECTION OUTPUT ;
    USE SIGNAL ;
    PORT
      LAYER met3 ;
      RECT 999.320 293.950 1000.000 294.250 ;
    END
  END m_axis_cq_tdata[22]
  PIN m_axis_cq_tdata[23]
    DIRECTION OUTPUT ;
    USE SIGNAL ;
    PORT
      LAYER met3 ;
      RECT 999.320 295.310 1000.000 295.610 ;
    END
  END m_axis_cq_tdata[23]
  PIN m_axis_cq_tdata[24]
    DIRECTION OUTPUT ;
    USE SIGNAL ;
    PORT
      LAYER met3 ;
      RECT 999.320 296.670 1000.000 296.970 ;
    END
  END m_axis_cq_tdata[24]
  PIN m_axis_cq_tdata[25]
    DIRECTION OUTPUT ;
    USE SIGNAL ;
    PORT
      LAYER met3 ;
      RECT 999.320 298.030 1000.000 298.330 ;
    END
  END m_axis_cq_tdata[25]
  PIN m_axis_cq_tdata[26]
    DIRECTION OUTPUT ;
    USE SIGNAL ;
    PORT
      LAYER met3 ;
      RECT 999.320 299.390 1000.000 299.690 ;
    END
  END m_axis_cq_tdata[26]
  PIN m_axis_cq_tdata[27]
    DIRECTION OUTPUT ;
    USE SIGNAL ;
    PORT
      LAYER met3 ;
      RECT 999.320 300.750 1000.000 301.050 ;
    END
  END m_axis_cq_tdata[27]
  PIN m_axis_cq_tdata[28]
    DIRECTION OUTPUT ;
    USE SIGNAL ;
    PORT
      LAYER met3 ;
      RECT 999.320 302.110 1000.000 302.410 ;
    END
  END m_axis_cq_tdata[28]
  PIN m_axis_cq_tdata[29]
    DIRECTION OUTPUT ;
    USE SIGNAL ;
    PORT
      LAYER met3 ;
      RECT 999.320 303.470 1000.000 303.770 ;
    END
  END m_axis_cq_tdata[29]
  PIN m_axis_cq_tdata[30]
    DIRECTION OUTPUT ;
    USE SIGNAL ;
    PORT
      LAYER met3 ;
      RECT 999.320 304.830 1000.000 305.130 ;
    END
  END m_axis_cq_tdata[30]
  PIN m_axis_cq_tdata[31]
    DIRECTION OUTPUT ;
    USE SIGNAL ;
    PORT
      LAYER met3 ;
      RECT 999.320 306.190 1000.000 306.490 ;
    END
  END m_axis_cq_tdata[31]
  PIN m_axis_cq_tdata[32]
    DIRECTION OUTPUT ;
    USE SIGNAL ;
    PORT
      LAYER met3 ;
      RECT 999.320 307.550 1000.000 307.850 ;
    END
  END m_axis_cq_tdata[32]
  PIN m_axis_cq_tdata[33]
    DIRECTION OUTPUT ;
    USE SIGNAL ;
    PORT
      LAYER met3 ;
      RECT 999.320 308.910 1000.000 309.210 ;
    END
  END m_axis_cq_tdata[33]
  PIN m_axis_cq_tdata[34]
    DIRECTION OUTPUT ;
    USE SIGNAL ;
    PORT
      LAYER met3 ;
      RECT 999.320 310.270 1000.000 310.570 ;
    END
  END m_axis_cq_tdata[34]
  PIN m_axis_cq_tdata[35]
    DIRECTION OUTPUT ;
    USE SIGNAL ;
    PORT
      LAYER met3 ;
      RECT 999.320 311.630 1000.000 311.930 ;
    END
  END m_axis_cq_tdata[35]
  PIN m_axis_cq_tdata[36]
    DIRECTION OUTPUT ;
    USE SIGNAL ;
    PORT
      LAYER met3 ;
      RECT 999.320 312.990 1000.000 313.290 ;
    END
  END m_axis_cq_tdata[36]
  PIN m_axis_cq_tdata[37]
    DIRECTION OUTPUT ;
    USE SIGNAL ;
    PORT
      LAYER met3 ;
      RECT 999.320 314.350 1000.000 314.650 ;
    END
  END m_axis_cq_tdata[37]
  PIN m_axis_cq_tdata[38]
    DIRECTION OUTPUT ;
    USE SIGNAL ;
    PORT
      LAYER met3 ;
      RECT 999.320 315.710 1000.000 316.010 ;
    END
  END m_axis_cq_tdata[38]
  PIN m_axis_cq_tdata[39]
    DIRECTION OUTPUT ;
    USE SIGNAL ;
    PORT
      LAYER met3 ;
      RECT 999.320 317.070 1000.000 317.370 ;
    END
  END m_axis_cq_tdata[39]
  PIN m_axis_cq_tdata[40]
    DIRECTION OUTPUT ;
    USE SIGNAL ;
    PORT
      LAYER met3 ;
      RECT 999.320 318.430 1000.000 318.730 ;
    END
  END m_axis_cq_tdata[40]
  PIN m_axis_cq_tdata[41]
    DIRECTION OUTPUT ;
    USE SIGNAL ;
    PORT
      LAYER met3 ;
      RECT 999.320 319.790 1000.000 320.090 ;
    END
  END m_axis_cq_tdata[41]
  PIN m_axis_cq_tdata[42]
    DIRECTION OUTPUT ;
    USE SIGNAL ;
    PORT
      LAYER met3 ;
      RECT 999.320 321.150 1000.000 321.450 ;
    END
  END m_axis_cq_tdata[42]
  PIN m_axis_cq_tdata[43]
    DIRECTION OUTPUT ;
    USE SIGNAL ;
    PORT
      LAYER met3 ;
      RECT 999.320 322.510 1000.000 322.810 ;
    END
  END m_axis_cq_tdata[43]
  PIN m_axis_cq_tdata[44]
    DIRECTION OUTPUT ;
    USE SIGNAL ;
    PORT
      LAYER met3 ;
      RECT 999.320 323.870 1000.000 324.170 ;
    END
  END m_axis_cq_tdata[44]
  PIN m_axis_cq_tdata[45]
    DIRECTION OUTPUT ;
    USE SIGNAL ;
    PORT
      LAYER met3 ;
      RECT 999.320 325.230 1000.000 325.530 ;
    END
  END m_axis_cq_tdata[45]
  PIN m_axis_cq_tdata[46]
    DIRECTION OUTPUT ;
    USE SIGNAL ;
    PORT
      LAYER met3 ;
      RECT 999.320 326.590 1000.000 326.890 ;
    END
  END m_axis_cq_tdata[46]
  PIN m_axis_cq_tdata[47]
    DIRECTION OUTPUT ;
    USE SIGNAL ;
    PORT
      LAYER met3 ;
      RECT 999.320 327.950 1000.000 328.250 ;
    END
  END m_axis_cq_tdata[47]
  PIN m_axis_cq_tdata[48]
    DIRECTION OUTPUT ;
    USE SIGNAL ;
    PORT
      LAYER met3 ;
      RECT 999.320 329.310 1000.000 329.610 ;
    END
  END m_axis_cq_tdata[48]
  PIN m_axis_cq_tdata[49]
    DIRECTION OUTPUT ;
    USE SIGNAL ;
    PORT
      LAYER met3 ;
      RECT 999.320 330.670 1000.000 330.970 ;
    END
  END m_axis_cq_tdata[49]
  PIN m_axis_cq_tdata[50]
    DIRECTION OUTPUT ;
    USE SIGNAL ;
    PORT
      LAYER met3 ;
      RECT 999.320 332.030 1000.000 332.330 ;
    END
  END m_axis_cq_tdata[50]
  PIN m_axis_cq_tdata[51]
    DIRECTION OUTPUT ;
    USE SIGNAL ;
    PORT
      LAYER met3 ;
      RECT 999.320 333.390 1000.000 333.690 ;
    END
  END m_axis_cq_tdata[51]
  PIN m_axis_cq_tdata[52]
    DIRECTION OUTPUT ;
    USE SIGNAL ;
    PORT
      LAYER met3 ;
      RECT 999.320 334.750 1000.000 335.050 ;
    END
  END m_axis_cq_tdata[52]
  PIN m_axis_cq_tdata[53]
    DIRECTION OUTPUT ;
    USE SIGNAL ;
    PORT
      LAYER met3 ;
      RECT 999.320 336.110 1000.000 336.410 ;
    END
  END m_axis_cq_tdata[53]
  PIN m_axis_cq_tdata[54]
    DIRECTION OUTPUT ;
    USE SIGNAL ;
    PORT
      LAYER met3 ;
      RECT 999.320 337.470 1000.000 337.770 ;
    END
  END m_axis_cq_tdata[54]
  PIN m_axis_cq_tdata[55]
    DIRECTION OUTPUT ;
    USE SIGNAL ;
    PORT
      LAYER met3 ;
      RECT 999.320 338.830 1000.000 339.130 ;
    END
  END m_axis_cq_tdata[55]
  PIN m_axis_cq_tdata[56]
    DIRECTION OUTPUT ;
    USE SIGNAL ;
    PORT
      LAYER met3 ;
      RECT 999.320 340.190 1000.000 340.490 ;
    END
  END m_axis_cq_tdata[56]
  PIN m_axis_cq_tdata[57]
    DIRECTION OUTPUT ;
    USE SIGNAL ;
    PORT
      LAYER met3 ;
      RECT 999.320 341.550 1000.000 341.850 ;
    END
  END m_axis_cq_tdata[57]
  PIN m_axis_cq_tdata[58]
    DIRECTION OUTPUT ;
    USE SIGNAL ;
    PORT
      LAYER met3 ;
      RECT 999.320 342.910 1000.000 343.210 ;
    END
  END m_axis_cq_tdata[58]
  PIN m_axis_cq_tdata[59]
    DIRECTION OUTPUT ;
    USE SIGNAL ;
    PORT
      LAYER met3 ;
      RECT 999.320 344.270 1000.000 344.570 ;
    END
  END m_axis_cq_tdata[59]
  PIN m_axis_cq_tdata[60]
    DIRECTION OUTPUT ;
    USE SIGNAL ;
    PORT
      LAYER met3 ;
      RECT 999.320 345.630 1000.000 345.930 ;
    END
  END m_axis_cq_tdata[60]
  PIN m_axis_cq_tdata[61]
    DIRECTION OUTPUT ;
    USE SIGNAL ;
    PORT
      LAYER met3 ;
      RECT 999.320 346.990 1000.000 347.290 ;
    END
  END m_axis_cq_tdata[61]
  PIN m_axis_cq_tdata[62]
    DIRECTION OUTPUT ;
    USE SIGNAL ;
    PORT
      LAYER met3 ;
      RECT 999.320 348.350 1000.000 348.650 ;
    END
  END m_axis_cq_tdata[62]
  PIN m_axis_cq_tdata[63]
    DIRECTION OUTPUT ;
    USE SIGNAL ;
    PORT
      LAYER met3 ;
      RECT 999.320 349.710 1000.000 350.010 ;
    END
  END m_axis_cq_tdata[63]
  PIN m_axis_cq_tdata[64]
    DIRECTION OUTPUT ;
    USE SIGNAL ;
    PORT
      LAYER met3 ;
      RECT 999.320 351.070 1000.000 351.370 ;
    END
  END m_axis_cq_tdata[64]
  PIN m_axis_cq_tdata[65]
    DIRECTION OUTPUT ;
    USE SIGNAL ;
    PORT
      LAYER met3 ;
      RECT 999.320 352.430 1000.000 352.730 ;
    END
  END m_axis_cq_tdata[65]
  PIN m_axis_cq_tdata[66]
    DIRECTION OUTPUT ;
    USE SIGNAL ;
    PORT
      LAYER met3 ;
      RECT 999.320 353.790 1000.000 354.090 ;
    END
  END m_axis_cq_tdata[66]
  PIN m_axis_cq_tdata[67]
    DIRECTION OUTPUT ;
    USE SIGNAL ;
    PORT
      LAYER met3 ;
      RECT 999.320 355.150 1000.000 355.450 ;
    END
  END m_axis_cq_tdata[67]
  PIN m_axis_cq_tdata[68]
    DIRECTION OUTPUT ;
    USE SIGNAL ;
    PORT
      LAYER met3 ;
      RECT 999.320 356.510 1000.000 356.810 ;
    END
  END m_axis_cq_tdata[68]
  PIN m_axis_cq_tdata[69]
    DIRECTION OUTPUT ;
    USE SIGNAL ;
    PORT
      LAYER met3 ;
      RECT 999.320 357.870 1000.000 358.170 ;
    END
  END m_axis_cq_tdata[69]
  PIN m_axis_cq_tdata[70]
    DIRECTION OUTPUT ;
    USE SIGNAL ;
    PORT
      LAYER met3 ;
      RECT 999.320 359.230 1000.000 359.530 ;
    END
  END m_axis_cq_tdata[70]
  PIN m_axis_cq_tdata[71]
    DIRECTION OUTPUT ;
    USE SIGNAL ;
    PORT
      LAYER met3 ;
      RECT 999.320 360.590 1000.000 360.890 ;
    END
  END m_axis_cq_tdata[71]
  PIN m_axis_cq_tdata[72]
    DIRECTION OUTPUT ;
    USE SIGNAL ;
    PORT
      LAYER met3 ;
      RECT 999.320 361.950 1000.000 362.250 ;
    END
  END m_axis_cq_tdata[72]
  PIN m_axis_cq_tdata[73]
    DIRECTION OUTPUT ;
    USE SIGNAL ;
    PORT
      LAYER met3 ;
      RECT 999.320 363.310 1000.000 363.610 ;
    END
  END m_axis_cq_tdata[73]
  PIN m_axis_cq_tdata[74]
    DIRECTION OUTPUT ;
    USE SIGNAL ;
    PORT
      LAYER met3 ;
      RECT 999.320 364.670 1000.000 364.970 ;
    END
  END m_axis_cq_tdata[74]
  PIN m_axis_cq_tdata[75]
    DIRECTION OUTPUT ;
    USE SIGNAL ;
    PORT
      LAYER met3 ;
      RECT 999.320 366.030 1000.000 366.330 ;
    END
  END m_axis_cq_tdata[75]
  PIN m_axis_cq_tdata[76]
    DIRECTION OUTPUT ;
    USE SIGNAL ;
    PORT
      LAYER met3 ;
      RECT 999.320 367.390 1000.000 367.690 ;
    END
  END m_axis_cq_tdata[76]
  PIN m_axis_cq_tdata[77]
    DIRECTION OUTPUT ;
    USE SIGNAL ;
    PORT
      LAYER met3 ;
      RECT 999.320 368.750 1000.000 369.050 ;
    END
  END m_axis_cq_tdata[77]
  PIN m_axis_cq_tdata[78]
    DIRECTION OUTPUT ;
    USE SIGNAL ;
    PORT
      LAYER met3 ;
      RECT 999.320 370.110 1000.000 370.410 ;
    END
  END m_axis_cq_tdata[78]
  PIN m_axis_cq_tdata[79]
    DIRECTION OUTPUT ;
    USE SIGNAL ;
    PORT
      LAYER met3 ;
      RECT 999.320 371.470 1000.000 371.770 ;
    END
  END m_axis_cq_tdata[79]
  PIN m_axis_cq_tdata[80]
    DIRECTION OUTPUT ;
    USE SIGNAL ;
    PORT
      LAYER met3 ;
      RECT 999.320 372.830 1000.000 373.130 ;
    END
  END m_axis_cq_tdata[80]
  PIN m_axis_cq_tdata[81]
    DIRECTION OUTPUT ;
    USE SIGNAL ;
    PORT
      LAYER met3 ;
      RECT 999.320 374.190 1000.000 374.490 ;
    END
  END m_axis_cq_tdata[81]
  PIN m_axis_cq_tdata[82]
    DIRECTION OUTPUT ;
    USE SIGNAL ;
    PORT
      LAYER met3 ;
      RECT 999.320 375.550 1000.000 375.850 ;
    END
  END m_axis_cq_tdata[82]
  PIN m_axis_cq_tdata[83]
    DIRECTION OUTPUT ;
    USE SIGNAL ;
    PORT
      LAYER met3 ;
      RECT 999.320 376.910 1000.000 377.210 ;
    END
  END m_axis_cq_tdata[83]
  PIN m_axis_cq_tdata[84]
    DIRECTION OUTPUT ;
    USE SIGNAL ;
    PORT
      LAYER met3 ;
      RECT 999.320 378.270 1000.000 378.570 ;
    END
  END m_axis_cq_tdata[84]
  PIN m_axis_cq_tdata[85]
    DIRECTION OUTPUT ;
    USE SIGNAL ;
    PORT
      LAYER met3 ;
      RECT 999.320 379.630 1000.000 379.930 ;
    END
  END m_axis_cq_tdata[85]
  PIN m_axis_cq_tdata[86]
    DIRECTION OUTPUT ;
    USE SIGNAL ;
    PORT
      LAYER met3 ;
      RECT 999.320 380.990 1000.000 381.290 ;
    END
  END m_axis_cq_tdata[86]
  PIN m_axis_cq_tdata[87]
    DIRECTION OUTPUT ;
    USE SIGNAL ;
    PORT
      LAYER met3 ;
      RECT 999.320 382.350 1000.000 382.650 ;
    END
  END m_axis_cq_tdata[87]
  PIN m_axis_cq_tdata[88]
    DIRECTION OUTPUT ;
    USE SIGNAL ;
    PORT
      LAYER met3 ;
      RECT 999.320 383.710 1000.000 384.010 ;
    END
  END m_axis_cq_tdata[88]
  PIN m_axis_cq_tdata[89]
    DIRECTION OUTPUT ;
    USE SIGNAL ;
    PORT
      LAYER met3 ;
      RECT 999.320 385.070 1000.000 385.370 ;
    END
  END m_axis_cq_tdata[89]
  PIN m_axis_cq_tdata[90]
    DIRECTION OUTPUT ;
    USE SIGNAL ;
    PORT
      LAYER met3 ;
      RECT 999.320 386.430 1000.000 386.730 ;
    END
  END m_axis_cq_tdata[90]
  PIN m_axis_cq_tdata[91]
    DIRECTION OUTPUT ;
    USE SIGNAL ;
    PORT
      LAYER met3 ;
      RECT 999.320 387.790 1000.000 388.090 ;
    END
  END m_axis_cq_tdata[91]
  PIN m_axis_cq_tdata[92]
    DIRECTION OUTPUT ;
    USE SIGNAL ;
    PORT
      LAYER met3 ;
      RECT 999.320 389.150 1000.000 389.450 ;
    END
  END m_axis_cq_tdata[92]
  PIN m_axis_cq_tdata[93]
    DIRECTION OUTPUT ;
    USE SIGNAL ;
    PORT
      LAYER met3 ;
      RECT 999.320 390.510 1000.000 390.810 ;
    END
  END m_axis_cq_tdata[93]
  PIN m_axis_cq_tdata[94]
    DIRECTION OUTPUT ;
    USE SIGNAL ;
    PORT
      LAYER met3 ;
      RECT 999.320 391.870 1000.000 392.170 ;
    END
  END m_axis_cq_tdata[94]
  PIN m_axis_cq_tdata[95]
    DIRECTION OUTPUT ;
    USE SIGNAL ;
    PORT
      LAYER met3 ;
      RECT 999.320 393.230 1000.000 393.530 ;
    END
  END m_axis_cq_tdata[95]
  PIN m_axis_cq_tdata[96]
    DIRECTION OUTPUT ;
    USE SIGNAL ;
    PORT
      LAYER met3 ;
      RECT 999.320 394.590 1000.000 394.890 ;
    END
  END m_axis_cq_tdata[96]
  PIN m_axis_cq_tdata[97]
    DIRECTION OUTPUT ;
    USE SIGNAL ;
    PORT
      LAYER met3 ;
      RECT 999.320 395.950 1000.000 396.250 ;
    END
  END m_axis_cq_tdata[97]
  PIN m_axis_cq_tdata[98]
    DIRECTION OUTPUT ;
    USE SIGNAL ;
    PORT
      LAYER met3 ;
      RECT 999.320 397.310 1000.000 397.610 ;
    END
  END m_axis_cq_tdata[98]
  PIN m_axis_cq_tdata[99]
    DIRECTION OUTPUT ;
    USE SIGNAL ;
    PORT
      LAYER met3 ;
      RECT 999.320 398.670 1000.000 398.970 ;
    END
  END m_axis_cq_tdata[99]
  PIN m_axis_cq_tdata[100]
    DIRECTION OUTPUT ;
    USE SIGNAL ;
    PORT
      LAYER met3 ;
      RECT 999.320 400.030 1000.000 400.330 ;
    END
  END m_axis_cq_tdata[100]
  PIN m_axis_cq_tdata[101]
    DIRECTION OUTPUT ;
    USE SIGNAL ;
    PORT
      LAYER met3 ;
      RECT 999.320 401.390 1000.000 401.690 ;
    END
  END m_axis_cq_tdata[101]
  PIN m_axis_cq_tdata[102]
    DIRECTION OUTPUT ;
    USE SIGNAL ;
    PORT
      LAYER met3 ;
      RECT 999.320 402.750 1000.000 403.050 ;
    END
  END m_axis_cq_tdata[102]
  PIN m_axis_cq_tdata[103]
    DIRECTION OUTPUT ;
    USE SIGNAL ;
    PORT
      LAYER met3 ;
      RECT 999.320 404.110 1000.000 404.410 ;
    END
  END m_axis_cq_tdata[103]
  PIN m_axis_cq_tdata[104]
    DIRECTION OUTPUT ;
    USE SIGNAL ;
    PORT
      LAYER met3 ;
      RECT 999.320 405.470 1000.000 405.770 ;
    END
  END m_axis_cq_tdata[104]
  PIN m_axis_cq_tdata[105]
    DIRECTION OUTPUT ;
    USE SIGNAL ;
    PORT
      LAYER met3 ;
      RECT 999.320 406.830 1000.000 407.130 ;
    END
  END m_axis_cq_tdata[105]
  PIN m_axis_cq_tdata[106]
    DIRECTION OUTPUT ;
    USE SIGNAL ;
    PORT
      LAYER met3 ;
      RECT 999.320 408.190 1000.000 408.490 ;
    END
  END m_axis_cq_tdata[106]
  PIN m_axis_cq_tdata[107]
    DIRECTION OUTPUT ;
    USE SIGNAL ;
    PORT
      LAYER met3 ;
      RECT 999.320 409.550 1000.000 409.850 ;
    END
  END m_axis_cq_tdata[107]
  PIN m_axis_cq_tdata[108]
    DIRECTION OUTPUT ;
    USE SIGNAL ;
    PORT
      LAYER met3 ;
      RECT 999.320 410.910 1000.000 411.210 ;
    END
  END m_axis_cq_tdata[108]
  PIN m_axis_cq_tdata[109]
    DIRECTION OUTPUT ;
    USE SIGNAL ;
    PORT
      LAYER met3 ;
      RECT 999.320 412.270 1000.000 412.570 ;
    END
  END m_axis_cq_tdata[109]
  PIN m_axis_cq_tdata[110]
    DIRECTION OUTPUT ;
    USE SIGNAL ;
    PORT
      LAYER met3 ;
      RECT 999.320 413.630 1000.000 413.930 ;
    END
  END m_axis_cq_tdata[110]
  PIN m_axis_cq_tdata[111]
    DIRECTION OUTPUT ;
    USE SIGNAL ;
    PORT
      LAYER met3 ;
      RECT 999.320 414.990 1000.000 415.290 ;
    END
  END m_axis_cq_tdata[111]
  PIN m_axis_cq_tdata[112]
    DIRECTION OUTPUT ;
    USE SIGNAL ;
    PORT
      LAYER met3 ;
      RECT 999.320 416.350 1000.000 416.650 ;
    END
  END m_axis_cq_tdata[112]
  PIN m_axis_cq_tdata[113]
    DIRECTION OUTPUT ;
    USE SIGNAL ;
    PORT
      LAYER met3 ;
      RECT 999.320 417.710 1000.000 418.010 ;
    END
  END m_axis_cq_tdata[113]
  PIN m_axis_cq_tdata[114]
    DIRECTION OUTPUT ;
    USE SIGNAL ;
    PORT
      LAYER met3 ;
      RECT 999.320 419.070 1000.000 419.370 ;
    END
  END m_axis_cq_tdata[114]
  PIN m_axis_cq_tdata[115]
    DIRECTION OUTPUT ;
    USE SIGNAL ;
    PORT
      LAYER met3 ;
      RECT 999.320 420.430 1000.000 420.730 ;
    END
  END m_axis_cq_tdata[115]
  PIN m_axis_cq_tdata[116]
    DIRECTION OUTPUT ;
    USE SIGNAL ;
    PORT
      LAYER met3 ;
      RECT 999.320 421.790 1000.000 422.090 ;
    END
  END m_axis_cq_tdata[116]
  PIN m_axis_cq_tdata[117]
    DIRECTION OUTPUT ;
    USE SIGNAL ;
    PORT
      LAYER met3 ;
      RECT 999.320 423.150 1000.000 423.450 ;
    END
  END m_axis_cq_tdata[117]
  PIN m_axis_cq_tdata[118]
    DIRECTION OUTPUT ;
    USE SIGNAL ;
    PORT
      LAYER met3 ;
      RECT 999.320 424.510 1000.000 424.810 ;
    END
  END m_axis_cq_tdata[118]
  PIN m_axis_cq_tdata[119]
    DIRECTION OUTPUT ;
    USE SIGNAL ;
    PORT
      LAYER met3 ;
      RECT 999.320 425.870 1000.000 426.170 ;
    END
  END m_axis_cq_tdata[119]
  PIN m_axis_cq_tdata[120]
    DIRECTION OUTPUT ;
    USE SIGNAL ;
    PORT
      LAYER met3 ;
      RECT 999.320 427.230 1000.000 427.530 ;
    END
  END m_axis_cq_tdata[120]
  PIN m_axis_cq_tdata[121]
    DIRECTION OUTPUT ;
    USE SIGNAL ;
    PORT
      LAYER met3 ;
      RECT 999.320 428.590 1000.000 428.890 ;
    END
  END m_axis_cq_tdata[121]
  PIN m_axis_cq_tdata[122]
    DIRECTION OUTPUT ;
    USE SIGNAL ;
    PORT
      LAYER met3 ;
      RECT 999.320 429.950 1000.000 430.250 ;
    END
  END m_axis_cq_tdata[122]
  PIN m_axis_cq_tdata[123]
    DIRECTION OUTPUT ;
    USE SIGNAL ;
    PORT
      LAYER met3 ;
      RECT 999.320 431.310 1000.000 431.610 ;
    END
  END m_axis_cq_tdata[123]
  PIN m_axis_cq_tdata[124]
    DIRECTION OUTPUT ;
    USE SIGNAL ;
    PORT
      LAYER met3 ;
      RECT 999.320 432.670 1000.000 432.970 ;
    END
  END m_axis_cq_tdata[124]
  PIN m_axis_cq_tdata[125]
    DIRECTION OUTPUT ;
    USE SIGNAL ;
    PORT
      LAYER met3 ;
      RECT 999.320 434.030 1000.000 434.330 ;
    END
  END m_axis_cq_tdata[125]
  PIN m_axis_cq_tdata[126]
    DIRECTION OUTPUT ;
    USE SIGNAL ;
    PORT
      LAYER met3 ;
      RECT 999.320 435.390 1000.000 435.690 ;
    END
  END m_axis_cq_tdata[126]
  PIN m_axis_cq_tdata[127]
    DIRECTION OUTPUT ;
    USE SIGNAL ;
    PORT
      LAYER met3 ;
      RECT 999.320 436.750 1000.000 437.050 ;
    END
  END m_axis_cq_tdata[127]
  PIN m_axis_cq_tkeep[0]
    DIRECTION OUTPUT ;
    USE SIGNAL ;
    PORT
      LAYER met3 ;
      RECT 999.320 438.110 1000.000 438.410 ;
    END
  END m_axis_cq_tkeep[0]
  PIN m_axis_cq_tkeep[1]
    DIRECTION OUTPUT ;
    USE SIGNAL ;
    PORT
      LAYER met3 ;
      RECT 999.320 439.470 1000.000 439.770 ;
    END
  END m_axis_cq_tkeep[1]
  PIN m_axis_cq_tkeep[2]
    DIRECTION OUTPUT ;
    USE SIGNAL ;
    PORT
      LAYER met3 ;
      RECT 999.320 440.830 1000.000 441.130 ;
    END
  END m_axis_cq_tkeep[2]
  PIN m_axis_cq_tkeep[3]
    DIRECTION OUTPUT ;
    USE SIGNAL ;
    PORT
      LAYER met3 ;
      RECT 999.320 442.190 1000.000 442.490 ;
    END
  END m_axis_cq_tkeep[3]
  PIN m_axis_cq_tlast
    DIRECTION OUTPUT ;
    USE SIGNAL ;
    PORT
      LAYER met3 ;
      RECT 999.320 443.550 1000.000 443.850 ;
    END
  END m_axis_cq_tlast
  PIN m_axis_cq_tuser[0]
    DIRECTION OUTPUT ;
    USE SIGNAL ;
    PORT
      LAYER met3 ;
      RECT 999.320 444.910 1000.000 445.210 ;
    END
  END m_axis_cq_tuser[0]
  PIN m_axis_cq_tuser[1]
    DIRECTION OUTPUT ;
    USE SIGNAL ;
    PORT
      LAYER met3 ;
      RECT 999.320 446.270 1000.000 446.570 ;
    END
  END m_axis_cq_tuser[1]
  PIN m_axis_cq_tuser[2]
    DIRECTION OUTPUT ;
    USE SIGNAL ;
    PORT
      LAYER met3 ;
      RECT 999.320 447.630 1000.000 447.930 ;
    END
  END m_axis_cq_tuser[2]
  PIN m_axis_cq_tuser[3]
    DIRECTION OUTPUT ;
    USE SIGNAL ;
    PORT
      LAYER met3 ;
      RECT 999.320 448.990 1000.000 449.290 ;
    END
  END m_axis_cq_tuser[3]
  PIN m_axis_cq_tuser[4]
    DIRECTION OUTPUT ;
    USE SIGNAL ;
    PORT
      LAYER met3 ;
      RECT 999.320 450.350 1000.000 450.650 ;
    END
  END m_axis_cq_tuser[4]
  PIN m_axis_cq_tuser[5]
    DIRECTION OUTPUT ;
    USE SIGNAL ;
    PORT
      LAYER met3 ;
      RECT 999.320 451.710 1000.000 452.010 ;
    END
  END m_axis_cq_tuser[5]
  PIN m_axis_cq_tuser[6]
    DIRECTION OUTPUT ;
    USE SIGNAL ;
    PORT
      LAYER met3 ;
      RECT 999.320 453.070 1000.000 453.370 ;
    END
  END m_axis_cq_tuser[6]
  PIN m_axis_cq_tuser[7]
    DIRECTION OUTPUT ;
    USE SIGNAL ;
    PORT
      LAYER met3 ;
      RECT 999.320 454.430 1000.000 454.730 ;
    END
  END m_axis_cq_tuser[7]
  PIN m_axis_cq_tuser[8]
    DIRECTION OUTPUT ;
    USE SIGNAL ;
    PORT
      LAYER met3 ;
      RECT 999.320 455.790 1000.000 456.090 ;
    END
  END m_axis_cq_tuser[8]
  PIN m_axis_cq_tuser[9]
    DIRECTION OUTPUT ;
    USE SIGNAL ;
    PORT
      LAYER met3 ;
      RECT 999.320 457.150 1000.000 457.450 ;
    END
  END m_axis_cq_tuser[9]
  PIN m_axis_cq_tuser[10]
    DIRECTION OUTPUT ;
    USE SIGNAL ;
    PORT
      LAYER met3 ;
      RECT 999.320 458.510 1000.000 458.810 ;
    END
  END m_axis_cq_tuser[10]
  PIN m_axis_cq_tuser[11]
    DIRECTION OUTPUT ;
    USE SIGNAL ;
    PORT
      LAYER met3 ;
      RECT 999.320 459.870 1000.000 460.170 ;
    END
  END m_axis_cq_tuser[11]
  PIN m_axis_cq_tuser[12]
    DIRECTION OUTPUT ;
    USE SIGNAL ;
    PORT
      LAYER met3 ;
      RECT 999.320 461.230 1000.000 461.530 ;
    END
  END m_axis_cq_tuser[12]
  PIN m_axis_cq_tuser[13]
    DIRECTION OUTPUT ;
    USE SIGNAL ;
    PORT
      LAYER met3 ;
      RECT 999.320 462.590 1000.000 462.890 ;
    END
  END m_axis_cq_tuser[13]
  PIN m_axis_cq_tuser[14]
    DIRECTION OUTPUT ;
    USE SIGNAL ;
    PORT
      LAYER met3 ;
      RECT 999.320 463.950 1000.000 464.250 ;
    END
  END m_axis_cq_tuser[14]
  PIN m_axis_cq_tuser[15]
    DIRECTION OUTPUT ;
    USE SIGNAL ;
    PORT
      LAYER met3 ;
      RECT 999.320 465.310 1000.000 465.610 ;
    END
  END m_axis_cq_tuser[15]
  PIN m_axis_cq_tuser[16]
    DIRECTION OUTPUT ;
    USE SIGNAL ;
    PORT
      LAYER met3 ;
      RECT 999.320 466.670 1000.000 466.970 ;
    END
  END m_axis_cq_tuser[16]
  PIN m_axis_cq_tuser[17]
    DIRECTION OUTPUT ;
    USE SIGNAL ;
    PORT
      LAYER met3 ;
      RECT 999.320 468.030 1000.000 468.330 ;
    END
  END m_axis_cq_tuser[17]
  PIN m_axis_cq_tuser[18]
    DIRECTION OUTPUT ;
    USE SIGNAL ;
    PORT
      LAYER met3 ;
      RECT 999.320 469.390 1000.000 469.690 ;
    END
  END m_axis_cq_tuser[18]
  PIN m_axis_cq_tuser[19]
    DIRECTION OUTPUT ;
    USE SIGNAL ;
    PORT
      LAYER met3 ;
      RECT 999.320 470.750 1000.000 471.050 ;
    END
  END m_axis_cq_tuser[19]
  PIN m_axis_cq_tuser[20]
    DIRECTION OUTPUT ;
    USE SIGNAL ;
    PORT
      LAYER met3 ;
      RECT 999.320 472.110 1000.000 472.410 ;
    END
  END m_axis_cq_tuser[20]
  PIN m_axis_cq_tuser[21]
    DIRECTION OUTPUT ;
    USE SIGNAL ;
    PORT
      LAYER met3 ;
      RECT 999.320 473.470 1000.000 473.770 ;
    END
  END m_axis_cq_tuser[21]
  PIN m_axis_cq_tuser[22]
    DIRECTION OUTPUT ;
    USE SIGNAL ;
    PORT
      LAYER met3 ;
      RECT 999.320 474.830 1000.000 475.130 ;
    END
  END m_axis_cq_tuser[22]
  PIN m_axis_cq_tuser[23]
    DIRECTION OUTPUT ;
    USE SIGNAL ;
    PORT
      LAYER met3 ;
      RECT 999.320 476.190 1000.000 476.490 ;
    END
  END m_axis_cq_tuser[23]
  PIN m_axis_cq_tuser[24]
    DIRECTION OUTPUT ;
    USE SIGNAL ;
    PORT
      LAYER met3 ;
      RECT 999.320 477.550 1000.000 477.850 ;
    END
  END m_axis_cq_tuser[24]
  PIN m_axis_cq_tuser[25]
    DIRECTION OUTPUT ;
    USE SIGNAL ;
    PORT
      LAYER met3 ;
      RECT 999.320 478.910 1000.000 479.210 ;
    END
  END m_axis_cq_tuser[25]
  PIN m_axis_cq_tuser[26]
    DIRECTION OUTPUT ;
    USE SIGNAL ;
    PORT
      LAYER met3 ;
      RECT 999.320 480.270 1000.000 480.570 ;
    END
  END m_axis_cq_tuser[26]
  PIN m_axis_cq_tuser[27]
    DIRECTION OUTPUT ;
    USE SIGNAL ;
    PORT
      LAYER met3 ;
      RECT 999.320 481.630 1000.000 481.930 ;
    END
  END m_axis_cq_tuser[27]
  PIN m_axis_cq_tuser[28]
    DIRECTION OUTPUT ;
    USE SIGNAL ;
    PORT
      LAYER met3 ;
      RECT 999.320 482.990 1000.000 483.290 ;
    END
  END m_axis_cq_tuser[28]
  PIN m_axis_cq_tuser[29]
    DIRECTION OUTPUT ;
    USE SIGNAL ;
    PORT
      LAYER met3 ;
      RECT 999.320 484.350 1000.000 484.650 ;
    END
  END m_axis_cq_tuser[29]
  PIN m_axis_cq_tuser[30]
    DIRECTION OUTPUT ;
    USE SIGNAL ;
    PORT
      LAYER met3 ;
      RECT 999.320 485.710 1000.000 486.010 ;
    END
  END m_axis_cq_tuser[30]
  PIN m_axis_cq_tuser[31]
    DIRECTION OUTPUT ;
    USE SIGNAL ;
    PORT
      LAYER met3 ;
      RECT 999.320 487.070 1000.000 487.370 ;
    END
  END m_axis_cq_tuser[31]
  PIN m_axis_cq_tuser[32]
    DIRECTION OUTPUT ;
    USE SIGNAL ;
    PORT
      LAYER met3 ;
      RECT 999.320 488.430 1000.000 488.730 ;
    END
  END m_axis_cq_tuser[32]
  PIN m_axis_cq_tuser[33]
    DIRECTION OUTPUT ;
    USE SIGNAL ;
    PORT
      LAYER met3 ;
      RECT 999.320 489.790 1000.000 490.090 ;
    END
  END m_axis_cq_tuser[33]
  PIN m_axis_cq_tuser[34]
    DIRECTION OUTPUT ;
    USE SIGNAL ;
    PORT
      LAYER met3 ;
      RECT 999.320 491.150 1000.000 491.450 ;
    END
  END m_axis_cq_tuser[34]
  PIN m_axis_cq_tuser[35]
    DIRECTION OUTPUT ;
    USE SIGNAL ;
    PORT
      LAYER met3 ;
      RECT 999.320 492.510 1000.000 492.810 ;
    END
  END m_axis_cq_tuser[35]
  PIN m_axis_cq_tuser[36]
    DIRECTION OUTPUT ;
    USE SIGNAL ;
    PORT
      LAYER met3 ;
      RECT 999.320 493.870 1000.000 494.170 ;
    END
  END m_axis_cq_tuser[36]
  PIN m_axis_cq_tuser[37]
    DIRECTION OUTPUT ;
    USE SIGNAL ;
    PORT
      LAYER met3 ;
      RECT 999.320 495.230 1000.000 495.530 ;
    END
  END m_axis_cq_tuser[37]
  PIN m_axis_cq_tuser[38]
    DIRECTION OUTPUT ;
    USE SIGNAL ;
    PORT
      LAYER met3 ;
      RECT 999.320 496.590 1000.000 496.890 ;
    END
  END m_axis_cq_tuser[38]
  PIN m_axis_cq_tuser[39]
    DIRECTION OUTPUT ;
    USE SIGNAL ;
    PORT
      LAYER met3 ;
      RECT 999.320 497.950 1000.000 498.250 ;
    END
  END m_axis_cq_tuser[39]
  PIN m_axis_cq_tuser[40]
    DIRECTION OUTPUT ;
    USE SIGNAL ;
    PORT
      LAYER met3 ;
      RECT 999.320 499.310 1000.000 499.610 ;
    END
  END m_axis_cq_tuser[40]
  PIN m_axis_cq_tuser[41]
    DIRECTION OUTPUT ;
    USE SIGNAL ;
    PORT
      LAYER met3 ;
      RECT 999.320 500.670 1000.000 500.970 ;
    END
  END m_axis_cq_tuser[41]
  PIN m_axis_cq_tuser[42]
    DIRECTION OUTPUT ;
    USE SIGNAL ;
    PORT
      LAYER met3 ;
      RECT 999.320 502.030 1000.000 502.330 ;
    END
  END m_axis_cq_tuser[42]
  PIN m_axis_cq_tuser[43]
    DIRECTION OUTPUT ;
    USE SIGNAL ;
    PORT
      LAYER met3 ;
      RECT 999.320 503.390 1000.000 503.690 ;
    END
  END m_axis_cq_tuser[43]
  PIN m_axis_cq_tuser[44]
    DIRECTION OUTPUT ;
    USE SIGNAL ;
    PORT
      LAYER met3 ;
      RECT 999.320 504.750 1000.000 505.050 ;
    END
  END m_axis_cq_tuser[44]
  PIN m_axis_cq_tuser[45]
    DIRECTION OUTPUT ;
    USE SIGNAL ;
    PORT
      LAYER met3 ;
      RECT 999.320 506.110 1000.000 506.410 ;
    END
  END m_axis_cq_tuser[45]
  PIN m_axis_cq_tuser[46]
    DIRECTION OUTPUT ;
    USE SIGNAL ;
    PORT
      LAYER met3 ;
      RECT 999.320 507.470 1000.000 507.770 ;
    END
  END m_axis_cq_tuser[46]
  PIN m_axis_cq_tuser[47]
    DIRECTION OUTPUT ;
    USE SIGNAL ;
    PORT
      LAYER met3 ;
      RECT 999.320 508.830 1000.000 509.130 ;
    END
  END m_axis_cq_tuser[47]
  PIN m_axis_cq_tuser[48]
    DIRECTION OUTPUT ;
    USE SIGNAL ;
    PORT
      LAYER met3 ;
      RECT 999.320 510.190 1000.000 510.490 ;
    END
  END m_axis_cq_tuser[48]
  PIN m_axis_cq_tuser[49]
    DIRECTION OUTPUT ;
    USE SIGNAL ;
    PORT
      LAYER met3 ;
      RECT 999.320 511.550 1000.000 511.850 ;
    END
  END m_axis_cq_tuser[49]
  PIN m_axis_cq_tuser[50]
    DIRECTION OUTPUT ;
    USE SIGNAL ;
    PORT
      LAYER met3 ;
      RECT 999.320 512.230 1000.000 512.530 ;
    END
  END m_axis_cq_tuser[50]
  PIN m_axis_cq_tuser[51]
    DIRECTION OUTPUT ;
    USE SIGNAL ;
    PORT
      LAYER met3 ;
      RECT 999.320 514.270 1000.000 514.570 ;
    END
  END m_axis_cq_tuser[51]
  PIN m_axis_cq_tuser[52]
    DIRECTION OUTPUT ;
    USE SIGNAL ;
    PORT
      LAYER met3 ;
      RECT 999.320 515.630 1000.000 515.930 ;
    END
  END m_axis_cq_tuser[52]
  PIN m_axis_cq_tuser[53]
    DIRECTION OUTPUT ;
    USE SIGNAL ;
    PORT
      LAYER met3 ;
      RECT 999.320 516.990 1000.000 517.290 ;
    END
  END m_axis_cq_tuser[53]
  PIN m_axis_cq_tuser[54]
    DIRECTION OUTPUT ;
    USE SIGNAL ;
    PORT
      LAYER met3 ;
      RECT 999.320 518.350 1000.000 518.650 ;
    END
  END m_axis_cq_tuser[54]
  PIN m_axis_cq_tuser[55]
    DIRECTION OUTPUT ;
    USE SIGNAL ;
    PORT
      LAYER met3 ;
      RECT 999.320 519.710 1000.000 520.010 ;
    END
  END m_axis_cq_tuser[55]
  PIN m_axis_cq_tuser[56]
    DIRECTION OUTPUT ;
    USE SIGNAL ;
    PORT
      LAYER met3 ;
      RECT 999.320 521.070 1000.000 521.370 ;
    END
  END m_axis_cq_tuser[56]
  PIN m_axis_cq_tuser[57]
    DIRECTION OUTPUT ;
    USE SIGNAL ;
    PORT
      LAYER met3 ;
      RECT 999.320 521.750 1000.000 522.050 ;
    END
  END m_axis_cq_tuser[57]
  PIN m_axis_cq_tuser[58]
    DIRECTION OUTPUT ;
    USE SIGNAL ;
    PORT
      LAYER met3 ;
      RECT 999.320 523.110 1000.000 523.410 ;
    END
  END m_axis_cq_tuser[58]
  PIN m_axis_cq_tuser[59]
    DIRECTION OUTPUT ;
    USE SIGNAL ;
    PORT
      LAYER met3 ;
      RECT 999.320 525.150 1000.000 525.450 ;
    END
  END m_axis_cq_tuser[59]
  PIN m_axis_cq_tuser[60]
    DIRECTION OUTPUT ;
    USE SIGNAL ;
    PORT
      LAYER met3 ;
      RECT 999.320 526.510 1000.000 526.810 ;
    END
  END m_axis_cq_tuser[60]
  PIN m_axis_cq_tuser[61]
    DIRECTION OUTPUT ;
    USE SIGNAL ;
    PORT
      LAYER met3 ;
      RECT 999.320 527.870 1000.000 528.170 ;
    END
  END m_axis_cq_tuser[61]
  PIN m_axis_cq_tuser[62]
    DIRECTION OUTPUT ;
    USE SIGNAL ;
    PORT
      LAYER met3 ;
      RECT 999.320 529.230 1000.000 529.530 ;
    END
  END m_axis_cq_tuser[62]
  PIN m_axis_cq_tuser[63]
    DIRECTION OUTPUT ;
    USE SIGNAL ;
    PORT
      LAYER met3 ;
      RECT 999.320 530.590 1000.000 530.890 ;
    END
  END m_axis_cq_tuser[63]
  PIN m_axis_cq_tuser[64]
    DIRECTION OUTPUT ;
    USE SIGNAL ;
    PORT
      LAYER met3 ;
      RECT 999.320 531.950 1000.000 532.250 ;
    END
  END m_axis_cq_tuser[64]
  PIN m_axis_cq_tuser[65]
    DIRECTION OUTPUT ;
    USE SIGNAL ;
    PORT
      LAYER met3 ;
      RECT 999.320 533.310 1000.000 533.610 ;
    END
  END m_axis_cq_tuser[65]
  PIN m_axis_cq_tuser[66]
    DIRECTION OUTPUT ;
    USE SIGNAL ;
    PORT
      LAYER met3 ;
      RECT 999.320 533.990 1000.000 534.290 ;
    END
  END m_axis_cq_tuser[66]
  PIN m_axis_cq_tuser[67]
    DIRECTION OUTPUT ;
    USE SIGNAL ;
    PORT
      LAYER met3 ;
      RECT 999.320 536.030 1000.000 536.330 ;
    END
  END m_axis_cq_tuser[67]
  PIN m_axis_cq_tuser[68]
    DIRECTION OUTPUT ;
    USE SIGNAL ;
    PORT
      LAYER met3 ;
      RECT 999.320 537.390 1000.000 537.690 ;
    END
  END m_axis_cq_tuser[68]
  PIN m_axis_cq_tuser[69]
    DIRECTION OUTPUT ;
    USE SIGNAL ;
    PORT
      LAYER met3 ;
      RECT 999.320 538.750 1000.000 539.050 ;
    END
  END m_axis_cq_tuser[69]
  PIN m_axis_cq_tuser[70]
    DIRECTION OUTPUT ;
    USE SIGNAL ;
    PORT
      LAYER met3 ;
      RECT 999.320 540.110 1000.000 540.410 ;
    END
  END m_axis_cq_tuser[70]
  PIN m_axis_cq_tuser[71]
    DIRECTION OUTPUT ;
    USE SIGNAL ;
    PORT
      LAYER met3 ;
      RECT 999.320 541.470 1000.000 541.770 ;
    END
  END m_axis_cq_tuser[71]
  PIN m_axis_cq_tuser[72]
    DIRECTION OUTPUT ;
    USE SIGNAL ;
    PORT
      LAYER met3 ;
      RECT 999.320 542.830 1000.000 543.130 ;
    END
  END m_axis_cq_tuser[72]
  PIN m_axis_cq_tuser[73]
    DIRECTION OUTPUT ;
    USE SIGNAL ;
    PORT
      LAYER met3 ;
      RECT 999.320 544.190 1000.000 544.490 ;
    END
  END m_axis_cq_tuser[73]
  PIN m_axis_cq_tuser[74]
    DIRECTION OUTPUT ;
    USE SIGNAL ;
    PORT
      LAYER met3 ;
      RECT 999.320 544.870 1000.000 545.170 ;
    END
  END m_axis_cq_tuser[74]
  PIN m_axis_cq_tuser[75]
    DIRECTION OUTPUT ;
    USE SIGNAL ;
    PORT
      LAYER met3 ;
      RECT 999.320 546.230 1000.000 546.530 ;
    END
  END m_axis_cq_tuser[75]
  PIN m_axis_cq_tuser[76]
    DIRECTION OUTPUT ;
    USE SIGNAL ;
    PORT
      LAYER met3 ;
      RECT 999.320 548.270 1000.000 548.570 ;
    END
  END m_axis_cq_tuser[76]
  PIN m_axis_cq_tuser[77]
    DIRECTION OUTPUT ;
    USE SIGNAL ;
    PORT
      LAYER met3 ;
      RECT 999.320 549.630 1000.000 549.930 ;
    END
  END m_axis_cq_tuser[77]
  PIN m_axis_cq_tuser[78]
    DIRECTION OUTPUT ;
    USE SIGNAL ;
    PORT
      LAYER met3 ;
      RECT 999.320 550.990 1000.000 551.290 ;
    END
  END m_axis_cq_tuser[78]
  PIN m_axis_cq_tuser[79]
    DIRECTION OUTPUT ;
    USE SIGNAL ;
    PORT
      LAYER met3 ;
      RECT 999.320 552.350 1000.000 552.650 ;
    END
  END m_axis_cq_tuser[79]
  PIN m_axis_cq_tuser[80]
    DIRECTION OUTPUT ;
    USE SIGNAL ;
    PORT
      LAYER met3 ;
      RECT 999.320 553.710 1000.000 554.010 ;
    END
  END m_axis_cq_tuser[80]
  PIN m_axis_cq_tuser[81]
    DIRECTION OUTPUT ;
    USE SIGNAL ;
    PORT
      LAYER met3 ;
      RECT 999.320 555.070 1000.000 555.370 ;
    END
  END m_axis_cq_tuser[81]
  PIN m_axis_cq_tuser[82]
    DIRECTION OUTPUT ;
    USE SIGNAL ;
    PORT
      LAYER met3 ;
      RECT 999.320 556.430 1000.000 556.730 ;
    END
  END m_axis_cq_tuser[82]
  PIN m_axis_cq_tuser[83]
    DIRECTION OUTPUT ;
    USE SIGNAL ;
    PORT
      LAYER met3 ;
      RECT 999.320 557.110 1000.000 557.410 ;
    END
  END m_axis_cq_tuser[83]
  PIN m_axis_cq_tuser[84]
    DIRECTION OUTPUT ;
    USE SIGNAL ;
    PORT
      LAYER met3 ;
      RECT 999.320 559.150 1000.000 559.450 ;
    END
  END m_axis_cq_tuser[84]
  PIN m_axis_cq_tuser[85]
    DIRECTION OUTPUT ;
    USE SIGNAL ;
    PORT
      LAYER met3 ;
      RECT 999.320 560.510 1000.000 560.810 ;
    END
  END m_axis_cq_tuser[85]
  PIN m_axis_cq_tuser[86]
    DIRECTION OUTPUT ;
    USE SIGNAL ;
    PORT
      LAYER met3 ;
      RECT 999.320 561.870 1000.000 562.170 ;
    END
  END m_axis_cq_tuser[86]
  PIN m_axis_cq_tuser[87]
    DIRECTION OUTPUT ;
    USE SIGNAL ;
    PORT
      LAYER met3 ;
      RECT 999.320 563.230 1000.000 563.530 ;
    END
  END m_axis_cq_tuser[87]
  PIN m_axis_cq_tvalid
    DIRECTION OUTPUT ;
    USE SIGNAL ;
    PORT
      LAYER met3 ;
      RECT 999.320 564.590 1000.000 564.890 ;
    END
  END m_axis_cq_tvalid
  PIN m_axis_rc_tdata[0]
    DIRECTION OUTPUT ;
    USE SIGNAL ;
    PORT
      LAYER met3 ;
      RECT 999.320 565.950 1000.000 566.250 ;
    END
  END m_axis_rc_tdata[0]
  PIN m_axis_rc_tdata[1]
    DIRECTION OUTPUT ;
    USE SIGNAL ;
    PORT
      LAYER met3 ;
      RECT 999.320 567.310 1000.000 567.610 ;
    END
  END m_axis_rc_tdata[1]
  PIN m_axis_rc_tdata[2]
    DIRECTION OUTPUT ;
    USE SIGNAL ;
    PORT
      LAYER met3 ;
      RECT 999.320 567.990 1000.000 568.290 ;
    END
  END m_axis_rc_tdata[2]
  PIN m_axis_rc_tdata[3]
    DIRECTION OUTPUT ;
    USE SIGNAL ;
    PORT
      LAYER met3 ;
      RECT 999.320 569.350 1000.000 569.650 ;
    END
  END m_axis_rc_tdata[3]
  PIN m_axis_rc_tdata[4]
    DIRECTION OUTPUT ;
    USE SIGNAL ;
    PORT
      LAYER met3 ;
      RECT 999.320 571.390 1000.000 571.690 ;
    END
  END m_axis_rc_tdata[4]
  PIN m_axis_rc_tdata[5]
    DIRECTION OUTPUT ;
    USE SIGNAL ;
    PORT
      LAYER met3 ;
      RECT 999.320 572.750 1000.000 573.050 ;
    END
  END m_axis_rc_tdata[5]
  PIN m_axis_rc_tdata[6]
    DIRECTION OUTPUT ;
    USE SIGNAL ;
    PORT
      LAYER met3 ;
      RECT 999.320 574.110 1000.000 574.410 ;
    END
  END m_axis_rc_tdata[6]
  PIN m_axis_rc_tdata[7]
    DIRECTION OUTPUT ;
    USE SIGNAL ;
    PORT
      LAYER met3 ;
      RECT 999.320 575.470 1000.000 575.770 ;
    END
  END m_axis_rc_tdata[7]
  PIN m_axis_rc_tdata[8]
    DIRECTION OUTPUT ;
    USE SIGNAL ;
    PORT
      LAYER met3 ;
      RECT 999.320 576.830 1000.000 577.130 ;
    END
  END m_axis_rc_tdata[8]
  PIN m_axis_rc_tdata[9]
    DIRECTION OUTPUT ;
    USE SIGNAL ;
    PORT
      LAYER met3 ;
      RECT 999.320 578.190 1000.000 578.490 ;
    END
  END m_axis_rc_tdata[9]
  PIN m_axis_rc_tdata[10]
    DIRECTION OUTPUT ;
    USE SIGNAL ;
    PORT
      LAYER met3 ;
      RECT 999.320 578.870 1000.000 579.170 ;
    END
  END m_axis_rc_tdata[10]
  PIN m_axis_rc_tdata[11]
    DIRECTION OUTPUT ;
    USE SIGNAL ;
    PORT
      LAYER met3 ;
      RECT 999.320 580.230 1000.000 580.530 ;
    END
  END m_axis_rc_tdata[11]
  PIN m_axis_rc_tdata[12]
    DIRECTION OUTPUT ;
    USE SIGNAL ;
    PORT
      LAYER met3 ;
      RECT 999.320 582.270 1000.000 582.570 ;
    END
  END m_axis_rc_tdata[12]
  PIN m_axis_rc_tdata[13]
    DIRECTION OUTPUT ;
    USE SIGNAL ;
    PORT
      LAYER met3 ;
      RECT 999.320 583.630 1000.000 583.930 ;
    END
  END m_axis_rc_tdata[13]
  PIN m_axis_rc_tdata[14]
    DIRECTION OUTPUT ;
    USE SIGNAL ;
    PORT
      LAYER met3 ;
      RECT 999.320 584.990 1000.000 585.290 ;
    END
  END m_axis_rc_tdata[14]
  PIN m_axis_rc_tdata[15]
    DIRECTION OUTPUT ;
    USE SIGNAL ;
    PORT
      LAYER met3 ;
      RECT 999.320 586.350 1000.000 586.650 ;
    END
  END m_axis_rc_tdata[15]
  PIN m_axis_rc_tdata[16]
    DIRECTION OUTPUT ;
    USE SIGNAL ;
    PORT
      LAYER met3 ;
      RECT 999.320 587.710 1000.000 588.010 ;
    END
  END m_axis_rc_tdata[16]
  PIN m_axis_rc_tdata[17]
    DIRECTION OUTPUT ;
    USE SIGNAL ;
    PORT
      LAYER met3 ;
      RECT 999.320 589.070 1000.000 589.370 ;
    END
  END m_axis_rc_tdata[17]
  PIN m_axis_rc_tdata[18]
    DIRECTION OUTPUT ;
    USE SIGNAL ;
    PORT
      LAYER met3 ;
      RECT 999.320 590.430 1000.000 590.730 ;
    END
  END m_axis_rc_tdata[18]
  PIN m_axis_rc_tdata[19]
    DIRECTION OUTPUT ;
    USE SIGNAL ;
    PORT
      LAYER met3 ;
      RECT 999.320 591.110 1000.000 591.410 ;
    END
  END m_axis_rc_tdata[19]
  PIN m_axis_rc_tdata[20]
    DIRECTION OUTPUT ;
    USE SIGNAL ;
    PORT
      LAYER met3 ;
      RECT 999.320 593.150 1000.000 593.450 ;
    END
  END m_axis_rc_tdata[20]
  PIN m_axis_rc_tdata[21]
    DIRECTION OUTPUT ;
    USE SIGNAL ;
    PORT
      LAYER met3 ;
      RECT 999.320 594.510 1000.000 594.810 ;
    END
  END m_axis_rc_tdata[21]
  PIN m_axis_rc_tdata[22]
    DIRECTION OUTPUT ;
    USE SIGNAL ;
    PORT
      LAYER met3 ;
      RECT 999.320 595.870 1000.000 596.170 ;
    END
  END m_axis_rc_tdata[22]
  PIN m_axis_rc_tdata[23]
    DIRECTION OUTPUT ;
    USE SIGNAL ;
    PORT
      LAYER met3 ;
      RECT 999.320 597.230 1000.000 597.530 ;
    END
  END m_axis_rc_tdata[23]
  PIN m_axis_rc_tdata[24]
    DIRECTION OUTPUT ;
    USE SIGNAL ;
    PORT
      LAYER met3 ;
      RECT 999.320 598.590 1000.000 598.890 ;
    END
  END m_axis_rc_tdata[24]
  PIN m_axis_rc_tdata[25]
    DIRECTION OUTPUT ;
    USE SIGNAL ;
    PORT
      LAYER met3 ;
      RECT 999.320 599.950 1000.000 600.250 ;
    END
  END m_axis_rc_tdata[25]
  PIN m_axis_rc_tdata[26]
    DIRECTION OUTPUT ;
    USE SIGNAL ;
    PORT
      LAYER met3 ;
      RECT 999.320 601.310 1000.000 601.610 ;
    END
  END m_axis_rc_tdata[26]
  PIN m_axis_rc_tdata[27]
    DIRECTION OUTPUT ;
    USE SIGNAL ;
    PORT
      LAYER met3 ;
      RECT 999.320 601.990 1000.000 602.290 ;
    END
  END m_axis_rc_tdata[27]
  PIN m_axis_rc_tdata[28]
    DIRECTION OUTPUT ;
    USE SIGNAL ;
    PORT
      LAYER met3 ;
      RECT 999.320 603.350 1000.000 603.650 ;
    END
  END m_axis_rc_tdata[28]
  PIN m_axis_rc_tdata[29]
    DIRECTION OUTPUT ;
    USE SIGNAL ;
    PORT
      LAYER met3 ;
      RECT 999.320 605.390 1000.000 605.690 ;
    END
  END m_axis_rc_tdata[29]
  PIN m_axis_rc_tdata[30]
    DIRECTION OUTPUT ;
    USE SIGNAL ;
    PORT
      LAYER met3 ;
      RECT 999.320 606.750 1000.000 607.050 ;
    END
  END m_axis_rc_tdata[30]
  PIN m_axis_rc_tdata[31]
    DIRECTION OUTPUT ;
    USE SIGNAL ;
    PORT
      LAYER met3 ;
      RECT 999.320 608.110 1000.000 608.410 ;
    END
  END m_axis_rc_tdata[31]
  PIN m_axis_rc_tdata[32]
    DIRECTION OUTPUT ;
    USE SIGNAL ;
    PORT
      LAYER met3 ;
      RECT 999.320 609.470 1000.000 609.770 ;
    END
  END m_axis_rc_tdata[32]
  PIN m_axis_rc_tdata[33]
    DIRECTION OUTPUT ;
    USE SIGNAL ;
    PORT
      LAYER met3 ;
      RECT 999.320 610.830 1000.000 611.130 ;
    END
  END m_axis_rc_tdata[33]
  PIN m_axis_rc_tdata[34]
    DIRECTION OUTPUT ;
    USE SIGNAL ;
    PORT
      LAYER met3 ;
      RECT 999.320 612.190 1000.000 612.490 ;
    END
  END m_axis_rc_tdata[34]
  PIN m_axis_rc_tdata[35]
    DIRECTION OUTPUT ;
    USE SIGNAL ;
    PORT
      LAYER met3 ;
      RECT 999.320 613.550 1000.000 613.850 ;
    END
  END m_axis_rc_tdata[35]
  PIN m_axis_rc_tdata[36]
    DIRECTION OUTPUT ;
    USE SIGNAL ;
    PORT
      LAYER met3 ;
      RECT 999.320 614.230 1000.000 614.530 ;
    END
  END m_axis_rc_tdata[36]
  PIN m_axis_rc_tdata[37]
    DIRECTION OUTPUT ;
    USE SIGNAL ;
    PORT
      LAYER met3 ;
      RECT 999.320 616.270 1000.000 616.570 ;
    END
  END m_axis_rc_tdata[37]
  PIN m_axis_rc_tdata[38]
    DIRECTION OUTPUT ;
    USE SIGNAL ;
    PORT
      LAYER met3 ;
      RECT 999.320 617.630 1000.000 617.930 ;
    END
  END m_axis_rc_tdata[38]
  PIN m_axis_rc_tdata[39]
    DIRECTION OUTPUT ;
    USE SIGNAL ;
    PORT
      LAYER met3 ;
      RECT 999.320 618.990 1000.000 619.290 ;
    END
  END m_axis_rc_tdata[39]
  PIN m_axis_rc_tdata[40]
    DIRECTION OUTPUT ;
    USE SIGNAL ;
    PORT
      LAYER met3 ;
      RECT 999.320 620.350 1000.000 620.650 ;
    END
  END m_axis_rc_tdata[40]
  PIN m_axis_rc_tdata[41]
    DIRECTION OUTPUT ;
    USE SIGNAL ;
    PORT
      LAYER met3 ;
      RECT 999.320 621.710 1000.000 622.010 ;
    END
  END m_axis_rc_tdata[41]
  PIN m_axis_rc_tdata[42]
    DIRECTION OUTPUT ;
    USE SIGNAL ;
    PORT
      LAYER met3 ;
      RECT 999.320 623.070 1000.000 623.370 ;
    END
  END m_axis_rc_tdata[42]
  PIN m_axis_rc_tdata[43]
    DIRECTION OUTPUT ;
    USE SIGNAL ;
    PORT
      LAYER met3 ;
      RECT 999.320 624.430 1000.000 624.730 ;
    END
  END m_axis_rc_tdata[43]
  PIN m_axis_rc_tdata[44]
    DIRECTION OUTPUT ;
    USE SIGNAL ;
    PORT
      LAYER met3 ;
      RECT 999.320 625.110 1000.000 625.410 ;
    END
  END m_axis_rc_tdata[44]
  PIN m_axis_rc_tdata[45]
    DIRECTION OUTPUT ;
    USE SIGNAL ;
    PORT
      LAYER met3 ;
      RECT 999.320 626.470 1000.000 626.770 ;
    END
  END m_axis_rc_tdata[45]
  PIN m_axis_rc_tdata[46]
    DIRECTION OUTPUT ;
    USE SIGNAL ;
    PORT
      LAYER met3 ;
      RECT 999.320 628.510 1000.000 628.810 ;
    END
  END m_axis_rc_tdata[46]
  PIN m_axis_rc_tdata[47]
    DIRECTION OUTPUT ;
    USE SIGNAL ;
    PORT
      LAYER met3 ;
      RECT 999.320 629.870 1000.000 630.170 ;
    END
  END m_axis_rc_tdata[47]
  PIN m_axis_rc_tdata[48]
    DIRECTION OUTPUT ;
    USE SIGNAL ;
    PORT
      LAYER met3 ;
      RECT 999.320 631.230 1000.000 631.530 ;
    END
  END m_axis_rc_tdata[48]
  PIN m_axis_rc_tdata[49]
    DIRECTION OUTPUT ;
    USE SIGNAL ;
    PORT
      LAYER met3 ;
      RECT 999.320 632.590 1000.000 632.890 ;
    END
  END m_axis_rc_tdata[49]
  PIN m_axis_rc_tdata[50]
    DIRECTION OUTPUT ;
    USE SIGNAL ;
    PORT
      LAYER met3 ;
      RECT 999.320 633.950 1000.000 634.250 ;
    END
  END m_axis_rc_tdata[50]
  PIN m_axis_rc_tdata[51]
    DIRECTION OUTPUT ;
    USE SIGNAL ;
    PORT
      LAYER met3 ;
      RECT 999.320 635.310 1000.000 635.610 ;
    END
  END m_axis_rc_tdata[51]
  PIN m_axis_rc_tdata[52]
    DIRECTION OUTPUT ;
    USE SIGNAL ;
    PORT
      LAYER met3 ;
      RECT 999.320 635.990 1000.000 636.290 ;
    END
  END m_axis_rc_tdata[52]
  PIN m_axis_rc_tdata[53]
    DIRECTION OUTPUT ;
    USE SIGNAL ;
    PORT
      LAYER met3 ;
      RECT 999.320 637.350 1000.000 637.650 ;
    END
  END m_axis_rc_tdata[53]
  PIN m_axis_rc_tdata[54]
    DIRECTION OUTPUT ;
    USE SIGNAL ;
    PORT
      LAYER met3 ;
      RECT 999.320 639.390 1000.000 639.690 ;
    END
  END m_axis_rc_tdata[54]
  PIN m_axis_rc_tdata[55]
    DIRECTION OUTPUT ;
    USE SIGNAL ;
    PORT
      LAYER met3 ;
      RECT 999.320 640.750 1000.000 641.050 ;
    END
  END m_axis_rc_tdata[55]
  PIN m_axis_rc_tdata[56]
    DIRECTION OUTPUT ;
    USE SIGNAL ;
    PORT
      LAYER met3 ;
      RECT 999.320 642.110 1000.000 642.410 ;
    END
  END m_axis_rc_tdata[56]
  PIN m_axis_rc_tdata[57]
    DIRECTION OUTPUT ;
    USE SIGNAL ;
    PORT
      LAYER met3 ;
      RECT 999.320 643.470 1000.000 643.770 ;
    END
  END m_axis_rc_tdata[57]
  PIN m_axis_rc_tdata[58]
    DIRECTION OUTPUT ;
    USE SIGNAL ;
    PORT
      LAYER met3 ;
      RECT 999.320 644.830 1000.000 645.130 ;
    END
  END m_axis_rc_tdata[58]
  PIN m_axis_rc_tdata[59]
    DIRECTION OUTPUT ;
    USE SIGNAL ;
    PORT
      LAYER met3 ;
      RECT 999.320 646.190 1000.000 646.490 ;
    END
  END m_axis_rc_tdata[59]
  PIN m_axis_rc_tdata[60]
    DIRECTION OUTPUT ;
    USE SIGNAL ;
    PORT
      LAYER met3 ;
      RECT 999.320 647.550 1000.000 647.850 ;
    END
  END m_axis_rc_tdata[60]
  PIN m_axis_rc_tdata[61]
    DIRECTION OUTPUT ;
    USE SIGNAL ;
    PORT
      LAYER met3 ;
      RECT 999.320 648.230 1000.000 648.530 ;
    END
  END m_axis_rc_tdata[61]
  PIN m_axis_rc_tdata[62]
    DIRECTION OUTPUT ;
    USE SIGNAL ;
    PORT
      LAYER met3 ;
      RECT 999.320 650.270 1000.000 650.570 ;
    END
  END m_axis_rc_tdata[62]
  PIN m_axis_rc_tdata[63]
    DIRECTION OUTPUT ;
    USE SIGNAL ;
    PORT
      LAYER met3 ;
      RECT 999.320 651.630 1000.000 651.930 ;
    END
  END m_axis_rc_tdata[63]
  PIN m_axis_rc_tdata[64]
    DIRECTION OUTPUT ;
    USE SIGNAL ;
    PORT
      LAYER met3 ;
      RECT 999.320 652.990 1000.000 653.290 ;
    END
  END m_axis_rc_tdata[64]
  PIN m_axis_rc_tdata[65]
    DIRECTION OUTPUT ;
    USE SIGNAL ;
    PORT
      LAYER met3 ;
      RECT 999.320 654.350 1000.000 654.650 ;
    END
  END m_axis_rc_tdata[65]
  PIN m_axis_rc_tdata[66]
    DIRECTION OUTPUT ;
    USE SIGNAL ;
    PORT
      LAYER met3 ;
      RECT 999.320 655.710 1000.000 656.010 ;
    END
  END m_axis_rc_tdata[66]
  PIN m_axis_rc_tdata[67]
    DIRECTION OUTPUT ;
    USE SIGNAL ;
    PORT
      LAYER met3 ;
      RECT 999.320 657.070 1000.000 657.370 ;
    END
  END m_axis_rc_tdata[67]
  PIN m_axis_rc_tdata[68]
    DIRECTION OUTPUT ;
    USE SIGNAL ;
    PORT
      LAYER met3 ;
      RECT 999.320 658.430 1000.000 658.730 ;
    END
  END m_axis_rc_tdata[68]
  PIN m_axis_rc_tdata[69]
    DIRECTION OUTPUT ;
    USE SIGNAL ;
    PORT
      LAYER met3 ;
      RECT 999.320 659.110 1000.000 659.410 ;
    END
  END m_axis_rc_tdata[69]
  PIN m_axis_rc_tdata[70]
    DIRECTION OUTPUT ;
    USE SIGNAL ;
    PORT
      LAYER met3 ;
      RECT 999.320 660.470 1000.000 660.770 ;
    END
  END m_axis_rc_tdata[70]
  PIN m_axis_rc_tdata[71]
    DIRECTION OUTPUT ;
    USE SIGNAL ;
    PORT
      LAYER met3 ;
      RECT 999.320 662.510 1000.000 662.810 ;
    END
  END m_axis_rc_tdata[71]
  PIN m_axis_rc_tdata[72]
    DIRECTION OUTPUT ;
    USE SIGNAL ;
    PORT
      LAYER met3 ;
      RECT 999.320 663.870 1000.000 664.170 ;
    END
  END m_axis_rc_tdata[72]
  PIN m_axis_rc_tdata[73]
    DIRECTION OUTPUT ;
    USE SIGNAL ;
    PORT
      LAYER met3 ;
      RECT 999.320 665.230 1000.000 665.530 ;
    END
  END m_axis_rc_tdata[73]
  PIN m_axis_rc_tdata[74]
    DIRECTION OUTPUT ;
    USE SIGNAL ;
    PORT
      LAYER met3 ;
      RECT 999.320 666.590 1000.000 666.890 ;
    END
  END m_axis_rc_tdata[74]
  PIN m_axis_rc_tdata[75]
    DIRECTION OUTPUT ;
    USE SIGNAL ;
    PORT
      LAYER met3 ;
      RECT 999.320 667.950 1000.000 668.250 ;
    END
  END m_axis_rc_tdata[75]
  PIN m_axis_rc_tdata[76]
    DIRECTION OUTPUT ;
    USE SIGNAL ;
    PORT
      LAYER met3 ;
      RECT 999.320 669.310 1000.000 669.610 ;
    END
  END m_axis_rc_tdata[76]
  PIN m_axis_rc_tdata[77]
    DIRECTION OUTPUT ;
    USE SIGNAL ;
    PORT
      LAYER met3 ;
      RECT 999.320 670.670 1000.000 670.970 ;
    END
  END m_axis_rc_tdata[77]
  PIN m_axis_rc_tdata[78]
    DIRECTION OUTPUT ;
    USE SIGNAL ;
    PORT
      LAYER met3 ;
      RECT 999.320 671.350 1000.000 671.650 ;
    END
  END m_axis_rc_tdata[78]
  PIN m_axis_rc_tdata[79]
    DIRECTION OUTPUT ;
    USE SIGNAL ;
    PORT
      LAYER met3 ;
      RECT 999.320 673.390 1000.000 673.690 ;
    END
  END m_axis_rc_tdata[79]
  PIN m_axis_rc_tdata[80]
    DIRECTION OUTPUT ;
    USE SIGNAL ;
    PORT
      LAYER met3 ;
      RECT 999.320 674.750 1000.000 675.050 ;
    END
  END m_axis_rc_tdata[80]
  PIN m_axis_rc_tdata[81]
    DIRECTION OUTPUT ;
    USE SIGNAL ;
    PORT
      LAYER met3 ;
      RECT 999.320 676.110 1000.000 676.410 ;
    END
  END m_axis_rc_tdata[81]
  PIN m_axis_rc_tdata[82]
    DIRECTION OUTPUT ;
    USE SIGNAL ;
    PORT
      LAYER met3 ;
      RECT 999.320 677.470 1000.000 677.770 ;
    END
  END m_axis_rc_tdata[82]
  PIN m_axis_rc_tdata[83]
    DIRECTION OUTPUT ;
    USE SIGNAL ;
    PORT
      LAYER met3 ;
      RECT 999.320 678.830 1000.000 679.130 ;
    END
  END m_axis_rc_tdata[83]
  PIN m_axis_rc_tdata[84]
    DIRECTION OUTPUT ;
    USE SIGNAL ;
    PORT
      LAYER met3 ;
      RECT 999.320 680.190 1000.000 680.490 ;
    END
  END m_axis_rc_tdata[84]
  PIN m_axis_rc_tdata[85]
    DIRECTION OUTPUT ;
    USE SIGNAL ;
    PORT
      LAYER met3 ;
      RECT 999.320 681.550 1000.000 681.850 ;
    END
  END m_axis_rc_tdata[85]
  PIN m_axis_rc_tdata[86]
    DIRECTION OUTPUT ;
    USE SIGNAL ;
    PORT
      LAYER met3 ;
      RECT 999.320 682.230 1000.000 682.530 ;
    END
  END m_axis_rc_tdata[86]
  PIN m_axis_rc_tdata[87]
    DIRECTION OUTPUT ;
    USE SIGNAL ;
    PORT
      LAYER met3 ;
      RECT 999.320 683.590 1000.000 683.890 ;
    END
  END m_axis_rc_tdata[87]
  PIN m_axis_rc_tdata[88]
    DIRECTION OUTPUT ;
    USE SIGNAL ;
    PORT
      LAYER met3 ;
      RECT 999.320 685.630 1000.000 685.930 ;
    END
  END m_axis_rc_tdata[88]
  PIN m_axis_rc_tdata[89]
    DIRECTION OUTPUT ;
    USE SIGNAL ;
    PORT
      LAYER met3 ;
      RECT 999.320 686.990 1000.000 687.290 ;
    END
  END m_axis_rc_tdata[89]
  PIN m_axis_rc_tdata[90]
    DIRECTION OUTPUT ;
    USE SIGNAL ;
    PORT
      LAYER met3 ;
      RECT 999.320 688.350 1000.000 688.650 ;
    END
  END m_axis_rc_tdata[90]
  PIN m_axis_rc_tdata[91]
    DIRECTION OUTPUT ;
    USE SIGNAL ;
    PORT
      LAYER met3 ;
      RECT 999.320 689.710 1000.000 690.010 ;
    END
  END m_axis_rc_tdata[91]
  PIN m_axis_rc_tdata[92]
    DIRECTION OUTPUT ;
    USE SIGNAL ;
    PORT
      LAYER met3 ;
      RECT 999.320 691.070 1000.000 691.370 ;
    END
  END m_axis_rc_tdata[92]
  PIN m_axis_rc_tdata[93]
    DIRECTION OUTPUT ;
    USE SIGNAL ;
    PORT
      LAYER met3 ;
      RECT 999.320 692.430 1000.000 692.730 ;
    END
  END m_axis_rc_tdata[93]
  PIN m_axis_rc_tdata[94]
    DIRECTION OUTPUT ;
    USE SIGNAL ;
    PORT
      LAYER met3 ;
      RECT 999.320 693.110 1000.000 693.410 ;
    END
  END m_axis_rc_tdata[94]
  PIN m_axis_rc_tdata[95]
    DIRECTION OUTPUT ;
    USE SIGNAL ;
    PORT
      LAYER met3 ;
      RECT 999.320 694.470 1000.000 694.770 ;
    END
  END m_axis_rc_tdata[95]
  PIN m_axis_rc_tdata[96]
    DIRECTION OUTPUT ;
    USE SIGNAL ;
    PORT
      LAYER met3 ;
      RECT 999.320 696.510 1000.000 696.810 ;
    END
  END m_axis_rc_tdata[96]
  PIN m_axis_rc_tdata[97]
    DIRECTION OUTPUT ;
    USE SIGNAL ;
    PORT
      LAYER met3 ;
      RECT 999.320 697.870 1000.000 698.170 ;
    END
  END m_axis_rc_tdata[97]
  PIN m_axis_rc_tdata[98]
    DIRECTION OUTPUT ;
    USE SIGNAL ;
    PORT
      LAYER met3 ;
      RECT 999.320 699.230 1000.000 699.530 ;
    END
  END m_axis_rc_tdata[98]
  PIN m_axis_rc_tdata[99]
    DIRECTION OUTPUT ;
    USE SIGNAL ;
    PORT
      LAYER met3 ;
      RECT 999.320 700.590 1000.000 700.890 ;
    END
  END m_axis_rc_tdata[99]
  PIN m_axis_rc_tdata[100]
    DIRECTION OUTPUT ;
    USE SIGNAL ;
    PORT
      LAYER met3 ;
      RECT 999.320 701.950 1000.000 702.250 ;
    END
  END m_axis_rc_tdata[100]
  PIN m_axis_rc_tdata[101]
    DIRECTION OUTPUT ;
    USE SIGNAL ;
    PORT
      LAYER met3 ;
      RECT 999.320 703.310 1000.000 703.610 ;
    END
  END m_axis_rc_tdata[101]
  PIN m_axis_rc_tdata[102]
    DIRECTION OUTPUT ;
    USE SIGNAL ;
    PORT
      LAYER met3 ;
      RECT 999.320 704.670 1000.000 704.970 ;
    END
  END m_axis_rc_tdata[102]
  PIN m_axis_rc_tdata[103]
    DIRECTION OUTPUT ;
    USE SIGNAL ;
    PORT
      LAYER met3 ;
      RECT 999.320 706.030 1000.000 706.330 ;
    END
  END m_axis_rc_tdata[103]
  PIN m_axis_rc_tdata[104]
    DIRECTION OUTPUT ;
    USE SIGNAL ;
    PORT
      LAYER met3 ;
      RECT 999.320 707.390 1000.000 707.690 ;
    END
  END m_axis_rc_tdata[104]
  PIN m_axis_rc_tdata[105]
    DIRECTION OUTPUT ;
    USE SIGNAL ;
    PORT
      LAYER met3 ;
      RECT 999.320 708.750 1000.000 709.050 ;
    END
  END m_axis_rc_tdata[105]
  PIN m_axis_rc_tdata[106]
    DIRECTION OUTPUT ;
    USE SIGNAL ;
    PORT
      LAYER met3 ;
      RECT 999.320 710.110 1000.000 710.410 ;
    END
  END m_axis_rc_tdata[106]
  PIN m_axis_rc_tdata[107]
    DIRECTION OUTPUT ;
    USE SIGNAL ;
    PORT
      LAYER met3 ;
      RECT 999.320 711.470 1000.000 711.770 ;
    END
  END m_axis_rc_tdata[107]
  PIN m_axis_rc_tdata[108]
    DIRECTION OUTPUT ;
    USE SIGNAL ;
    PORT
      LAYER met3 ;
      RECT 999.320 712.830 1000.000 713.130 ;
    END
  END m_axis_rc_tdata[108]
  PIN m_axis_rc_tdata[109]
    DIRECTION OUTPUT ;
    USE SIGNAL ;
    PORT
      LAYER met3 ;
      RECT 999.320 714.190 1000.000 714.490 ;
    END
  END m_axis_rc_tdata[109]
  PIN m_axis_rc_tdata[110]
    DIRECTION OUTPUT ;
    USE SIGNAL ;
    PORT
      LAYER met3 ;
      RECT 999.320 715.550 1000.000 715.850 ;
    END
  END m_axis_rc_tdata[110]
  PIN m_axis_rc_tdata[111]
    DIRECTION OUTPUT ;
    USE SIGNAL ;
    PORT
      LAYER met3 ;
      RECT 999.320 716.910 1000.000 717.210 ;
    END
  END m_axis_rc_tdata[111]
  PIN m_axis_rc_tdata[112]
    DIRECTION OUTPUT ;
    USE SIGNAL ;
    PORT
      LAYER met3 ;
      RECT 999.320 718.270 1000.000 718.570 ;
    END
  END m_axis_rc_tdata[112]
  PIN m_axis_rc_tdata[113]
    DIRECTION OUTPUT ;
    USE SIGNAL ;
    PORT
      LAYER met3 ;
      RECT 999.320 719.630 1000.000 719.930 ;
    END
  END m_axis_rc_tdata[113]
  PIN m_axis_rc_tdata[114]
    DIRECTION OUTPUT ;
    USE SIGNAL ;
    PORT
      LAYER met3 ;
      RECT 999.320 720.990 1000.000 721.290 ;
    END
  END m_axis_rc_tdata[114]
  PIN m_axis_rc_tdata[115]
    DIRECTION OUTPUT ;
    USE SIGNAL ;
    PORT
      LAYER met3 ;
      RECT 999.320 722.350 1000.000 722.650 ;
    END
  END m_axis_rc_tdata[115]
  PIN m_axis_rc_tdata[116]
    DIRECTION OUTPUT ;
    USE SIGNAL ;
    PORT
      LAYER met3 ;
      RECT 999.320 723.710 1000.000 724.010 ;
    END
  END m_axis_rc_tdata[116]
  PIN m_axis_rc_tdata[117]
    DIRECTION OUTPUT ;
    USE SIGNAL ;
    PORT
      LAYER met3 ;
      RECT 999.320 725.070 1000.000 725.370 ;
    END
  END m_axis_rc_tdata[117]
  PIN m_axis_rc_tdata[118]
    DIRECTION OUTPUT ;
    USE SIGNAL ;
    PORT
      LAYER met3 ;
      RECT 999.320 726.430 1000.000 726.730 ;
    END
  END m_axis_rc_tdata[118]
  PIN m_axis_rc_tdata[119]
    DIRECTION OUTPUT ;
    USE SIGNAL ;
    PORT
      LAYER met3 ;
      RECT 999.320 727.790 1000.000 728.090 ;
    END
  END m_axis_rc_tdata[119]
  PIN m_axis_rc_tdata[120]
    DIRECTION OUTPUT ;
    USE SIGNAL ;
    PORT
      LAYER met3 ;
      RECT 999.320 729.150 1000.000 729.450 ;
    END
  END m_axis_rc_tdata[120]
  PIN m_axis_rc_tdata[121]
    DIRECTION OUTPUT ;
    USE SIGNAL ;
    PORT
      LAYER met3 ;
      RECT 999.320 730.510 1000.000 730.810 ;
    END
  END m_axis_rc_tdata[121]
  PIN m_axis_rc_tdata[122]
    DIRECTION OUTPUT ;
    USE SIGNAL ;
    PORT
      LAYER met3 ;
      RECT 999.320 731.870 1000.000 732.170 ;
    END
  END m_axis_rc_tdata[122]
  PIN m_axis_rc_tdata[123]
    DIRECTION OUTPUT ;
    USE SIGNAL ;
    PORT
      LAYER met3 ;
      RECT 999.320 733.230 1000.000 733.530 ;
    END
  END m_axis_rc_tdata[123]
  PIN m_axis_rc_tdata[124]
    DIRECTION OUTPUT ;
    USE SIGNAL ;
    PORT
      LAYER met3 ;
      RECT 999.320 734.590 1000.000 734.890 ;
    END
  END m_axis_rc_tdata[124]
  PIN m_axis_rc_tdata[125]
    DIRECTION OUTPUT ;
    USE SIGNAL ;
    PORT
      LAYER met3 ;
      RECT 999.320 735.950 1000.000 736.250 ;
    END
  END m_axis_rc_tdata[125]
  PIN m_axis_rc_tdata[126]
    DIRECTION OUTPUT ;
    USE SIGNAL ;
    PORT
      LAYER met3 ;
      RECT 999.320 737.310 1000.000 737.610 ;
    END
  END m_axis_rc_tdata[126]
  PIN m_axis_rc_tdata[127]
    DIRECTION OUTPUT ;
    USE SIGNAL ;
    PORT
      LAYER met3 ;
      RECT 999.320 738.670 1000.000 738.970 ;
    END
  END m_axis_rc_tdata[127]
  PIN m_axis_rc_tkeep[0]
    DIRECTION OUTPUT ;
    USE SIGNAL ;
    PORT
      LAYER met3 ;
      RECT 999.320 740.030 1000.000 740.330 ;
    END
  END m_axis_rc_tkeep[0]
  PIN m_axis_rc_tkeep[1]
    DIRECTION OUTPUT ;
    USE SIGNAL ;
    PORT
      LAYER met3 ;
      RECT 999.320 741.390 1000.000 741.690 ;
    END
  END m_axis_rc_tkeep[1]
  PIN m_axis_rc_tkeep[2]
    DIRECTION OUTPUT ;
    USE SIGNAL ;
    PORT
      LAYER met3 ;
      RECT 999.320 742.750 1000.000 743.050 ;
    END
  END m_axis_rc_tkeep[2]
  PIN m_axis_rc_tkeep[3]
    DIRECTION OUTPUT ;
    USE SIGNAL ;
    PORT
      LAYER met3 ;
      RECT 999.320 744.110 1000.000 744.410 ;
    END
  END m_axis_rc_tkeep[3]
  PIN m_axis_rc_tlast
    DIRECTION OUTPUT ;
    USE SIGNAL ;
    PORT
      LAYER met3 ;
      RECT 999.320 745.470 1000.000 745.770 ;
    END
  END m_axis_rc_tlast
  PIN m_axis_rc_tuser[0]
    DIRECTION OUTPUT ;
    USE SIGNAL ;
    PORT
      LAYER met3 ;
      RECT 999.320 746.830 1000.000 747.130 ;
    END
  END m_axis_rc_tuser[0]
  PIN m_axis_rc_tuser[1]
    DIRECTION OUTPUT ;
    USE SIGNAL ;
    PORT
      LAYER met3 ;
      RECT 999.320 748.190 1000.000 748.490 ;
    END
  END m_axis_rc_tuser[1]
  PIN m_axis_rc_tuser[2]
    DIRECTION OUTPUT ;
    USE SIGNAL ;
    PORT
      LAYER met3 ;
      RECT 999.320 749.550 1000.000 749.850 ;
    END
  END m_axis_rc_tuser[2]
  PIN m_axis_rc_tuser[3]
    DIRECTION OUTPUT ;
    USE SIGNAL ;
    PORT
      LAYER met3 ;
      RECT 999.320 750.910 1000.000 751.210 ;
    END
  END m_axis_rc_tuser[3]
  PIN m_axis_rc_tuser[4]
    DIRECTION OUTPUT ;
    USE SIGNAL ;
    PORT
      LAYER met3 ;
      RECT 999.320 752.270 1000.000 752.570 ;
    END
  END m_axis_rc_tuser[4]
  PIN m_axis_rc_tuser[5]
    DIRECTION OUTPUT ;
    USE SIGNAL ;
    PORT
      LAYER met3 ;
      RECT 999.320 753.630 1000.000 753.930 ;
    END
  END m_axis_rc_tuser[5]
  PIN m_axis_rc_tuser[6]
    DIRECTION OUTPUT ;
    USE SIGNAL ;
    PORT
      LAYER met3 ;
      RECT 999.320 754.990 1000.000 755.290 ;
    END
  END m_axis_rc_tuser[6]
  PIN m_axis_rc_tuser[7]
    DIRECTION OUTPUT ;
    USE SIGNAL ;
    PORT
      LAYER met3 ;
      RECT 999.320 756.350 1000.000 756.650 ;
    END
  END m_axis_rc_tuser[7]
  PIN m_axis_rc_tuser[8]
    DIRECTION OUTPUT ;
    USE SIGNAL ;
    PORT
      LAYER met3 ;
      RECT 999.320 757.710 1000.000 758.010 ;
    END
  END m_axis_rc_tuser[8]
  PIN m_axis_rc_tuser[9]
    DIRECTION OUTPUT ;
    USE SIGNAL ;
    PORT
      LAYER met3 ;
      RECT 999.320 759.070 1000.000 759.370 ;
    END
  END m_axis_rc_tuser[9]
  PIN m_axis_rc_tuser[10]
    DIRECTION OUTPUT ;
    USE SIGNAL ;
    PORT
      LAYER met3 ;
      RECT 999.320 760.430 1000.000 760.730 ;
    END
  END m_axis_rc_tuser[10]
  PIN m_axis_rc_tuser[11]
    DIRECTION OUTPUT ;
    USE SIGNAL ;
    PORT
      LAYER met3 ;
      RECT 999.320 761.790 1000.000 762.090 ;
    END
  END m_axis_rc_tuser[11]
  PIN m_axis_rc_tuser[12]
    DIRECTION OUTPUT ;
    USE SIGNAL ;
    PORT
      LAYER met3 ;
      RECT 999.320 763.150 1000.000 763.450 ;
    END
  END m_axis_rc_tuser[12]
  PIN m_axis_rc_tuser[13]
    DIRECTION OUTPUT ;
    USE SIGNAL ;
    PORT
      LAYER met3 ;
      RECT 999.320 764.510 1000.000 764.810 ;
    END
  END m_axis_rc_tuser[13]
  PIN m_axis_rc_tuser[14]
    DIRECTION OUTPUT ;
    USE SIGNAL ;
    PORT
      LAYER met3 ;
      RECT 999.320 765.870 1000.000 766.170 ;
    END
  END m_axis_rc_tuser[14]
  PIN m_axis_rc_tuser[15]
    DIRECTION OUTPUT ;
    USE SIGNAL ;
    PORT
      LAYER met3 ;
      RECT 999.320 767.230 1000.000 767.530 ;
    END
  END m_axis_rc_tuser[15]
  PIN m_axis_rc_tuser[16]
    DIRECTION OUTPUT ;
    USE SIGNAL ;
    PORT
      LAYER met3 ;
      RECT 999.320 768.590 1000.000 768.890 ;
    END
  END m_axis_rc_tuser[16]
  PIN m_axis_rc_tuser[17]
    DIRECTION OUTPUT ;
    USE SIGNAL ;
    PORT
      LAYER met3 ;
      RECT 999.320 769.950 1000.000 770.250 ;
    END
  END m_axis_rc_tuser[17]
  PIN m_axis_rc_tuser[18]
    DIRECTION OUTPUT ;
    USE SIGNAL ;
    PORT
      LAYER met3 ;
      RECT 999.320 771.310 1000.000 771.610 ;
    END
  END m_axis_rc_tuser[18]
  PIN m_axis_rc_tuser[19]
    DIRECTION OUTPUT ;
    USE SIGNAL ;
    PORT
      LAYER met3 ;
      RECT 999.320 772.670 1000.000 772.970 ;
    END
  END m_axis_rc_tuser[19]
  PIN m_axis_rc_tuser[20]
    DIRECTION OUTPUT ;
    USE SIGNAL ;
    PORT
      LAYER met3 ;
      RECT 999.320 774.030 1000.000 774.330 ;
    END
  END m_axis_rc_tuser[20]
  PIN m_axis_rc_tuser[21]
    DIRECTION OUTPUT ;
    USE SIGNAL ;
    PORT
      LAYER met3 ;
      RECT 999.320 775.390 1000.000 775.690 ;
    END
  END m_axis_rc_tuser[21]
  PIN m_axis_rc_tuser[22]
    DIRECTION OUTPUT ;
    USE SIGNAL ;
    PORT
      LAYER met3 ;
      RECT 999.320 776.750 1000.000 777.050 ;
    END
  END m_axis_rc_tuser[22]
  PIN m_axis_rc_tuser[23]
    DIRECTION OUTPUT ;
    USE SIGNAL ;
    PORT
      LAYER met3 ;
      RECT 999.320 778.110 1000.000 778.410 ;
    END
  END m_axis_rc_tuser[23]
  PIN m_axis_rc_tuser[24]
    DIRECTION OUTPUT ;
    USE SIGNAL ;
    PORT
      LAYER met3 ;
      RECT 999.320 779.470 1000.000 779.770 ;
    END
  END m_axis_rc_tuser[24]
  PIN m_axis_rc_tuser[25]
    DIRECTION OUTPUT ;
    USE SIGNAL ;
    PORT
      LAYER met3 ;
      RECT 999.320 780.830 1000.000 781.130 ;
    END
  END m_axis_rc_tuser[25]
  PIN m_axis_rc_tuser[26]
    DIRECTION OUTPUT ;
    USE SIGNAL ;
    PORT
      LAYER met3 ;
      RECT 999.320 782.190 1000.000 782.490 ;
    END
  END m_axis_rc_tuser[26]
  PIN m_axis_rc_tuser[27]
    DIRECTION OUTPUT ;
    USE SIGNAL ;
    PORT
      LAYER met3 ;
      RECT 999.320 783.550 1000.000 783.850 ;
    END
  END m_axis_rc_tuser[27]
  PIN m_axis_rc_tuser[28]
    DIRECTION OUTPUT ;
    USE SIGNAL ;
    PORT
      LAYER met3 ;
      RECT 999.320 784.910 1000.000 785.210 ;
    END
  END m_axis_rc_tuser[28]
  PIN m_axis_rc_tuser[29]
    DIRECTION OUTPUT ;
    USE SIGNAL ;
    PORT
      LAYER met3 ;
      RECT 999.320 786.270 1000.000 786.570 ;
    END
  END m_axis_rc_tuser[29]
  PIN m_axis_rc_tuser[30]
    DIRECTION OUTPUT ;
    USE SIGNAL ;
    PORT
      LAYER met3 ;
      RECT 999.320 787.630 1000.000 787.930 ;
    END
  END m_axis_rc_tuser[30]
  PIN m_axis_rc_tuser[31]
    DIRECTION OUTPUT ;
    USE SIGNAL ;
    PORT
      LAYER met3 ;
      RECT 999.320 788.990 1000.000 789.290 ;
    END
  END m_axis_rc_tuser[31]
  PIN m_axis_rc_tuser[32]
    DIRECTION OUTPUT ;
    USE SIGNAL ;
    PORT
      LAYER met3 ;
      RECT 999.320 790.350 1000.000 790.650 ;
    END
  END m_axis_rc_tuser[32]
  PIN m_axis_rc_tuser[33]
    DIRECTION OUTPUT ;
    USE SIGNAL ;
    PORT
      LAYER met3 ;
      RECT 999.320 791.710 1000.000 792.010 ;
    END
  END m_axis_rc_tuser[33]
  PIN m_axis_rc_tuser[34]
    DIRECTION OUTPUT ;
    USE SIGNAL ;
    PORT
      LAYER met3 ;
      RECT 999.320 793.070 1000.000 793.370 ;
    END
  END m_axis_rc_tuser[34]
  PIN m_axis_rc_tuser[35]
    DIRECTION OUTPUT ;
    USE SIGNAL ;
    PORT
      LAYER met3 ;
      RECT 999.320 794.430 1000.000 794.730 ;
    END
  END m_axis_rc_tuser[35]
  PIN m_axis_rc_tuser[36]
    DIRECTION OUTPUT ;
    USE SIGNAL ;
    PORT
      LAYER met3 ;
      RECT 999.320 795.790 1000.000 796.090 ;
    END
  END m_axis_rc_tuser[36]
  PIN m_axis_rc_tuser[37]
    DIRECTION OUTPUT ;
    USE SIGNAL ;
    PORT
      LAYER met3 ;
      RECT 999.320 797.150 1000.000 797.450 ;
    END
  END m_axis_rc_tuser[37]
  PIN m_axis_rc_tuser[38]
    DIRECTION OUTPUT ;
    USE SIGNAL ;
    PORT
      LAYER met3 ;
      RECT 999.320 798.510 1000.000 798.810 ;
    END
  END m_axis_rc_tuser[38]
  PIN m_axis_rc_tuser[39]
    DIRECTION OUTPUT ;
    USE SIGNAL ;
    PORT
      LAYER met3 ;
      RECT 999.320 799.870 1000.000 800.170 ;
    END
  END m_axis_rc_tuser[39]
  PIN m_axis_rc_tuser[40]
    DIRECTION OUTPUT ;
    USE SIGNAL ;
    PORT
      LAYER met3 ;
      RECT 999.320 801.230 1000.000 801.530 ;
    END
  END m_axis_rc_tuser[40]
  PIN m_axis_rc_tuser[41]
    DIRECTION OUTPUT ;
    USE SIGNAL ;
    PORT
      LAYER met3 ;
      RECT 999.320 802.590 1000.000 802.890 ;
    END
  END m_axis_rc_tuser[41]
  PIN m_axis_rc_tuser[42]
    DIRECTION OUTPUT ;
    USE SIGNAL ;
    PORT
      LAYER met3 ;
      RECT 999.320 803.950 1000.000 804.250 ;
    END
  END m_axis_rc_tuser[42]
  PIN m_axis_rc_tuser[43]
    DIRECTION OUTPUT ;
    USE SIGNAL ;
    PORT
      LAYER met3 ;
      RECT 999.320 805.310 1000.000 805.610 ;
    END
  END m_axis_rc_tuser[43]
  PIN m_axis_rc_tuser[44]
    DIRECTION OUTPUT ;
    USE SIGNAL ;
    PORT
      LAYER met3 ;
      RECT 999.320 806.670 1000.000 806.970 ;
    END
  END m_axis_rc_tuser[44]
  PIN m_axis_rc_tuser[45]
    DIRECTION OUTPUT ;
    USE SIGNAL ;
    PORT
      LAYER met3 ;
      RECT 999.320 808.030 1000.000 808.330 ;
    END
  END m_axis_rc_tuser[45]
  PIN m_axis_rc_tuser[46]
    DIRECTION OUTPUT ;
    USE SIGNAL ;
    PORT
      LAYER met3 ;
      RECT 999.320 809.390 1000.000 809.690 ;
    END
  END m_axis_rc_tuser[46]
  PIN m_axis_rc_tuser[47]
    DIRECTION OUTPUT ;
    USE SIGNAL ;
    PORT
      LAYER met3 ;
      RECT 999.320 810.750 1000.000 811.050 ;
    END
  END m_axis_rc_tuser[47]
  PIN m_axis_rc_tuser[48]
    DIRECTION OUTPUT ;
    USE SIGNAL ;
    PORT
      LAYER met3 ;
      RECT 999.320 812.110 1000.000 812.410 ;
    END
  END m_axis_rc_tuser[48]
  PIN m_axis_rc_tuser[49]
    DIRECTION OUTPUT ;
    USE SIGNAL ;
    PORT
      LAYER met3 ;
      RECT 999.320 813.470 1000.000 813.770 ;
    END
  END m_axis_rc_tuser[49]
  PIN m_axis_rc_tuser[50]
    DIRECTION OUTPUT ;
    USE SIGNAL ;
    PORT
      LAYER met3 ;
      RECT 999.320 814.830 1000.000 815.130 ;
    END
  END m_axis_rc_tuser[50]
  PIN m_axis_rc_tuser[51]
    DIRECTION OUTPUT ;
    USE SIGNAL ;
    PORT
      LAYER met3 ;
      RECT 999.320 816.190 1000.000 816.490 ;
    END
  END m_axis_rc_tuser[51]
  PIN m_axis_rc_tuser[52]
    DIRECTION OUTPUT ;
    USE SIGNAL ;
    PORT
      LAYER met3 ;
      RECT 999.320 817.550 1000.000 817.850 ;
    END
  END m_axis_rc_tuser[52]
  PIN m_axis_rc_tuser[53]
    DIRECTION OUTPUT ;
    USE SIGNAL ;
    PORT
      LAYER met3 ;
      RECT 999.320 818.910 1000.000 819.210 ;
    END
  END m_axis_rc_tuser[53]
  PIN m_axis_rc_tuser[54]
    DIRECTION OUTPUT ;
    USE SIGNAL ;
    PORT
      LAYER met3 ;
      RECT 999.320 820.270 1000.000 820.570 ;
    END
  END m_axis_rc_tuser[54]
  PIN m_axis_rc_tuser[55]
    DIRECTION OUTPUT ;
    USE SIGNAL ;
    PORT
      LAYER met3 ;
      RECT 999.320 821.630 1000.000 821.930 ;
    END
  END m_axis_rc_tuser[55]
  PIN m_axis_rc_tuser[56]
    DIRECTION OUTPUT ;
    USE SIGNAL ;
    PORT
      LAYER met3 ;
      RECT 999.320 822.990 1000.000 823.290 ;
    END
  END m_axis_rc_tuser[56]
  PIN m_axis_rc_tuser[57]
    DIRECTION OUTPUT ;
    USE SIGNAL ;
    PORT
      LAYER met3 ;
      RECT 999.320 824.350 1000.000 824.650 ;
    END
  END m_axis_rc_tuser[57]
  PIN m_axis_rc_tuser[58]
    DIRECTION OUTPUT ;
    USE SIGNAL ;
    PORT
      LAYER met3 ;
      RECT 999.320 825.710 1000.000 826.010 ;
    END
  END m_axis_rc_tuser[58]
  PIN m_axis_rc_tuser[59]
    DIRECTION OUTPUT ;
    USE SIGNAL ;
    PORT
      LAYER met3 ;
      RECT 999.320 827.070 1000.000 827.370 ;
    END
  END m_axis_rc_tuser[59]
  PIN m_axis_rc_tuser[60]
    DIRECTION OUTPUT ;
    USE SIGNAL ;
    PORT
      LAYER met3 ;
      RECT 999.320 828.430 1000.000 828.730 ;
    END
  END m_axis_rc_tuser[60]
  PIN m_axis_rc_tuser[61]
    DIRECTION OUTPUT ;
    USE SIGNAL ;
    PORT
      LAYER met3 ;
      RECT 999.320 829.790 1000.000 830.090 ;
    END
  END m_axis_rc_tuser[61]
  PIN m_axis_rc_tuser[62]
    DIRECTION OUTPUT ;
    USE SIGNAL ;
    PORT
      LAYER met3 ;
      RECT 999.320 831.150 1000.000 831.450 ;
    END
  END m_axis_rc_tuser[62]
  PIN m_axis_rc_tuser[63]
    DIRECTION OUTPUT ;
    USE SIGNAL ;
    PORT
      LAYER met3 ;
      RECT 999.320 832.510 1000.000 832.810 ;
    END
  END m_axis_rc_tuser[63]
  PIN m_axis_rc_tuser[64]
    DIRECTION OUTPUT ;
    USE SIGNAL ;
    PORT
      LAYER met3 ;
      RECT 999.320 833.870 1000.000 834.170 ;
    END
  END m_axis_rc_tuser[64]
  PIN m_axis_rc_tuser[65]
    DIRECTION OUTPUT ;
    USE SIGNAL ;
    PORT
      LAYER met3 ;
      RECT 999.320 835.230 1000.000 835.530 ;
    END
  END m_axis_rc_tuser[65]
  PIN m_axis_rc_tuser[66]
    DIRECTION OUTPUT ;
    USE SIGNAL ;
    PORT
      LAYER met3 ;
      RECT 999.320 836.590 1000.000 836.890 ;
    END
  END m_axis_rc_tuser[66]
  PIN m_axis_rc_tuser[67]
    DIRECTION OUTPUT ;
    USE SIGNAL ;
    PORT
      LAYER met3 ;
      RECT 999.320 837.950 1000.000 838.250 ;
    END
  END m_axis_rc_tuser[67]
  PIN m_axis_rc_tuser[68]
    DIRECTION OUTPUT ;
    USE SIGNAL ;
    PORT
      LAYER met3 ;
      RECT 999.320 839.310 1000.000 839.610 ;
    END
  END m_axis_rc_tuser[68]
  PIN m_axis_rc_tuser[69]
    DIRECTION OUTPUT ;
    USE SIGNAL ;
    PORT
      LAYER met3 ;
      RECT 999.320 840.670 1000.000 840.970 ;
    END
  END m_axis_rc_tuser[69]
  PIN m_axis_rc_tuser[70]
    DIRECTION OUTPUT ;
    USE SIGNAL ;
    PORT
      LAYER met3 ;
      RECT 999.320 842.030 1000.000 842.330 ;
    END
  END m_axis_rc_tuser[70]
  PIN m_axis_rc_tuser[71]
    DIRECTION OUTPUT ;
    USE SIGNAL ;
    PORT
      LAYER met3 ;
      RECT 999.320 843.390 1000.000 843.690 ;
    END
  END m_axis_rc_tuser[71]
  PIN m_axis_rc_tuser[72]
    DIRECTION OUTPUT ;
    USE SIGNAL ;
    PORT
      LAYER met3 ;
      RECT 999.320 844.750 1000.000 845.050 ;
    END
  END m_axis_rc_tuser[72]
  PIN m_axis_rc_tuser[73]
    DIRECTION OUTPUT ;
    USE SIGNAL ;
    PORT
      LAYER met3 ;
      RECT 999.320 846.110 1000.000 846.410 ;
    END
  END m_axis_rc_tuser[73]
  PIN m_axis_rc_tuser[74]
    DIRECTION OUTPUT ;
    USE SIGNAL ;
    PORT
      LAYER met3 ;
      RECT 999.320 847.470 1000.000 847.770 ;
    END
  END m_axis_rc_tuser[74]
  PIN m_axis_rc_tvalid
    DIRECTION OUTPUT ;
    USE SIGNAL ;
    PORT
      LAYER met3 ;
      RECT 999.320 848.830 1000.000 849.130 ;
    END
  END m_axis_rc_tvalid
  PIN pci_exp_txn
    DIRECTION OUTPUT ;
    USE SIGNAL ;
    PORT
      LAYER met3 ;
      RECT 999.320 850.190 1000.000 850.490 ;
    END
  END pci_exp_txn
  PIN pci_exp_txp
    DIRECTION OUTPUT ;
    USE SIGNAL ;
    PORT
      LAYER met3 ;
      RECT 999.320 851.550 1000.000 851.850 ;
    END
  END pci_exp_txp
  PIN pcie_perstn0_out
    DIRECTION OUTPUT ;
    USE SIGNAL ;
    PORT
      LAYER met3 ;
      RECT 999.320 852.910 1000.000 853.210 ;
    END
  END pcie_perstn0_out
  PIN pcie_perstn1_out
    DIRECTION OUTPUT ;
    USE SIGNAL ;
    PORT
      LAYER met3 ;
      RECT 999.320 854.270 1000.000 854.570 ;
    END
  END pcie_perstn1_out
  PIN pcie_rq_tag_av[0]
    DIRECTION OUTPUT ;
    USE SIGNAL ;
    PORT
      LAYER met3 ;
      RECT 999.320 855.630 1000.000 855.930 ;
    END
  END pcie_rq_tag_av[0]
  PIN pcie_rq_tag_av[1]
    DIRECTION OUTPUT ;
    USE SIGNAL ;
    PORT
      LAYER met3 ;
      RECT 999.320 856.990 1000.000 857.290 ;
    END
  END pcie_rq_tag_av[1]
  PIN pcie_rq_tag_av[2]
    DIRECTION OUTPUT ;
    USE SIGNAL ;
    PORT
      LAYER met3 ;
      RECT 999.320 858.350 1000.000 858.650 ;
    END
  END pcie_rq_tag_av[2]
  PIN pcie_rq_tag_av[3]
    DIRECTION OUTPUT ;
    USE SIGNAL ;
    PORT
      LAYER met3 ;
      RECT 999.320 859.710 1000.000 860.010 ;
    END
  END pcie_rq_tag_av[3]
  PIN pcie_tfc_npd_av[0]
    DIRECTION OUTPUT ;
    USE SIGNAL ;
    PORT
      LAYER met3 ;
      RECT 999.320 861.070 1000.000 861.370 ;
    END
  END pcie_tfc_npd_av[0]
  PIN pcie_tfc_npd_av[1]
    DIRECTION OUTPUT ;
    USE SIGNAL ;
    PORT
      LAYER met3 ;
      RECT 999.320 862.430 1000.000 862.730 ;
    END
  END pcie_tfc_npd_av[1]
  PIN pcie_tfc_npd_av[2]
    DIRECTION OUTPUT ;
    USE SIGNAL ;
    PORT
      LAYER met3 ;
      RECT 999.320 863.790 1000.000 864.090 ;
    END
  END pcie_tfc_npd_av[2]
  PIN pcie_tfc_npd_av[3]
    DIRECTION OUTPUT ;
    USE SIGNAL ;
    PORT
      LAYER met3 ;
      RECT 999.320 865.150 1000.000 865.450 ;
    END
  END pcie_tfc_npd_av[3]
  PIN pcie_tfc_nph_av[0]
    DIRECTION OUTPUT ;
    USE SIGNAL ;
    PORT
      LAYER met3 ;
      RECT 999.320 866.510 1000.000 866.810 ;
    END
  END pcie_tfc_nph_av[0]
  PIN pcie_tfc_nph_av[1]
    DIRECTION OUTPUT ;
    USE SIGNAL ;
    PORT
      LAYER met3 ;
      RECT 999.320 867.870 1000.000 868.170 ;
    END
  END pcie_tfc_nph_av[1]
  PIN pcie_tfc_nph_av[2]
    DIRECTION OUTPUT ;
    USE SIGNAL ;
    PORT
      LAYER met3 ;
      RECT 999.320 869.230 1000.000 869.530 ;
    END
  END pcie_tfc_nph_av[2]
  PIN pcie_tfc_nph_av[3]
    DIRECTION OUTPUT ;
    USE SIGNAL ;
    PORT
      LAYER met3 ;
      RECT 999.320 870.590 1000.000 870.890 ;
    END
  END pcie_tfc_nph_av[3]
  PIN phy_rdy_out
    DIRECTION OUTPUT ;
    USE SIGNAL ;
    PORT
      LAYER met3 ;
      RECT 999.320 871.950 1000.000 872.250 ;
    END
  END phy_rdy_out
  PIN s_axis_cc_tready[0]
    DIRECTION OUTPUT ;
    USE SIGNAL ;
    PORT
      LAYER met3 ;
      RECT 999.320 873.310 1000.000 873.610 ;
    END
  END s_axis_cc_tready[0]
  PIN s_axis_cc_tready[1]
    DIRECTION OUTPUT ;
    USE SIGNAL ;
    PORT
      LAYER met3 ;
      RECT 999.320 874.670 1000.000 874.970 ;
    END
  END s_axis_cc_tready[1]
  PIN s_axis_cc_tready[2]
    DIRECTION OUTPUT ;
    USE SIGNAL ;
    PORT
      LAYER met3 ;
      RECT 999.320 876.030 1000.000 876.330 ;
    END
  END s_axis_cc_tready[2]
  PIN s_axis_cc_tready[3]
    DIRECTION OUTPUT ;
    USE SIGNAL ;
    PORT
      LAYER met3 ;
      RECT 999.320 877.390 1000.000 877.690 ;
    END
  END s_axis_cc_tready[3]
  PIN s_axis_rq_tready[0]
    DIRECTION OUTPUT ;
    USE SIGNAL ;
    PORT
      LAYER met3 ;
      RECT 999.320 878.750 1000.000 879.050 ;
    END
  END s_axis_rq_tready[0]
  PIN s_axis_rq_tready[1]
    DIRECTION OUTPUT ;
    USE SIGNAL ;
    PORT
      LAYER met3 ;
      RECT 999.320 880.110 1000.000 880.410 ;
    END
  END s_axis_rq_tready[1]
  PIN s_axis_rq_tready[2]
    DIRECTION OUTPUT ;
    USE SIGNAL ;
    PORT
      LAYER met3 ;
      RECT 999.320 881.470 1000.000 881.770 ;
    END
  END s_axis_rq_tready[2]
  PIN s_axis_rq_tready[3]
    DIRECTION OUTPUT ;
    USE SIGNAL ;
    PORT
      LAYER met3 ;
      RECT 999.320 882.830 1000.000 883.130 ;
    END
  END s_axis_rq_tready[3]
  PIN user_clk
    DIRECTION OUTPUT ;
    USE SIGNAL ;
    PORT
      LAYER met3 ;
      RECT 999.320 884.190 1000.000 884.490 ;
    END
  END user_clk
  PIN user_lnk_up
    DIRECTION OUTPUT ;
    USE SIGNAL ;
    PORT
      LAYER met3 ;
      RECT 999.320 885.550 1000.000 885.850 ;
    END
  END user_lnk_up
  PIN user_reset
    DIRECTION OUTPUT ;
    USE SIGNAL ;
    PORT
      LAYER met3 ;
      RECT 999.320 886.910 1000.000 887.210 ;
    END
  END user_reset
END pcie_us

END LIBRARY
